VERSION 5.7 ;
  NOWIREEXTENSIONATPIN ON ;
  DIVIDERCHAR "/" ;
  BUSBITCHARS "[]" ;
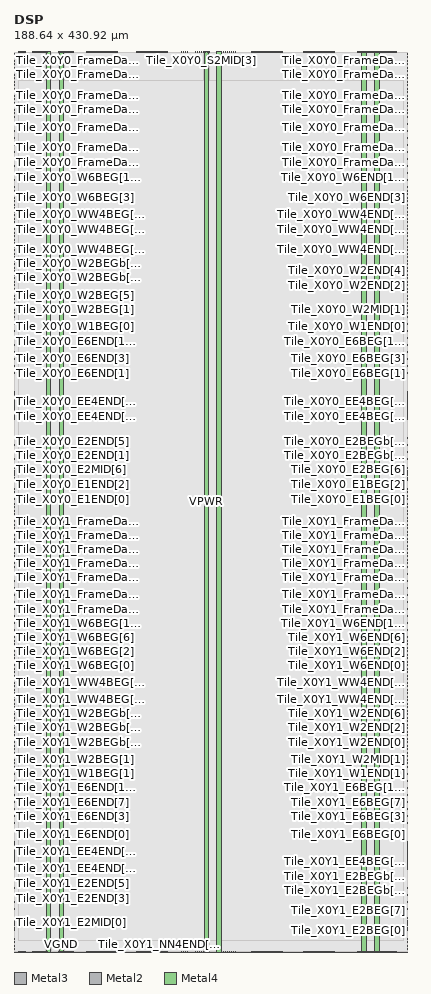
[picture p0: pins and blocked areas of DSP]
MACRO DSP
  CLASS BLOCK ;
  FOREIGN DSP ;
  ORIGIN 0.000 0.000 ;
  SIZE 188.640 BY 430.920 ;
  PIN Tile_X0Y0_E1BEG[0]
    DIRECTION OUTPUT ;
    USE SIGNAL ;
    ANTENNADIFFAREA 2.724000 ;
    PORT
      LAYER Metal3 ;
        RECT 188.240 216.520 188.640 216.920 ;
    END
  END Tile_X0Y0_E1BEG[0]
  PIN Tile_X0Y0_E1BEG[1]
    DIRECTION OUTPUT ;
    USE SIGNAL ;
    ANTENNADIFFAREA 2.724000 ;
    PORT
      LAYER Metal3 ;
        RECT 188.240 218.200 188.640 218.600 ;
    END
  END Tile_X0Y0_E1BEG[1]
  PIN Tile_X0Y0_E1BEG[2]
    DIRECTION OUTPUT ;
    USE SIGNAL ;
    ANTENNADIFFAREA 2.724000 ;
    PORT
      LAYER Metal3 ;
        RECT 188.240 219.880 188.640 220.280 ;
    END
  END Tile_X0Y0_E1BEG[2]
  PIN Tile_X0Y0_E1BEG[3]
    DIRECTION OUTPUT ;
    USE SIGNAL ;
    ANTENNADIFFAREA 2.724000 ;
    PORT
      LAYER Metal3 ;
        RECT 188.240 221.560 188.640 221.960 ;
    END
  END Tile_X0Y0_E1BEG[3]
  PIN Tile_X0Y0_E1END[0]
    DIRECTION INPUT ;
    USE SIGNAL ;
    ANTENNAGATEAREA 1.320800 ;
    PORT
      LAYER Metal3 ;
        RECT 0.000 216.520 0.400 216.920 ;
    END
  END Tile_X0Y0_E1END[0]
  PIN Tile_X0Y0_E1END[1]
    DIRECTION INPUT ;
    USE SIGNAL ;
    ANTENNAGATEAREA 1.899300 ;
    PORT
      LAYER Metal3 ;
        RECT 0.000 218.200 0.400 218.600 ;
    END
  END Tile_X0Y0_E1END[1]
  PIN Tile_X0Y0_E1END[2]
    DIRECTION INPUT ;
    USE SIGNAL ;
    ANTENNAGATEAREA 2.407100 ;
    PORT
      LAYER Metal3 ;
        RECT 0.000 219.880 0.400 220.280 ;
    END
  END Tile_X0Y0_E1END[2]
  PIN Tile_X0Y0_E1END[3]
    DIRECTION INPUT ;
    USE SIGNAL ;
    ANTENNAGATEAREA 2.397200 ;
    PORT
      LAYER Metal3 ;
        RECT 0.000 221.560 0.400 221.960 ;
    END
  END Tile_X0Y0_E1END[3]
  PIN Tile_X0Y0_E2BEG[0]
    DIRECTION OUTPUT ;
    USE SIGNAL ;
    ANTENNADIFFAREA 2.724000 ;
    PORT
      LAYER Metal3 ;
        RECT 188.240 225.760 188.640 226.160 ;
    END
  END Tile_X0Y0_E2BEG[0]
  PIN Tile_X0Y0_E2BEG[1]
    DIRECTION OUTPUT ;
    USE SIGNAL ;
    ANTENNADIFFAREA 2.724000 ;
    PORT
      LAYER Metal3 ;
        RECT 188.240 226.600 188.640 227.000 ;
    END
  END Tile_X0Y0_E2BEG[1]
  PIN Tile_X0Y0_E2BEG[2]
    DIRECTION OUTPUT ;
    USE SIGNAL ;
    ANTENNADIFFAREA 2.724000 ;
    PORT
      LAYER Metal3 ;
        RECT 188.240 227.440 188.640 227.840 ;
    END
  END Tile_X0Y0_E2BEG[2]
  PIN Tile_X0Y0_E2BEG[3]
    DIRECTION OUTPUT ;
    USE SIGNAL ;
    ANTENNADIFFAREA 2.724000 ;
    PORT
      LAYER Metal3 ;
        RECT 188.240 228.280 188.640 228.680 ;
    END
  END Tile_X0Y0_E2BEG[3]
  PIN Tile_X0Y0_E2BEG[4]
    DIRECTION OUTPUT ;
    USE SIGNAL ;
    ANTENNADIFFAREA 2.724000 ;
    PORT
      LAYER Metal3 ;
        RECT 188.240 229.120 188.640 229.520 ;
    END
  END Tile_X0Y0_E2BEG[4]
  PIN Tile_X0Y0_E2BEG[5]
    DIRECTION OUTPUT ;
    USE SIGNAL ;
    ANTENNADIFFAREA 2.724000 ;
    PORT
      LAYER Metal3 ;
        RECT 188.240 229.960 188.640 230.360 ;
    END
  END Tile_X0Y0_E2BEG[5]
  PIN Tile_X0Y0_E2BEG[6]
    DIRECTION OUTPUT ;
    USE SIGNAL ;
    ANTENNADIFFAREA 2.724000 ;
    PORT
      LAYER Metal3 ;
        RECT 188.240 230.800 188.640 231.200 ;
    END
  END Tile_X0Y0_E2BEG[6]
  PIN Tile_X0Y0_E2BEG[7]
    DIRECTION OUTPUT ;
    USE SIGNAL ;
    ANTENNADIFFAREA 2.724000 ;
    PORT
      LAYER Metal3 ;
        RECT 188.240 231.640 188.640 232.040 ;
    END
  END Tile_X0Y0_E2BEG[7]
  PIN Tile_X0Y0_E2BEGb[0]
    DIRECTION OUTPUT ;
    USE SIGNAL ;
    ANTENNADIFFAREA 2.724000 ;
    PORT
      LAYER Metal3 ;
        RECT 188.240 235.840 188.640 236.240 ;
    END
  END Tile_X0Y0_E2BEGb[0]
  PIN Tile_X0Y0_E2BEGb[1]
    DIRECTION OUTPUT ;
    USE SIGNAL ;
    ANTENNADIFFAREA 2.724000 ;
    PORT
      LAYER Metal3 ;
        RECT 188.240 237.520 188.640 237.920 ;
    END
  END Tile_X0Y0_E2BEGb[1]
  PIN Tile_X0Y0_E2BEGb[2]
    DIRECTION OUTPUT ;
    USE SIGNAL ;
    ANTENNADIFFAREA 2.724000 ;
    PORT
      LAYER Metal3 ;
        RECT 188.240 239.200 188.640 239.600 ;
    END
  END Tile_X0Y0_E2BEGb[2]
  PIN Tile_X0Y0_E2BEGb[3]
    DIRECTION OUTPUT ;
    USE SIGNAL ;
    ANTENNADIFFAREA 2.724000 ;
    PORT
      LAYER Metal3 ;
        RECT 188.240 240.880 188.640 241.280 ;
    END
  END Tile_X0Y0_E2BEGb[3]
  PIN Tile_X0Y0_E2BEGb[4]
    DIRECTION OUTPUT ;
    USE SIGNAL ;
    ANTENNADIFFAREA 2.724000 ;
    PORT
      LAYER Metal3 ;
        RECT 188.240 242.560 188.640 242.960 ;
    END
  END Tile_X0Y0_E2BEGb[4]
  PIN Tile_X0Y0_E2BEGb[5]
    DIRECTION OUTPUT ;
    USE SIGNAL ;
    ANTENNADIFFAREA 2.724000 ;
    PORT
      LAYER Metal3 ;
        RECT 188.240 244.240 188.640 244.640 ;
    END
  END Tile_X0Y0_E2BEGb[5]
  PIN Tile_X0Y0_E2BEGb[6]
    DIRECTION OUTPUT ;
    USE SIGNAL ;
    ANTENNADIFFAREA 2.724000 ;
    PORT
      LAYER Metal3 ;
        RECT 188.240 245.920 188.640 246.320 ;
    END
  END Tile_X0Y0_E2BEGb[6]
  PIN Tile_X0Y0_E2BEGb[7]
    DIRECTION OUTPUT ;
    USE SIGNAL ;
    ANTENNADIFFAREA 2.724000 ;
    PORT
      LAYER Metal3 ;
        RECT 188.240 247.600 188.640 248.000 ;
    END
  END Tile_X0Y0_E2BEGb[7]
  PIN Tile_X0Y0_E2END[0]
    DIRECTION INPUT ;
    USE SIGNAL ;
    ANTENNAGATEAREA 0.865800 ;
    PORT
      LAYER Metal3 ;
        RECT 0.000 235.840 0.400 236.240 ;
    END
  END Tile_X0Y0_E2END[0]
  PIN Tile_X0Y0_E2END[1]
    DIRECTION INPUT ;
    USE SIGNAL ;
    ANTENNAGATEAREA 0.820300 ;
    PORT
      LAYER Metal3 ;
        RECT 0.000 237.520 0.400 237.920 ;
    END
  END Tile_X0Y0_E2END[1]
  PIN Tile_X0Y0_E2END[2]
    DIRECTION INPUT ;
    USE SIGNAL ;
    ANTENNAGATEAREA 1.094600 ;
    PORT
      LAYER Metal3 ;
        RECT 0.000 239.200 0.400 239.600 ;
    END
  END Tile_X0Y0_E2END[2]
  PIN Tile_X0Y0_E2END[3]
    DIRECTION INPUT ;
    USE SIGNAL ;
    ANTENNAGATEAREA 1.123200 ;
    PORT
      LAYER Metal3 ;
        RECT 0.000 240.880 0.400 241.280 ;
    END
  END Tile_X0Y0_E2END[3]
  PIN Tile_X0Y0_E2END[4]
    DIRECTION INPUT ;
    USE SIGNAL ;
    ANTENNAGATEAREA 1.107600 ;
    PORT
      LAYER Metal3 ;
        RECT 0.000 242.560 0.400 242.960 ;
    END
  END Tile_X0Y0_E2END[4]
  PIN Tile_X0Y0_E2END[5]
    DIRECTION INPUT ;
    USE SIGNAL ;
    ANTENNAGATEAREA 1.292200 ;
    PORT
      LAYER Metal3 ;
        RECT 0.000 244.240 0.400 244.640 ;
    END
  END Tile_X0Y0_E2END[5]
  PIN Tile_X0Y0_E2END[6]
    DIRECTION INPUT ;
    USE SIGNAL ;
    ANTENNAGATEAREA 1.123200 ;
    PORT
      LAYER Metal3 ;
        RECT 0.000 245.920 0.400 246.320 ;
    END
  END Tile_X0Y0_E2END[6]
  PIN Tile_X0Y0_E2END[7]
    DIRECTION INPUT ;
    USE SIGNAL ;
    ANTENNAGATEAREA 0.936000 ;
    ANTENNADIFFAREA 50.384998 ;
    PORT
      LAYER Metal3 ;
        RECT 0.000 247.600 0.400 248.000 ;
    END
  END Tile_X0Y0_E2END[7]
  PIN Tile_X0Y0_E2MID[0]
    DIRECTION INPUT ;
    USE SIGNAL ;
    ANTENNAGATEAREA 0.820300 ;
    ANTENNADIFFAREA 32.246399 ;
    PORT
      LAYER Metal3 ;
        RECT 0.000 225.760 0.400 226.160 ;
    END
  END Tile_X0Y0_E2MID[0]
  PIN Tile_X0Y0_E2MID[1]
    DIRECTION INPUT ;
    USE SIGNAL ;
    ANTENNAGATEAREA 1.046500 ;
    PORT
      LAYER Metal3 ;
        RECT 0.000 226.600 0.400 227.000 ;
    END
  END Tile_X0Y0_E2MID[1]
  PIN Tile_X0Y0_E2MID[2]
    DIRECTION INPUT ;
    USE SIGNAL ;
    ANTENNAGATEAREA 0.877500 ;
    ANTENNADIFFAREA 32.246399 ;
    PORT
      LAYER Metal3 ;
        RECT 0.000 227.440 0.400 227.840 ;
    END
  END Tile_X0Y0_E2MID[2]
  PIN Tile_X0Y0_E2MID[3]
    DIRECTION INPUT ;
    USE SIGNAL ;
    ANTENNAGATEAREA 1.059500 ;
    ANTENNADIFFAREA 12.092400 ;
    PORT
      LAYER Metal3 ;
        RECT 0.000 228.280 0.400 228.680 ;
    END
  END Tile_X0Y0_E2MID[3]
  PIN Tile_X0Y0_E2MID[4]
    DIRECTION INPUT ;
    USE SIGNAL ;
    ANTENNAGATEAREA 0.635700 ;
    ANTENNADIFFAREA 18.138599 ;
    PORT
      LAYER Metal3 ;
        RECT 0.000 229.120 0.400 229.520 ;
    END
  END Tile_X0Y0_E2MID[4]
  PIN Tile_X0Y0_E2MID[5]
    DIRECTION INPUT ;
    USE SIGNAL ;
    ANTENNAGATEAREA 0.422500 ;
    ANTENNADIFFAREA 8.061600 ;
    PORT
      LAYER Metal3 ;
        RECT 0.000 229.960 0.400 230.360 ;
    END
  END Tile_X0Y0_E2MID[5]
  PIN Tile_X0Y0_E2MID[6]
    DIRECTION INPUT ;
    USE SIGNAL ;
    ANTENNAGATEAREA 0.635700 ;
    ANTENNADIFFAREA 18.138599 ;
    PORT
      LAYER Metal3 ;
        RECT 0.000 230.800 0.400 231.200 ;
    END
  END Tile_X0Y0_E2MID[6]
  PIN Tile_X0Y0_E2MID[7]
    DIRECTION INPUT ;
    USE SIGNAL ;
    ANTENNAGATEAREA 0.422500 ;
    ANTENNADIFFAREA 8.061600 ;
    PORT
      LAYER Metal3 ;
        RECT 0.000 231.640 0.400 232.040 ;
    END
  END Tile_X0Y0_E2MID[7]
  PIN Tile_X0Y0_E6BEG[0]
    DIRECTION OUTPUT ;
    USE SIGNAL ;
    ANTENNADIFFAREA 2.724000 ;
    PORT
      LAYER Metal3 ;
        RECT 188.240 275.320 188.640 275.720 ;
    END
  END Tile_X0Y0_E6BEG[0]
  PIN Tile_X0Y0_E6BEG[10]
    DIRECTION OUTPUT ;
    USE SIGNAL ;
    ANTENNADIFFAREA 2.724000 ;
    PORT
      LAYER Metal3 ;
        RECT 188.240 292.120 188.640 292.520 ;
    END
  END Tile_X0Y0_E6BEG[10]
  PIN Tile_X0Y0_E6BEG[11]
    DIRECTION OUTPUT ;
    USE SIGNAL ;
    ANTENNADIFFAREA 2.724000 ;
    PORT
      LAYER Metal3 ;
        RECT 188.240 293.800 188.640 294.200 ;
    END
  END Tile_X0Y0_E6BEG[11]
  PIN Tile_X0Y0_E6BEG[1]
    DIRECTION OUTPUT ;
    USE SIGNAL ;
    ANTENNADIFFAREA 2.724000 ;
    PORT
      LAYER Metal3 ;
        RECT 188.240 277.000 188.640 277.400 ;
    END
  END Tile_X0Y0_E6BEG[1]
  PIN Tile_X0Y0_E6BEG[2]
    DIRECTION OUTPUT ;
    USE SIGNAL ;
    ANTENNADIFFAREA 2.724000 ;
    PORT
      LAYER Metal3 ;
        RECT 188.240 278.680 188.640 279.080 ;
    END
  END Tile_X0Y0_E6BEG[2]
  PIN Tile_X0Y0_E6BEG[3]
    DIRECTION OUTPUT ;
    USE SIGNAL ;
    ANTENNADIFFAREA 2.724000 ;
    PORT
      LAYER Metal3 ;
        RECT 188.240 280.360 188.640 280.760 ;
    END
  END Tile_X0Y0_E6BEG[3]
  PIN Tile_X0Y0_E6BEG[4]
    DIRECTION OUTPUT ;
    USE SIGNAL ;
    ANTENNADIFFAREA 2.724000 ;
    PORT
      LAYER Metal3 ;
        RECT 188.240 282.040 188.640 282.440 ;
    END
  END Tile_X0Y0_E6BEG[4]
  PIN Tile_X0Y0_E6BEG[5]
    DIRECTION OUTPUT ;
    USE SIGNAL ;
    ANTENNADIFFAREA 2.724000 ;
    PORT
      LAYER Metal3 ;
        RECT 188.240 283.720 188.640 284.120 ;
    END
  END Tile_X0Y0_E6BEG[5]
  PIN Tile_X0Y0_E6BEG[6]
    DIRECTION OUTPUT ;
    USE SIGNAL ;
    ANTENNADIFFAREA 2.724000 ;
    PORT
      LAYER Metal3 ;
        RECT 188.240 285.400 188.640 285.800 ;
    END
  END Tile_X0Y0_E6BEG[6]
  PIN Tile_X0Y0_E6BEG[7]
    DIRECTION OUTPUT ;
    USE SIGNAL ;
    ANTENNADIFFAREA 2.724000 ;
    PORT
      LAYER Metal3 ;
        RECT 188.240 287.080 188.640 287.480 ;
    END
  END Tile_X0Y0_E6BEG[7]
  PIN Tile_X0Y0_E6BEG[8]
    DIRECTION OUTPUT ;
    USE SIGNAL ;
    ANTENNADIFFAREA 2.724000 ;
    PORT
      LAYER Metal3 ;
        RECT 188.240 288.760 188.640 289.160 ;
    END
  END Tile_X0Y0_E6BEG[8]
  PIN Tile_X0Y0_E6BEG[9]
    DIRECTION OUTPUT ;
    USE SIGNAL ;
    ANTENNADIFFAREA 2.724000 ;
    PORT
      LAYER Metal3 ;
        RECT 188.240 290.440 188.640 290.840 ;
    END
  END Tile_X0Y0_E6BEG[9]
  PIN Tile_X0Y0_E6END[0]
    DIRECTION INPUT ;
    USE SIGNAL ;
    ANTENNAGATEAREA 2.239400 ;
    PORT
      LAYER Metal3 ;
        RECT 0.000 275.320 0.400 275.720 ;
    END
  END Tile_X0Y0_E6END[0]
  PIN Tile_X0Y0_E6END[10]
    DIRECTION INPUT ;
    USE SIGNAL ;
    ANTENNAGATEAREA 0.180700 ;
    PORT
      LAYER Metal3 ;
        RECT 0.000 292.120 0.400 292.520 ;
    END
  END Tile_X0Y0_E6END[10]
  PIN Tile_X0Y0_E6END[11]
    DIRECTION INPUT ;
    USE SIGNAL ;
    ANTENNAGATEAREA 0.180700 ;
    PORT
      LAYER Metal3 ;
        RECT 0.000 293.800 0.400 294.200 ;
    END
  END Tile_X0Y0_E6END[11]
  PIN Tile_X0Y0_E6END[1]
    DIRECTION INPUT ;
    USE SIGNAL ;
    ANTENNAGATEAREA 2.547000 ;
    PORT
      LAYER Metal3 ;
        RECT 0.000 277.000 0.400 277.400 ;
    END
  END Tile_X0Y0_E6END[1]
  PIN Tile_X0Y0_E6END[2]
    DIRECTION INPUT ;
    USE SIGNAL ;
    ANTENNAGATEAREA 0.180700 ;
    PORT
      LAYER Metal3 ;
        RECT 0.000 278.680 0.400 279.080 ;
    END
  END Tile_X0Y0_E6END[2]
  PIN Tile_X0Y0_E6END[3]
    DIRECTION INPUT ;
    USE SIGNAL ;
    ANTENNAGATEAREA 0.180700 ;
    PORT
      LAYER Metal3 ;
        RECT 0.000 280.360 0.400 280.760 ;
    END
  END Tile_X0Y0_E6END[3]
  PIN Tile_X0Y0_E6END[4]
    DIRECTION INPUT ;
    USE SIGNAL ;
    ANTENNAGATEAREA 0.180700 ;
    PORT
      LAYER Metal3 ;
        RECT 0.000 282.040 0.400 282.440 ;
    END
  END Tile_X0Y0_E6END[4]
  PIN Tile_X0Y0_E6END[5]
    DIRECTION INPUT ;
    USE SIGNAL ;
    ANTENNAGATEAREA 0.180700 ;
    PORT
      LAYER Metal3 ;
        RECT 0.000 283.720 0.400 284.120 ;
    END
  END Tile_X0Y0_E6END[5]
  PIN Tile_X0Y0_E6END[6]
    DIRECTION INPUT ;
    USE SIGNAL ;
    ANTENNAGATEAREA 0.180700 ;
    PORT
      LAYER Metal3 ;
        RECT 0.000 285.400 0.400 285.800 ;
    END
  END Tile_X0Y0_E6END[6]
  PIN Tile_X0Y0_E6END[7]
    DIRECTION INPUT ;
    USE SIGNAL ;
    ANTENNAGATEAREA 0.180700 ;
    PORT
      LAYER Metal3 ;
        RECT 0.000 287.080 0.400 287.480 ;
    END
  END Tile_X0Y0_E6END[7]
  PIN Tile_X0Y0_E6END[8]
    DIRECTION INPUT ;
    USE SIGNAL ;
    ANTENNAGATEAREA 0.180700 ;
    PORT
      LAYER Metal3 ;
        RECT 0.000 288.760 0.400 289.160 ;
    END
  END Tile_X0Y0_E6END[8]
  PIN Tile_X0Y0_E6END[9]
    DIRECTION INPUT ;
    USE SIGNAL ;
    ANTENNAGATEAREA 0.180700 ;
    PORT
      LAYER Metal3 ;
        RECT 0.000 290.440 0.400 290.840 ;
    END
  END Tile_X0Y0_E6END[9]
  PIN Tile_X0Y0_EE4BEG[0]
    DIRECTION OUTPUT ;
    USE SIGNAL ;
    ANTENNADIFFAREA 2.724000 ;
    PORT
      LAYER Metal3 ;
        RECT 188.240 255.160 188.640 255.560 ;
    END
  END Tile_X0Y0_EE4BEG[0]
  PIN Tile_X0Y0_EE4BEG[10]
    DIRECTION OUTPUT ;
    USE SIGNAL ;
    ANTENNADIFFAREA 2.724000 ;
    PORT
      LAYER Metal3 ;
        RECT 188.240 263.560 188.640 263.960 ;
    END
  END Tile_X0Y0_EE4BEG[10]
  PIN Tile_X0Y0_EE4BEG[11]
    DIRECTION OUTPUT ;
    USE SIGNAL ;
    ANTENNADIFFAREA 2.724000 ;
    PORT
      LAYER Metal3 ;
        RECT 188.240 264.400 188.640 264.800 ;
    END
  END Tile_X0Y0_EE4BEG[11]
  PIN Tile_X0Y0_EE4BEG[12]
    DIRECTION OUTPUT ;
    USE SIGNAL ;
    ANTENNADIFFAREA 2.724000 ;
    PORT
      LAYER Metal3 ;
        RECT 188.240 265.240 188.640 265.640 ;
    END
  END Tile_X0Y0_EE4BEG[12]
  PIN Tile_X0Y0_EE4BEG[13]
    DIRECTION OUTPUT ;
    USE SIGNAL ;
    ANTENNADIFFAREA 2.724000 ;
    PORT
      LAYER Metal3 ;
        RECT 188.240 266.080 188.640 266.480 ;
    END
  END Tile_X0Y0_EE4BEG[13]
  PIN Tile_X0Y0_EE4BEG[14]
    DIRECTION OUTPUT ;
    USE SIGNAL ;
    ANTENNADIFFAREA 2.724000 ;
    PORT
      LAYER Metal3 ;
        RECT 188.240 266.920 188.640 267.320 ;
    END
  END Tile_X0Y0_EE4BEG[14]
  PIN Tile_X0Y0_EE4BEG[15]
    DIRECTION OUTPUT ;
    USE SIGNAL ;
    ANTENNADIFFAREA 2.724000 ;
    PORT
      LAYER Metal3 ;
        RECT 188.240 267.760 188.640 268.160 ;
    END
  END Tile_X0Y0_EE4BEG[15]
  PIN Tile_X0Y0_EE4BEG[1]
    DIRECTION OUTPUT ;
    USE SIGNAL ;
    ANTENNADIFFAREA 2.724000 ;
    PORT
      LAYER Metal3 ;
        RECT 188.240 256.000 188.640 256.400 ;
    END
  END Tile_X0Y0_EE4BEG[1]
  PIN Tile_X0Y0_EE4BEG[2]
    DIRECTION OUTPUT ;
    USE SIGNAL ;
    ANTENNADIFFAREA 2.724000 ;
    PORT
      LAYER Metal3 ;
        RECT 188.240 256.840 188.640 257.240 ;
    END
  END Tile_X0Y0_EE4BEG[2]
  PIN Tile_X0Y0_EE4BEG[3]
    DIRECTION OUTPUT ;
    USE SIGNAL ;
    ANTENNADIFFAREA 2.724000 ;
    PORT
      LAYER Metal3 ;
        RECT 188.240 257.680 188.640 258.080 ;
    END
  END Tile_X0Y0_EE4BEG[3]
  PIN Tile_X0Y0_EE4BEG[4]
    DIRECTION OUTPUT ;
    USE SIGNAL ;
    ANTENNADIFFAREA 2.724000 ;
    PORT
      LAYER Metal3 ;
        RECT 188.240 258.520 188.640 258.920 ;
    END
  END Tile_X0Y0_EE4BEG[4]
  PIN Tile_X0Y0_EE4BEG[5]
    DIRECTION OUTPUT ;
    USE SIGNAL ;
    ANTENNADIFFAREA 2.724000 ;
    PORT
      LAYER Metal3 ;
        RECT 188.240 259.360 188.640 259.760 ;
    END
  END Tile_X0Y0_EE4BEG[5]
  PIN Tile_X0Y0_EE4BEG[6]
    DIRECTION OUTPUT ;
    USE SIGNAL ;
    ANTENNADIFFAREA 2.724000 ;
    PORT
      LAYER Metal3 ;
        RECT 188.240 260.200 188.640 260.600 ;
    END
  END Tile_X0Y0_EE4BEG[6]
  PIN Tile_X0Y0_EE4BEG[7]
    DIRECTION OUTPUT ;
    USE SIGNAL ;
    ANTENNADIFFAREA 2.724000 ;
    PORT
      LAYER Metal3 ;
        RECT 188.240 261.040 188.640 261.440 ;
    END
  END Tile_X0Y0_EE4BEG[7]
  PIN Tile_X0Y0_EE4BEG[8]
    DIRECTION OUTPUT ;
    USE SIGNAL ;
    ANTENNADIFFAREA 2.724000 ;
    PORT
      LAYER Metal3 ;
        RECT 188.240 261.880 188.640 262.280 ;
    END
  END Tile_X0Y0_EE4BEG[8]
  PIN Tile_X0Y0_EE4BEG[9]
    DIRECTION OUTPUT ;
    USE SIGNAL ;
    ANTENNADIFFAREA 2.724000 ;
    PORT
      LAYER Metal3 ;
        RECT 188.240 262.720 188.640 263.120 ;
    END
  END Tile_X0Y0_EE4BEG[9]
  PIN Tile_X0Y0_EE4END[0]
    DIRECTION INPUT ;
    USE SIGNAL ;
    ANTENNAGATEAREA 0.607100 ;
    PORT
      LAYER Metal3 ;
        RECT 0.000 255.160 0.400 255.560 ;
    END
  END Tile_X0Y0_EE4END[0]
  PIN Tile_X0Y0_EE4END[10]
    DIRECTION INPUT ;
    USE SIGNAL ;
    ANTENNAGATEAREA 0.180700 ;
    PORT
      LAYER Metal3 ;
        RECT 0.000 263.560 0.400 263.960 ;
    END
  END Tile_X0Y0_EE4END[10]
  PIN Tile_X0Y0_EE4END[11]
    DIRECTION INPUT ;
    USE SIGNAL ;
    ANTENNAGATEAREA 0.180700 ;
    PORT
      LAYER Metal3 ;
        RECT 0.000 264.400 0.400 264.800 ;
    END
  END Tile_X0Y0_EE4END[11]
  PIN Tile_X0Y0_EE4END[12]
    DIRECTION INPUT ;
    USE SIGNAL ;
    ANTENNAGATEAREA 0.180700 ;
    PORT
      LAYER Metal3 ;
        RECT 0.000 265.240 0.400 265.640 ;
    END
  END Tile_X0Y0_EE4END[12]
  PIN Tile_X0Y0_EE4END[13]
    DIRECTION INPUT ;
    USE SIGNAL ;
    ANTENNAGATEAREA 0.180700 ;
    PORT
      LAYER Metal3 ;
        RECT 0.000 266.080 0.400 266.480 ;
    END
  END Tile_X0Y0_EE4END[13]
  PIN Tile_X0Y0_EE4END[14]
    DIRECTION INPUT ;
    USE SIGNAL ;
    ANTENNAGATEAREA 0.180700 ;
    PORT
      LAYER Metal3 ;
        RECT 0.000 266.920 0.400 267.320 ;
    END
  END Tile_X0Y0_EE4END[14]
  PIN Tile_X0Y0_EE4END[15]
    DIRECTION INPUT ;
    USE SIGNAL ;
    ANTENNAGATEAREA 0.180700 ;
    PORT
      LAYER Metal3 ;
        RECT 0.000 267.760 0.400 268.160 ;
    END
  END Tile_X0Y0_EE4END[15]
  PIN Tile_X0Y0_EE4END[1]
    DIRECTION INPUT ;
    USE SIGNAL ;
    ANTENNAGATEAREA 0.681200 ;
    PORT
      LAYER Metal3 ;
        RECT 0.000 256.000 0.400 256.400 ;
    END
  END Tile_X0Y0_EE4END[1]
  PIN Tile_X0Y0_EE4END[2]
    DIRECTION INPUT ;
    USE SIGNAL ;
    ANTENNAGATEAREA 0.718400 ;
    PORT
      LAYER Metal3 ;
        RECT 0.000 256.840 0.400 257.240 ;
    END
  END Tile_X0Y0_EE4END[2]
  PIN Tile_X0Y0_EE4END[3]
    DIRECTION INPUT ;
    USE SIGNAL ;
    ANTENNAGATEAREA 0.492200 ;
    PORT
      LAYER Metal3 ;
        RECT 0.000 257.680 0.400 258.080 ;
    END
  END Tile_X0Y0_EE4END[3]
  PIN Tile_X0Y0_EE4END[4]
    DIRECTION INPUT ;
    USE SIGNAL ;
    ANTENNAGATEAREA 0.180700 ;
    PORT
      LAYER Metal3 ;
        RECT 0.000 258.520 0.400 258.920 ;
    END
  END Tile_X0Y0_EE4END[4]
  PIN Tile_X0Y0_EE4END[5]
    DIRECTION INPUT ;
    USE SIGNAL ;
    ANTENNAGATEAREA 0.180700 ;
    PORT
      LAYER Metal3 ;
        RECT 0.000 259.360 0.400 259.760 ;
    END
  END Tile_X0Y0_EE4END[5]
  PIN Tile_X0Y0_EE4END[6]
    DIRECTION INPUT ;
    USE SIGNAL ;
    ANTENNAGATEAREA 0.180700 ;
    PORT
      LAYER Metal3 ;
        RECT 0.000 260.200 0.400 260.600 ;
    END
  END Tile_X0Y0_EE4END[6]
  PIN Tile_X0Y0_EE4END[7]
    DIRECTION INPUT ;
    USE SIGNAL ;
    ANTENNAGATEAREA 0.180700 ;
    PORT
      LAYER Metal3 ;
        RECT 0.000 261.040 0.400 261.440 ;
    END
  END Tile_X0Y0_EE4END[7]
  PIN Tile_X0Y0_EE4END[8]
    DIRECTION INPUT ;
    USE SIGNAL ;
    ANTENNAGATEAREA 0.180700 ;
    PORT
      LAYER Metal3 ;
        RECT 0.000 261.880 0.400 262.280 ;
    END
  END Tile_X0Y0_EE4END[8]
  PIN Tile_X0Y0_EE4END[9]
    DIRECTION INPUT ;
    USE SIGNAL ;
    ANTENNAGATEAREA 0.180700 ;
    PORT
      LAYER Metal3 ;
        RECT 0.000 262.720 0.400 263.120 ;
    END
  END Tile_X0Y0_EE4END[9]
  PIN Tile_X0Y0_FrameData[0]
    DIRECTION INPUT ;
    USE SIGNAL ;
    ANTENNAGATEAREA 2.349100 ;
    PORT
      LAYER Metal3 ;
        RECT 0.000 377.800 0.400 378.200 ;
    END
  END Tile_X0Y0_FrameData[0]
  PIN Tile_X0Y0_FrameData[10]
    DIRECTION INPUT ;
    USE SIGNAL ;
    ANTENNAGATEAREA 2.529800 ;
    PORT
      LAYER Metal3 ;
        RECT 0.000 394.600 0.400 395.000 ;
    END
  END Tile_X0Y0_FrameData[10]
  PIN Tile_X0Y0_FrameData[11]
    DIRECTION INPUT ;
    USE SIGNAL ;
    ANTENNAGATEAREA 2.529800 ;
    PORT
      LAYER Metal3 ;
        RECT 0.000 396.280 0.400 396.680 ;
    END
  END Tile_X0Y0_FrameData[11]
  PIN Tile_X0Y0_FrameData[12]
    DIRECTION INPUT ;
    USE SIGNAL ;
    ANTENNAGATEAREA 2.529800 ;
    PORT
      LAYER Metal3 ;
        RECT 0.000 397.960 0.400 398.360 ;
    END
  END Tile_X0Y0_FrameData[12]
  PIN Tile_X0Y0_FrameData[13]
    DIRECTION INPUT ;
    USE SIGNAL ;
    ANTENNAGATEAREA 2.529800 ;
    PORT
      LAYER Metal3 ;
        RECT 0.000 399.640 0.400 400.040 ;
    END
  END Tile_X0Y0_FrameData[13]
  PIN Tile_X0Y0_FrameData[14]
    DIRECTION INPUT ;
    USE SIGNAL ;
    ANTENNAGATEAREA 2.529800 ;
    PORT
      LAYER Metal3 ;
        RECT 0.000 401.320 0.400 401.720 ;
    END
  END Tile_X0Y0_FrameData[14]
  PIN Tile_X0Y0_FrameData[15]
    DIRECTION INPUT ;
    USE SIGNAL ;
    ANTENNAGATEAREA 2.529800 ;
    PORT
      LAYER Metal3 ;
        RECT 0.000 403.000 0.400 403.400 ;
    END
  END Tile_X0Y0_FrameData[15]
  PIN Tile_X0Y0_FrameData[16]
    DIRECTION INPUT ;
    USE SIGNAL ;
    ANTENNAGATEAREA 2.529800 ;
    PORT
      LAYER Metal3 ;
        RECT 0.000 404.680 0.400 405.080 ;
    END
  END Tile_X0Y0_FrameData[16]
  PIN Tile_X0Y0_FrameData[17]
    DIRECTION INPUT ;
    USE SIGNAL ;
    ANTENNAGATEAREA 2.529800 ;
    PORT
      LAYER Metal3 ;
        RECT 0.000 406.360 0.400 406.760 ;
    END
  END Tile_X0Y0_FrameData[17]
  PIN Tile_X0Y0_FrameData[18]
    DIRECTION INPUT ;
    USE SIGNAL ;
    ANTENNAGATEAREA 2.529800 ;
    PORT
      LAYER Metal3 ;
        RECT 0.000 408.040 0.400 408.440 ;
    END
  END Tile_X0Y0_FrameData[18]
  PIN Tile_X0Y0_FrameData[19]
    DIRECTION INPUT ;
    USE SIGNAL ;
    ANTENNAGATEAREA 2.529800 ;
    PORT
      LAYER Metal3 ;
        RECT 0.000 409.720 0.400 410.120 ;
    END
  END Tile_X0Y0_FrameData[19]
  PIN Tile_X0Y0_FrameData[1]
    DIRECTION INPUT ;
    USE SIGNAL ;
    ANTENNAGATEAREA 2.349100 ;
    PORT
      LAYER Metal3 ;
        RECT 0.000 379.480 0.400 379.880 ;
    END
  END Tile_X0Y0_FrameData[1]
  PIN Tile_X0Y0_FrameData[20]
    DIRECTION INPUT ;
    USE SIGNAL ;
    ANTENNAGATEAREA 2.529800 ;
    PORT
      LAYER Metal3 ;
        RECT 0.000 411.400 0.400 411.800 ;
    END
  END Tile_X0Y0_FrameData[20]
  PIN Tile_X0Y0_FrameData[21]
    DIRECTION INPUT ;
    USE SIGNAL ;
    ANTENNAGATEAREA 2.529800 ;
    PORT
      LAYER Metal3 ;
        RECT 0.000 413.080 0.400 413.480 ;
    END
  END Tile_X0Y0_FrameData[21]
  PIN Tile_X0Y0_FrameData[22]
    DIRECTION INPUT ;
    USE SIGNAL ;
    ANTENNAGATEAREA 2.529800 ;
    PORT
      LAYER Metal3 ;
        RECT 0.000 414.760 0.400 415.160 ;
    END
  END Tile_X0Y0_FrameData[22]
  PIN Tile_X0Y0_FrameData[23]
    DIRECTION INPUT ;
    USE SIGNAL ;
    ANTENNAGATEAREA 2.529800 ;
    PORT
      LAYER Metal3 ;
        RECT 0.000 416.440 0.400 416.840 ;
    END
  END Tile_X0Y0_FrameData[23]
  PIN Tile_X0Y0_FrameData[24]
    DIRECTION INPUT ;
    USE SIGNAL ;
    ANTENNAGATEAREA 2.529800 ;
    PORT
      LAYER Metal3 ;
        RECT 0.000 418.120 0.400 418.520 ;
    END
  END Tile_X0Y0_FrameData[24]
  PIN Tile_X0Y0_FrameData[25]
    DIRECTION INPUT ;
    USE SIGNAL ;
    ANTENNAGATEAREA 2.529800 ;
    PORT
      LAYER Metal3 ;
        RECT 0.000 419.800 0.400 420.200 ;
    END
  END Tile_X0Y0_FrameData[25]
  PIN Tile_X0Y0_FrameData[26]
    DIRECTION INPUT ;
    USE SIGNAL ;
    ANTENNAGATEAREA 2.529800 ;
    PORT
      LAYER Metal3 ;
        RECT 0.000 421.480 0.400 421.880 ;
    END
  END Tile_X0Y0_FrameData[26]
  PIN Tile_X0Y0_FrameData[27]
    DIRECTION INPUT ;
    USE SIGNAL ;
    ANTENNAGATEAREA 2.529800 ;
    PORT
      LAYER Metal3 ;
        RECT 0.000 423.160 0.400 423.560 ;
    END
  END Tile_X0Y0_FrameData[27]
  PIN Tile_X0Y0_FrameData[28]
    DIRECTION INPUT ;
    USE SIGNAL ;
    ANTENNAGATEAREA 2.529800 ;
    PORT
      LAYER Metal3 ;
        RECT 0.000 424.840 0.400 425.240 ;
    END
  END Tile_X0Y0_FrameData[28]
  PIN Tile_X0Y0_FrameData[29]
    DIRECTION INPUT ;
    USE SIGNAL ;
    ANTENNAGATEAREA 2.529800 ;
    PORT
      LAYER Metal3 ;
        RECT 0.000 426.520 0.400 426.920 ;
    END
  END Tile_X0Y0_FrameData[29]
  PIN Tile_X0Y0_FrameData[2]
    DIRECTION INPUT ;
    USE SIGNAL ;
    ANTENNAGATEAREA 2.349100 ;
    PORT
      LAYER Metal3 ;
        RECT 0.000 381.160 0.400 381.560 ;
    END
  END Tile_X0Y0_FrameData[2]
  PIN Tile_X0Y0_FrameData[30]
    DIRECTION INPUT ;
    USE SIGNAL ;
    ANTENNAGATEAREA 2.529800 ;
    PORT
      LAYER Metal3 ;
        RECT 0.000 428.200 0.400 428.600 ;
    END
  END Tile_X0Y0_FrameData[30]
  PIN Tile_X0Y0_FrameData[31]
    DIRECTION INPUT ;
    USE SIGNAL ;
    ANTENNAGATEAREA 2.529800 ;
    PORT
      LAYER Metal3 ;
        RECT 0.000 429.880 0.400 430.280 ;
    END
  END Tile_X0Y0_FrameData[31]
  PIN Tile_X0Y0_FrameData[3]
    DIRECTION INPUT ;
    USE SIGNAL ;
    ANTENNAGATEAREA 2.349100 ;
    PORT
      LAYER Metal3 ;
        RECT 0.000 382.840 0.400 383.240 ;
    END
  END Tile_X0Y0_FrameData[3]
  PIN Tile_X0Y0_FrameData[4]
    DIRECTION INPUT ;
    USE SIGNAL ;
    ANTENNAGATEAREA 2.349100 ;
    PORT
      LAYER Metal3 ;
        RECT 0.000 384.520 0.400 384.920 ;
    END
  END Tile_X0Y0_FrameData[4]
  PIN Tile_X0Y0_FrameData[5]
    DIRECTION INPUT ;
    USE SIGNAL ;
    ANTENNAGATEAREA 2.349100 ;
    PORT
      LAYER Metal3 ;
        RECT 0.000 386.200 0.400 386.600 ;
    END
  END Tile_X0Y0_FrameData[5]
  PIN Tile_X0Y0_FrameData[6]
    DIRECTION INPUT ;
    USE SIGNAL ;
    ANTENNAGATEAREA 2.349100 ;
    PORT
      LAYER Metal3 ;
        RECT 0.000 387.880 0.400 388.280 ;
    END
  END Tile_X0Y0_FrameData[6]
  PIN Tile_X0Y0_FrameData[7]
    DIRECTION INPUT ;
    USE SIGNAL ;
    ANTENNAGATEAREA 2.349100 ;
    PORT
      LAYER Metal3 ;
        RECT 0.000 389.560 0.400 389.960 ;
    END
  END Tile_X0Y0_FrameData[7]
  PIN Tile_X0Y0_FrameData[8]
    DIRECTION INPUT ;
    USE SIGNAL ;
    ANTENNAGATEAREA 2.349100 ;
    PORT
      LAYER Metal3 ;
        RECT 0.000 391.240 0.400 391.640 ;
    END
  END Tile_X0Y0_FrameData[8]
  PIN Tile_X0Y0_FrameData[9]
    DIRECTION INPUT ;
    USE SIGNAL ;
    ANTENNAGATEAREA 2.349100 ;
    PORT
      LAYER Metal3 ;
        RECT 0.000 392.920 0.400 393.320 ;
    END
  END Tile_X0Y0_FrameData[9]
  PIN Tile_X0Y0_FrameData_O[0]
    DIRECTION OUTPUT ;
    USE SIGNAL ;
    ANTENNADIFFAREA 2.724000 ;
    PORT
      LAYER Metal3 ;
        RECT 188.240 377.800 188.640 378.200 ;
    END
  END Tile_X0Y0_FrameData_O[0]
  PIN Tile_X0Y0_FrameData_O[10]
    DIRECTION OUTPUT ;
    USE SIGNAL ;
    ANTENNADIFFAREA 2.724000 ;
    PORT
      LAYER Metal3 ;
        RECT 188.240 394.600 188.640 395.000 ;
    END
  END Tile_X0Y0_FrameData_O[10]
  PIN Tile_X0Y0_FrameData_O[11]
    DIRECTION OUTPUT ;
    USE SIGNAL ;
    ANTENNADIFFAREA 2.724000 ;
    PORT
      LAYER Metal3 ;
        RECT 188.240 396.280 188.640 396.680 ;
    END
  END Tile_X0Y0_FrameData_O[11]
  PIN Tile_X0Y0_FrameData_O[12]
    DIRECTION OUTPUT ;
    USE SIGNAL ;
    ANTENNADIFFAREA 2.724000 ;
    PORT
      LAYER Metal3 ;
        RECT 188.240 397.960 188.640 398.360 ;
    END
  END Tile_X0Y0_FrameData_O[12]
  PIN Tile_X0Y0_FrameData_O[13]
    DIRECTION OUTPUT ;
    USE SIGNAL ;
    ANTENNADIFFAREA 2.724000 ;
    PORT
      LAYER Metal3 ;
        RECT 188.240 399.640 188.640 400.040 ;
    END
  END Tile_X0Y0_FrameData_O[13]
  PIN Tile_X0Y0_FrameData_O[14]
    DIRECTION OUTPUT ;
    USE SIGNAL ;
    ANTENNADIFFAREA 2.724000 ;
    PORT
      LAYER Metal3 ;
        RECT 188.240 401.320 188.640 401.720 ;
    END
  END Tile_X0Y0_FrameData_O[14]
  PIN Tile_X0Y0_FrameData_O[15]
    DIRECTION OUTPUT ;
    USE SIGNAL ;
    ANTENNADIFFAREA 2.724000 ;
    PORT
      LAYER Metal3 ;
        RECT 188.240 403.000 188.640 403.400 ;
    END
  END Tile_X0Y0_FrameData_O[15]
  PIN Tile_X0Y0_FrameData_O[16]
    DIRECTION OUTPUT ;
    USE SIGNAL ;
    ANTENNADIFFAREA 2.724000 ;
    PORT
      LAYER Metal3 ;
        RECT 188.240 404.680 188.640 405.080 ;
    END
  END Tile_X0Y0_FrameData_O[16]
  PIN Tile_X0Y0_FrameData_O[17]
    DIRECTION OUTPUT ;
    USE SIGNAL ;
    ANTENNADIFFAREA 2.724000 ;
    PORT
      LAYER Metal3 ;
        RECT 188.240 406.360 188.640 406.760 ;
    END
  END Tile_X0Y0_FrameData_O[17]
  PIN Tile_X0Y0_FrameData_O[18]
    DIRECTION OUTPUT ;
    USE SIGNAL ;
    ANTENNADIFFAREA 2.724000 ;
    PORT
      LAYER Metal3 ;
        RECT 188.240 408.040 188.640 408.440 ;
    END
  END Tile_X0Y0_FrameData_O[18]
  PIN Tile_X0Y0_FrameData_O[19]
    DIRECTION OUTPUT ;
    USE SIGNAL ;
    ANTENNADIFFAREA 2.724000 ;
    PORT
      LAYER Metal3 ;
        RECT 188.240 409.720 188.640 410.120 ;
    END
  END Tile_X0Y0_FrameData_O[19]
  PIN Tile_X0Y0_FrameData_O[1]
    DIRECTION OUTPUT ;
    USE SIGNAL ;
    ANTENNADIFFAREA 2.724000 ;
    PORT
      LAYER Metal3 ;
        RECT 188.240 379.480 188.640 379.880 ;
    END
  END Tile_X0Y0_FrameData_O[1]
  PIN Tile_X0Y0_FrameData_O[20]
    DIRECTION OUTPUT ;
    USE SIGNAL ;
    ANTENNADIFFAREA 2.724000 ;
    PORT
      LAYER Metal3 ;
        RECT 188.240 411.400 188.640 411.800 ;
    END
  END Tile_X0Y0_FrameData_O[20]
  PIN Tile_X0Y0_FrameData_O[21]
    DIRECTION OUTPUT ;
    USE SIGNAL ;
    ANTENNADIFFAREA 2.724000 ;
    PORT
      LAYER Metal3 ;
        RECT 188.240 413.080 188.640 413.480 ;
    END
  END Tile_X0Y0_FrameData_O[21]
  PIN Tile_X0Y0_FrameData_O[22]
    DIRECTION OUTPUT ;
    USE SIGNAL ;
    ANTENNADIFFAREA 2.724000 ;
    PORT
      LAYER Metal3 ;
        RECT 188.240 414.760 188.640 415.160 ;
    END
  END Tile_X0Y0_FrameData_O[22]
  PIN Tile_X0Y0_FrameData_O[23]
    DIRECTION OUTPUT ;
    USE SIGNAL ;
    ANTENNADIFFAREA 2.724000 ;
    PORT
      LAYER Metal3 ;
        RECT 188.240 416.440 188.640 416.840 ;
    END
  END Tile_X0Y0_FrameData_O[23]
  PIN Tile_X0Y0_FrameData_O[24]
    DIRECTION OUTPUT ;
    USE SIGNAL ;
    ANTENNADIFFAREA 2.724000 ;
    PORT
      LAYER Metal3 ;
        RECT 188.240 418.120 188.640 418.520 ;
    END
  END Tile_X0Y0_FrameData_O[24]
  PIN Tile_X0Y0_FrameData_O[25]
    DIRECTION OUTPUT ;
    USE SIGNAL ;
    ANTENNADIFFAREA 2.724000 ;
    PORT
      LAYER Metal3 ;
        RECT 188.240 419.800 188.640 420.200 ;
    END
  END Tile_X0Y0_FrameData_O[25]
  PIN Tile_X0Y0_FrameData_O[26]
    DIRECTION OUTPUT ;
    USE SIGNAL ;
    ANTENNADIFFAREA 2.724000 ;
    PORT
      LAYER Metal3 ;
        RECT 188.240 421.480 188.640 421.880 ;
    END
  END Tile_X0Y0_FrameData_O[26]
  PIN Tile_X0Y0_FrameData_O[27]
    DIRECTION OUTPUT ;
    USE SIGNAL ;
    ANTENNADIFFAREA 2.724000 ;
    PORT
      LAYER Metal3 ;
        RECT 188.240 423.160 188.640 423.560 ;
    END
  END Tile_X0Y0_FrameData_O[27]
  PIN Tile_X0Y0_FrameData_O[28]
    DIRECTION OUTPUT ;
    USE SIGNAL ;
    ANTENNADIFFAREA 2.724000 ;
    PORT
      LAYER Metal3 ;
        RECT 188.240 424.840 188.640 425.240 ;
    END
  END Tile_X0Y0_FrameData_O[28]
  PIN Tile_X0Y0_FrameData_O[29]
    DIRECTION OUTPUT ;
    USE SIGNAL ;
    ANTENNADIFFAREA 2.724000 ;
    PORT
      LAYER Metal3 ;
        RECT 188.240 426.520 188.640 426.920 ;
    END
  END Tile_X0Y0_FrameData_O[29]
  PIN Tile_X0Y0_FrameData_O[2]
    DIRECTION OUTPUT ;
    USE SIGNAL ;
    ANTENNADIFFAREA 2.724000 ;
    PORT
      LAYER Metal3 ;
        RECT 188.240 381.160 188.640 381.560 ;
    END
  END Tile_X0Y0_FrameData_O[2]
  PIN Tile_X0Y0_FrameData_O[30]
    DIRECTION OUTPUT ;
    USE SIGNAL ;
    ANTENNADIFFAREA 2.724000 ;
    PORT
      LAYER Metal3 ;
        RECT 188.240 428.200 188.640 428.600 ;
    END
  END Tile_X0Y0_FrameData_O[30]
  PIN Tile_X0Y0_FrameData_O[31]
    DIRECTION OUTPUT ;
    USE SIGNAL ;
    ANTENNADIFFAREA 2.724000 ;
    PORT
      LAYER Metal3 ;
        RECT 188.240 429.880 188.640 430.280 ;
    END
  END Tile_X0Y0_FrameData_O[31]
  PIN Tile_X0Y0_FrameData_O[3]
    DIRECTION OUTPUT ;
    USE SIGNAL ;
    ANTENNADIFFAREA 2.724000 ;
    PORT
      LAYER Metal3 ;
        RECT 188.240 382.840 188.640 383.240 ;
    END
  END Tile_X0Y0_FrameData_O[3]
  PIN Tile_X0Y0_FrameData_O[4]
    DIRECTION OUTPUT ;
    USE SIGNAL ;
    ANTENNADIFFAREA 2.724000 ;
    PORT
      LAYER Metal3 ;
        RECT 188.240 384.520 188.640 384.920 ;
    END
  END Tile_X0Y0_FrameData_O[4]
  PIN Tile_X0Y0_FrameData_O[5]
    DIRECTION OUTPUT ;
    USE SIGNAL ;
    ANTENNADIFFAREA 2.724000 ;
    PORT
      LAYER Metal3 ;
        RECT 188.240 386.200 188.640 386.600 ;
    END
  END Tile_X0Y0_FrameData_O[5]
  PIN Tile_X0Y0_FrameData_O[6]
    DIRECTION OUTPUT ;
    USE SIGNAL ;
    ANTENNADIFFAREA 2.724000 ;
    PORT
      LAYER Metal3 ;
        RECT 188.240 387.880 188.640 388.280 ;
    END
  END Tile_X0Y0_FrameData_O[6]
  PIN Tile_X0Y0_FrameData_O[7]
    DIRECTION OUTPUT ;
    USE SIGNAL ;
    ANTENNADIFFAREA 2.724000 ;
    PORT
      LAYER Metal3 ;
        RECT 188.240 389.560 188.640 389.960 ;
    END
  END Tile_X0Y0_FrameData_O[7]
  PIN Tile_X0Y0_FrameData_O[8]
    DIRECTION OUTPUT ;
    USE SIGNAL ;
    ANTENNADIFFAREA 2.724000 ;
    PORT
      LAYER Metal3 ;
        RECT 188.240 391.240 188.640 391.640 ;
    END
  END Tile_X0Y0_FrameData_O[8]
  PIN Tile_X0Y0_FrameData_O[9]
    DIRECTION OUTPUT ;
    USE SIGNAL ;
    ANTENNADIFFAREA 2.724000 ;
    PORT
      LAYER Metal3 ;
        RECT 188.240 392.920 188.640 393.320 ;
    END
  END Tile_X0Y0_FrameData_O[9]
  PIN Tile_X0Y0_FrameStrobe_O[0]
    DIRECTION OUTPUT ;
    USE SIGNAL ;
    ANTENNADIFFAREA 2.724000 ;
    PORT
      LAYER Metal2 ;
        RECT 164.440 430.520 164.840 430.920 ;
    END
  END Tile_X0Y0_FrameStrobe_O[0]
  PIN Tile_X0Y0_FrameStrobe_O[10]
    DIRECTION OUTPUT ;
    USE SIGNAL ;
    ANTENNADIFFAREA 2.724000 ;
    PORT
      LAYER Metal2 ;
        RECT 174.040 430.520 174.440 430.920 ;
    END
  END Tile_X0Y0_FrameStrobe_O[10]
  PIN Tile_X0Y0_FrameStrobe_O[11]
    DIRECTION OUTPUT ;
    USE SIGNAL ;
    ANTENNADIFFAREA 2.724000 ;
    PORT
      LAYER Metal2 ;
        RECT 175.000 430.520 175.400 430.920 ;
    END
  END Tile_X0Y0_FrameStrobe_O[11]
  PIN Tile_X0Y0_FrameStrobe_O[12]
    DIRECTION OUTPUT ;
    USE SIGNAL ;
    ANTENNADIFFAREA 2.724000 ;
    PORT
      LAYER Metal2 ;
        RECT 175.960 430.520 176.360 430.920 ;
    END
  END Tile_X0Y0_FrameStrobe_O[12]
  PIN Tile_X0Y0_FrameStrobe_O[13]
    DIRECTION OUTPUT ;
    USE SIGNAL ;
    ANTENNADIFFAREA 2.724000 ;
    PORT
      LAYER Metal2 ;
        RECT 176.920 430.520 177.320 430.920 ;
    END
  END Tile_X0Y0_FrameStrobe_O[13]
  PIN Tile_X0Y0_FrameStrobe_O[14]
    DIRECTION OUTPUT ;
    USE SIGNAL ;
    ANTENNADIFFAREA 2.724000 ;
    PORT
      LAYER Metal2 ;
        RECT 177.880 430.520 178.280 430.920 ;
    END
  END Tile_X0Y0_FrameStrobe_O[14]
  PIN Tile_X0Y0_FrameStrobe_O[15]
    DIRECTION OUTPUT ;
    USE SIGNAL ;
    ANTENNADIFFAREA 2.724000 ;
    PORT
      LAYER Metal2 ;
        RECT 178.840 430.520 179.240 430.920 ;
    END
  END Tile_X0Y0_FrameStrobe_O[15]
  PIN Tile_X0Y0_FrameStrobe_O[16]
    DIRECTION OUTPUT ;
    USE SIGNAL ;
    ANTENNADIFFAREA 2.724000 ;
    PORT
      LAYER Metal2 ;
        RECT 179.800 430.520 180.200 430.920 ;
    END
  END Tile_X0Y0_FrameStrobe_O[16]
  PIN Tile_X0Y0_FrameStrobe_O[17]
    DIRECTION OUTPUT ;
    USE SIGNAL ;
    ANTENNADIFFAREA 2.724000 ;
    PORT
      LAYER Metal2 ;
        RECT 180.760 430.520 181.160 430.920 ;
    END
  END Tile_X0Y0_FrameStrobe_O[17]
  PIN Tile_X0Y0_FrameStrobe_O[18]
    DIRECTION OUTPUT ;
    USE SIGNAL ;
    ANTENNADIFFAREA 2.724000 ;
    PORT
      LAYER Metal2 ;
        RECT 181.720 430.520 182.120 430.920 ;
    END
  END Tile_X0Y0_FrameStrobe_O[18]
  PIN Tile_X0Y0_FrameStrobe_O[19]
    DIRECTION OUTPUT ;
    USE SIGNAL ;
    ANTENNADIFFAREA 2.724000 ;
    PORT
      LAYER Metal2 ;
        RECT 182.680 430.520 183.080 430.920 ;
    END
  END Tile_X0Y0_FrameStrobe_O[19]
  PIN Tile_X0Y0_FrameStrobe_O[1]
    DIRECTION OUTPUT ;
    USE SIGNAL ;
    ANTENNADIFFAREA 2.724000 ;
    PORT
      LAYER Metal2 ;
        RECT 165.400 430.520 165.800 430.920 ;
    END
  END Tile_X0Y0_FrameStrobe_O[1]
  PIN Tile_X0Y0_FrameStrobe_O[2]
    DIRECTION OUTPUT ;
    USE SIGNAL ;
    ANTENNADIFFAREA 2.724000 ;
    PORT
      LAYER Metal2 ;
        RECT 166.360 430.520 166.760 430.920 ;
    END
  END Tile_X0Y0_FrameStrobe_O[2]
  PIN Tile_X0Y0_FrameStrobe_O[3]
    DIRECTION OUTPUT ;
    USE SIGNAL ;
    ANTENNADIFFAREA 2.724000 ;
    PORT
      LAYER Metal2 ;
        RECT 167.320 430.520 167.720 430.920 ;
    END
  END Tile_X0Y0_FrameStrobe_O[3]
  PIN Tile_X0Y0_FrameStrobe_O[4]
    DIRECTION OUTPUT ;
    USE SIGNAL ;
    ANTENNADIFFAREA 2.724000 ;
    PORT
      LAYER Metal2 ;
        RECT 168.280 430.520 168.680 430.920 ;
    END
  END Tile_X0Y0_FrameStrobe_O[4]
  PIN Tile_X0Y0_FrameStrobe_O[5]
    DIRECTION OUTPUT ;
    USE SIGNAL ;
    ANTENNADIFFAREA 2.724000 ;
    PORT
      LAYER Metal2 ;
        RECT 169.240 430.520 169.640 430.920 ;
    END
  END Tile_X0Y0_FrameStrobe_O[5]
  PIN Tile_X0Y0_FrameStrobe_O[6]
    DIRECTION OUTPUT ;
    USE SIGNAL ;
    ANTENNADIFFAREA 2.724000 ;
    PORT
      LAYER Metal2 ;
        RECT 170.200 430.520 170.600 430.920 ;
    END
  END Tile_X0Y0_FrameStrobe_O[6]
  PIN Tile_X0Y0_FrameStrobe_O[7]
    DIRECTION OUTPUT ;
    USE SIGNAL ;
    ANTENNADIFFAREA 2.724000 ;
    PORT
      LAYER Metal2 ;
        RECT 171.160 430.520 171.560 430.920 ;
    END
  END Tile_X0Y0_FrameStrobe_O[7]
  PIN Tile_X0Y0_FrameStrobe_O[8]
    DIRECTION OUTPUT ;
    USE SIGNAL ;
    ANTENNADIFFAREA 2.724000 ;
    PORT
      LAYER Metal2 ;
        RECT 172.120 430.520 172.520 430.920 ;
    END
  END Tile_X0Y0_FrameStrobe_O[8]
  PIN Tile_X0Y0_FrameStrobe_O[9]
    DIRECTION OUTPUT ;
    USE SIGNAL ;
    ANTENNADIFFAREA 2.724000 ;
    PORT
      LAYER Metal2 ;
        RECT 173.080 430.520 173.480 430.920 ;
    END
  END Tile_X0Y0_FrameStrobe_O[9]
  PIN Tile_X0Y0_N1BEG[0]
    DIRECTION OUTPUT ;
    USE SIGNAL ;
    ANTENNADIFFAREA 2.724000 ;
    PORT
      LAYER Metal2 ;
        RECT 2.200 430.520 2.600 430.920 ;
    END
  END Tile_X0Y0_N1BEG[0]
  PIN Tile_X0Y0_N1BEG[1]
    DIRECTION OUTPUT ;
    USE SIGNAL ;
    ANTENNADIFFAREA 2.724000 ;
    PORT
      LAYER Metal2 ;
        RECT 3.160 430.520 3.560 430.920 ;
    END
  END Tile_X0Y0_N1BEG[1]
  PIN Tile_X0Y0_N1BEG[2]
    DIRECTION OUTPUT ;
    USE SIGNAL ;
    ANTENNADIFFAREA 2.724000 ;
    PORT
      LAYER Metal2 ;
        RECT 4.120 430.520 4.520 430.920 ;
    END
  END Tile_X0Y0_N1BEG[2]
  PIN Tile_X0Y0_N1BEG[3]
    DIRECTION OUTPUT ;
    USE SIGNAL ;
    ANTENNADIFFAREA 2.724000 ;
    PORT
      LAYER Metal2 ;
        RECT 5.080 430.520 5.480 430.920 ;
    END
  END Tile_X0Y0_N1BEG[3]
  PIN Tile_X0Y0_N2BEG[0]
    DIRECTION OUTPUT ;
    USE SIGNAL ;
    ANTENNADIFFAREA 2.724000 ;
    PORT
      LAYER Metal2 ;
        RECT 8.920 430.520 9.320 430.920 ;
    END
  END Tile_X0Y0_N2BEG[0]
  PIN Tile_X0Y0_N2BEG[1]
    DIRECTION OUTPUT ;
    USE SIGNAL ;
    ANTENNADIFFAREA 2.724000 ;
    PORT
      LAYER Metal2 ;
        RECT 9.880 430.520 10.280 430.920 ;
    END
  END Tile_X0Y0_N2BEG[1]
  PIN Tile_X0Y0_N2BEG[2]
    DIRECTION OUTPUT ;
    USE SIGNAL ;
    ANTENNADIFFAREA 2.724000 ;
    PORT
      LAYER Metal2 ;
        RECT 10.840 430.520 11.240 430.920 ;
    END
  END Tile_X0Y0_N2BEG[2]
  PIN Tile_X0Y0_N2BEG[3]
    DIRECTION OUTPUT ;
    USE SIGNAL ;
    ANTENNADIFFAREA 2.724000 ;
    PORT
      LAYER Metal2 ;
        RECT 11.800 430.520 12.200 430.920 ;
    END
  END Tile_X0Y0_N2BEG[3]
  PIN Tile_X0Y0_N2BEG[4]
    DIRECTION OUTPUT ;
    USE SIGNAL ;
    ANTENNADIFFAREA 2.724000 ;
    PORT
      LAYER Metal2 ;
        RECT 12.760 430.520 13.160 430.920 ;
    END
  END Tile_X0Y0_N2BEG[4]
  PIN Tile_X0Y0_N2BEG[5]
    DIRECTION OUTPUT ;
    USE SIGNAL ;
    ANTENNADIFFAREA 2.724000 ;
    PORT
      LAYER Metal2 ;
        RECT 13.720 430.520 14.120 430.920 ;
    END
  END Tile_X0Y0_N2BEG[5]
  PIN Tile_X0Y0_N2BEG[6]
    DIRECTION OUTPUT ;
    USE SIGNAL ;
    ANTENNADIFFAREA 2.724000 ;
    PORT
      LAYER Metal2 ;
        RECT 14.680 430.520 15.080 430.920 ;
    END
  END Tile_X0Y0_N2BEG[6]
  PIN Tile_X0Y0_N2BEG[7]
    DIRECTION OUTPUT ;
    USE SIGNAL ;
    ANTENNADIFFAREA 2.724000 ;
    PORT
      LAYER Metal2 ;
        RECT 15.640 430.520 16.040 430.920 ;
    END
  END Tile_X0Y0_N2BEG[7]
  PIN Tile_X0Y0_N2BEGb[0]
    DIRECTION OUTPUT ;
    USE SIGNAL ;
    ANTENNADIFFAREA 2.724000 ;
    PORT
      LAYER Metal2 ;
        RECT 21.400 430.520 21.800 430.920 ;
    END
  END Tile_X0Y0_N2BEGb[0]
  PIN Tile_X0Y0_N2BEGb[1]
    DIRECTION OUTPUT ;
    USE SIGNAL ;
    ANTENNADIFFAREA 2.724000 ;
    PORT
      LAYER Metal2 ;
        RECT 22.360 430.520 22.760 430.920 ;
    END
  END Tile_X0Y0_N2BEGb[1]
  PIN Tile_X0Y0_N2BEGb[2]
    DIRECTION OUTPUT ;
    USE SIGNAL ;
    ANTENNADIFFAREA 2.724000 ;
    PORT
      LAYER Metal2 ;
        RECT 23.320 430.520 23.720 430.920 ;
    END
  END Tile_X0Y0_N2BEGb[2]
  PIN Tile_X0Y0_N2BEGb[3]
    DIRECTION OUTPUT ;
    USE SIGNAL ;
    ANTENNADIFFAREA 2.724000 ;
    PORT
      LAYER Metal2 ;
        RECT 24.280 430.520 24.680 430.920 ;
    END
  END Tile_X0Y0_N2BEGb[3]
  PIN Tile_X0Y0_N2BEGb[4]
    DIRECTION OUTPUT ;
    USE SIGNAL ;
    ANTENNADIFFAREA 2.724000 ;
    PORT
      LAYER Metal2 ;
        RECT 25.240 430.520 25.640 430.920 ;
    END
  END Tile_X0Y0_N2BEGb[4]
  PIN Tile_X0Y0_N2BEGb[5]
    DIRECTION OUTPUT ;
    USE SIGNAL ;
    ANTENNADIFFAREA 2.724000 ;
    PORT
      LAYER Metal2 ;
        RECT 26.200 430.520 26.600 430.920 ;
    END
  END Tile_X0Y0_N2BEGb[5]
  PIN Tile_X0Y0_N2BEGb[6]
    DIRECTION OUTPUT ;
    USE SIGNAL ;
    ANTENNADIFFAREA 2.724000 ;
    PORT
      LAYER Metal2 ;
        RECT 27.160 430.520 27.560 430.920 ;
    END
  END Tile_X0Y0_N2BEGb[6]
  PIN Tile_X0Y0_N2BEGb[7]
    DIRECTION OUTPUT ;
    USE SIGNAL ;
    ANTENNADIFFAREA 2.724000 ;
    PORT
      LAYER Metal2 ;
        RECT 28.120 430.520 28.520 430.920 ;
    END
  END Tile_X0Y0_N2BEGb[7]
  PIN Tile_X0Y0_N4BEG[0]
    DIRECTION OUTPUT ;
    USE SIGNAL ;
    ANTENNADIFFAREA 2.724000 ;
    PORT
      LAYER Metal2 ;
        RECT 34.840 430.520 35.240 430.920 ;
    END
  END Tile_X0Y0_N4BEG[0]
  PIN Tile_X0Y0_N4BEG[10]
    DIRECTION OUTPUT ;
    USE SIGNAL ;
    ANTENNADIFFAREA 2.724000 ;
    PORT
      LAYER Metal2 ;
        RECT 44.440 430.520 44.840 430.920 ;
    END
  END Tile_X0Y0_N4BEG[10]
  PIN Tile_X0Y0_N4BEG[11]
    DIRECTION OUTPUT ;
    USE SIGNAL ;
    ANTENNADIFFAREA 2.724000 ;
    PORT
      LAYER Metal2 ;
        RECT 45.400 430.520 45.800 430.920 ;
    END
  END Tile_X0Y0_N4BEG[11]
  PIN Tile_X0Y0_N4BEG[12]
    DIRECTION OUTPUT ;
    USE SIGNAL ;
    ANTENNADIFFAREA 2.724000 ;
    PORT
      LAYER Metal2 ;
        RECT 46.360 430.520 46.760 430.920 ;
    END
  END Tile_X0Y0_N4BEG[12]
  PIN Tile_X0Y0_N4BEG[13]
    DIRECTION OUTPUT ;
    USE SIGNAL ;
    ANTENNADIFFAREA 2.724000 ;
    PORT
      LAYER Metal2 ;
        RECT 47.320 430.520 47.720 430.920 ;
    END
  END Tile_X0Y0_N4BEG[13]
  PIN Tile_X0Y0_N4BEG[14]
    DIRECTION OUTPUT ;
    USE SIGNAL ;
    ANTENNADIFFAREA 2.724000 ;
    PORT
      LAYER Metal2 ;
        RECT 48.280 430.520 48.680 430.920 ;
    END
  END Tile_X0Y0_N4BEG[14]
  PIN Tile_X0Y0_N4BEG[15]
    DIRECTION OUTPUT ;
    USE SIGNAL ;
    ANTENNADIFFAREA 2.724000 ;
    PORT
      LAYER Metal2 ;
        RECT 49.240 430.520 49.640 430.920 ;
    END
  END Tile_X0Y0_N4BEG[15]
  PIN Tile_X0Y0_N4BEG[1]
    DIRECTION OUTPUT ;
    USE SIGNAL ;
    ANTENNADIFFAREA 2.724000 ;
    PORT
      LAYER Metal2 ;
        RECT 35.800 430.520 36.200 430.920 ;
    END
  END Tile_X0Y0_N4BEG[1]
  PIN Tile_X0Y0_N4BEG[2]
    DIRECTION OUTPUT ;
    USE SIGNAL ;
    ANTENNADIFFAREA 2.724000 ;
    PORT
      LAYER Metal2 ;
        RECT 36.760 430.520 37.160 430.920 ;
    END
  END Tile_X0Y0_N4BEG[2]
  PIN Tile_X0Y0_N4BEG[3]
    DIRECTION OUTPUT ;
    USE SIGNAL ;
    ANTENNADIFFAREA 2.724000 ;
    PORT
      LAYER Metal2 ;
        RECT 37.720 430.520 38.120 430.920 ;
    END
  END Tile_X0Y0_N4BEG[3]
  PIN Tile_X0Y0_N4BEG[4]
    DIRECTION OUTPUT ;
    USE SIGNAL ;
    ANTENNADIFFAREA 2.724000 ;
    PORT
      LAYER Metal2 ;
        RECT 38.680 430.520 39.080 430.920 ;
    END
  END Tile_X0Y0_N4BEG[4]
  PIN Tile_X0Y0_N4BEG[5]
    DIRECTION OUTPUT ;
    USE SIGNAL ;
    ANTENNADIFFAREA 2.724000 ;
    PORT
      LAYER Metal2 ;
        RECT 39.640 430.520 40.040 430.920 ;
    END
  END Tile_X0Y0_N4BEG[5]
  PIN Tile_X0Y0_N4BEG[6]
    DIRECTION OUTPUT ;
    USE SIGNAL ;
    ANTENNADIFFAREA 2.724000 ;
    PORT
      LAYER Metal2 ;
        RECT 40.600 430.520 41.000 430.920 ;
    END
  END Tile_X0Y0_N4BEG[6]
  PIN Tile_X0Y0_N4BEG[7]
    DIRECTION OUTPUT ;
    USE SIGNAL ;
    ANTENNADIFFAREA 2.724000 ;
    PORT
      LAYER Metal2 ;
        RECT 41.560 430.520 41.960 430.920 ;
    END
  END Tile_X0Y0_N4BEG[7]
  PIN Tile_X0Y0_N4BEG[8]
    DIRECTION OUTPUT ;
    USE SIGNAL ;
    ANTENNADIFFAREA 2.724000 ;
    PORT
      LAYER Metal2 ;
        RECT 42.520 430.520 42.920 430.920 ;
    END
  END Tile_X0Y0_N4BEG[8]
  PIN Tile_X0Y0_N4BEG[9]
    DIRECTION OUTPUT ;
    USE SIGNAL ;
    ANTENNADIFFAREA 2.724000 ;
    PORT
      LAYER Metal2 ;
        RECT 43.480 430.520 43.880 430.920 ;
    END
  END Tile_X0Y0_N4BEG[9]
  PIN Tile_X0Y0_NN4BEG[0]
    DIRECTION OUTPUT ;
    USE SIGNAL ;
    ANTENNADIFFAREA 2.724000 ;
    PORT
      LAYER Metal2 ;
        RECT 58.840 430.520 59.240 430.920 ;
    END
  END Tile_X0Y0_NN4BEG[0]
  PIN Tile_X0Y0_NN4BEG[10]
    DIRECTION OUTPUT ;
    USE SIGNAL ;
    ANTENNADIFFAREA 2.724000 ;
    PORT
      LAYER Metal2 ;
        RECT 68.440 430.520 68.840 430.920 ;
    END
  END Tile_X0Y0_NN4BEG[10]
  PIN Tile_X0Y0_NN4BEG[11]
    DIRECTION OUTPUT ;
    USE SIGNAL ;
    ANTENNADIFFAREA 2.724000 ;
    PORT
      LAYER Metal2 ;
        RECT 69.400 430.520 69.800 430.920 ;
    END
  END Tile_X0Y0_NN4BEG[11]
  PIN Tile_X0Y0_NN4BEG[12]
    DIRECTION OUTPUT ;
    USE SIGNAL ;
    ANTENNADIFFAREA 2.724000 ;
    PORT
      LAYER Metal2 ;
        RECT 70.360 430.520 70.760 430.920 ;
    END
  END Tile_X0Y0_NN4BEG[12]
  PIN Tile_X0Y0_NN4BEG[13]
    DIRECTION OUTPUT ;
    USE SIGNAL ;
    ANTENNADIFFAREA 2.724000 ;
    PORT
      LAYER Metal2 ;
        RECT 71.320 430.520 71.720 430.920 ;
    END
  END Tile_X0Y0_NN4BEG[13]
  PIN Tile_X0Y0_NN4BEG[14]
    DIRECTION OUTPUT ;
    USE SIGNAL ;
    ANTENNADIFFAREA 2.724000 ;
    PORT
      LAYER Metal2 ;
        RECT 72.280 430.520 72.680 430.920 ;
    END
  END Tile_X0Y0_NN4BEG[14]
  PIN Tile_X0Y0_NN4BEG[15]
    DIRECTION OUTPUT ;
    USE SIGNAL ;
    ANTENNADIFFAREA 2.724000 ;
    PORT
      LAYER Metal2 ;
        RECT 73.240 430.520 73.640 430.920 ;
    END
  END Tile_X0Y0_NN4BEG[15]
  PIN Tile_X0Y0_NN4BEG[1]
    DIRECTION OUTPUT ;
    USE SIGNAL ;
    ANTENNADIFFAREA 2.724000 ;
    PORT
      LAYER Metal2 ;
        RECT 59.800 430.520 60.200 430.920 ;
    END
  END Tile_X0Y0_NN4BEG[1]
  PIN Tile_X0Y0_NN4BEG[2]
    DIRECTION OUTPUT ;
    USE SIGNAL ;
    ANTENNADIFFAREA 2.724000 ;
    PORT
      LAYER Metal2 ;
        RECT 60.760 430.520 61.160 430.920 ;
    END
  END Tile_X0Y0_NN4BEG[2]
  PIN Tile_X0Y0_NN4BEG[3]
    DIRECTION OUTPUT ;
    USE SIGNAL ;
    ANTENNADIFFAREA 2.724000 ;
    PORT
      LAYER Metal2 ;
        RECT 61.720 430.520 62.120 430.920 ;
    END
  END Tile_X0Y0_NN4BEG[3]
  PIN Tile_X0Y0_NN4BEG[4]
    DIRECTION OUTPUT ;
    USE SIGNAL ;
    ANTENNADIFFAREA 2.724000 ;
    PORT
      LAYER Metal2 ;
        RECT 62.680 430.520 63.080 430.920 ;
    END
  END Tile_X0Y0_NN4BEG[4]
  PIN Tile_X0Y0_NN4BEG[5]
    DIRECTION OUTPUT ;
    USE SIGNAL ;
    ANTENNADIFFAREA 2.724000 ;
    PORT
      LAYER Metal2 ;
        RECT 63.640 430.520 64.040 430.920 ;
    END
  END Tile_X0Y0_NN4BEG[5]
  PIN Tile_X0Y0_NN4BEG[6]
    DIRECTION OUTPUT ;
    USE SIGNAL ;
    ANTENNADIFFAREA 2.724000 ;
    PORT
      LAYER Metal2 ;
        RECT 64.600 430.520 65.000 430.920 ;
    END
  END Tile_X0Y0_NN4BEG[6]
  PIN Tile_X0Y0_NN4BEG[7]
    DIRECTION OUTPUT ;
    USE SIGNAL ;
    ANTENNADIFFAREA 2.724000 ;
    PORT
      LAYER Metal2 ;
        RECT 65.560 430.520 65.960 430.920 ;
    END
  END Tile_X0Y0_NN4BEG[7]
  PIN Tile_X0Y0_NN4BEG[8]
    DIRECTION OUTPUT ;
    USE SIGNAL ;
    ANTENNADIFFAREA 2.724000 ;
    PORT
      LAYER Metal2 ;
        RECT 66.520 430.520 66.920 430.920 ;
    END
  END Tile_X0Y0_NN4BEG[8]
  PIN Tile_X0Y0_NN4BEG[9]
    DIRECTION OUTPUT ;
    USE SIGNAL ;
    ANTENNADIFFAREA 2.724000 ;
    PORT
      LAYER Metal2 ;
        RECT 67.480 430.520 67.880 430.920 ;
    END
  END Tile_X0Y0_NN4BEG[9]
  PIN Tile_X0Y0_S1END[0]
    DIRECTION INPUT ;
    USE SIGNAL ;
    ANTENNAGATEAREA 1.571000 ;
    PORT
      LAYER Metal2 ;
        RECT 79.960 430.520 80.360 430.920 ;
    END
  END Tile_X0Y0_S1END[0]
  PIN Tile_X0Y0_S1END[1]
    DIRECTION INPUT ;
    USE SIGNAL ;
    ANTENNAGATEAREA 1.968800 ;
    PORT
      LAYER Metal2 ;
        RECT 80.920 430.520 81.320 430.920 ;
    END
  END Tile_X0Y0_S1END[1]
  PIN Tile_X0Y0_S1END[2]
    DIRECTION INPUT ;
    USE SIGNAL ;
    ANTENNAGATEAREA 1.578200 ;
    PORT
      LAYER Metal2 ;
        RECT 81.880 430.520 82.280 430.920 ;
    END
  END Tile_X0Y0_S1END[2]
  PIN Tile_X0Y0_S1END[3]
    DIRECTION INPUT ;
    USE SIGNAL ;
    ANTENNAGATEAREA 1.521000 ;
    PORT
      LAYER Metal2 ;
        RECT 82.840 430.520 83.240 430.920 ;
    END
  END Tile_X0Y0_S1END[3]
  PIN Tile_X0Y0_S2END[0]
    DIRECTION INPUT ;
    USE SIGNAL ;
    ANTENNAGATEAREA 1.160400 ;
    PORT
      LAYER Metal2 ;
        RECT 99.160 430.520 99.560 430.920 ;
    END
  END Tile_X0Y0_S2END[0]
  PIN Tile_X0Y0_S2END[1]
    DIRECTION INPUT ;
    USE SIGNAL ;
    ANTENNAGATEAREA 1.292200 ;
    PORT
      LAYER Metal2 ;
        RECT 100.120 430.520 100.520 430.920 ;
    END
  END Tile_X0Y0_S2END[1]
  PIN Tile_X0Y0_S2END[2]
    DIRECTION INPUT ;
    USE SIGNAL ;
    ANTENNAGATEAREA 1.373600 ;
    PORT
      LAYER Metal2 ;
        RECT 101.080 430.520 101.480 430.920 ;
    END
  END Tile_X0Y0_S2END[2]
  PIN Tile_X0Y0_S2END[3]
    DIRECTION INPUT ;
    USE SIGNAL ;
    ANTENNAGATEAREA 1.373600 ;
    PORT
      LAYER Metal2 ;
        RECT 102.040 430.520 102.440 430.920 ;
    END
  END Tile_X0Y0_S2END[3]
  PIN Tile_X0Y0_S2END[4]
    DIRECTION INPUT ;
    USE SIGNAL ;
    ANTENNAGATEAREA 1.066000 ;
    PORT
      LAYER Metal2 ;
        RECT 103.000 430.520 103.400 430.920 ;
    END
  END Tile_X0Y0_S2END[4]
  PIN Tile_X0Y0_S2END[5]
    DIRECTION INPUT ;
    USE SIGNAL ;
    ANTENNAGATEAREA 1.013000 ;
    PORT
      LAYER Metal2 ;
        RECT 103.960 430.520 104.360 430.920 ;
    END
  END Tile_X0Y0_S2END[5]
  PIN Tile_X0Y0_S2END[6]
    DIRECTION INPUT ;
    USE SIGNAL ;
    ANTENNAGATEAREA 1.071200 ;
    PORT
      LAYER Metal2 ;
        RECT 104.920 430.520 105.320 430.920 ;
    END
  END Tile_X0Y0_S2END[6]
  PIN Tile_X0Y0_S2END[7]
    DIRECTION INPUT ;
    USE SIGNAL ;
    ANTENNAGATEAREA 1.305200 ;
    PORT
      LAYER Metal2 ;
        RECT 105.880 430.520 106.280 430.920 ;
    END
  END Tile_X0Y0_S2END[7]
  PIN Tile_X0Y0_S2MID[0]
    DIRECTION INPUT ;
    USE SIGNAL ;
    ANTENNAGATEAREA 1.800000 ;
    PORT
      LAYER Metal2 ;
        RECT 86.680 430.520 87.080 430.920 ;
    END
  END Tile_X0Y0_S2MID[0]
  PIN Tile_X0Y0_S2MID[1]
    DIRECTION INPUT ;
    USE SIGNAL ;
    ANTENNAGATEAREA 2.158000 ;
    PORT
      LAYER Metal2 ;
        RECT 87.640 430.520 88.040 430.920 ;
    END
  END Tile_X0Y0_S2MID[1]
  PIN Tile_X0Y0_S2MID[2]
    DIRECTION INPUT ;
    USE SIGNAL ;
    ANTENNAGATEAREA 1.734200 ;
    PORT
      LAYER Metal2 ;
        RECT 88.600 430.520 89.000 430.920 ;
    END
  END Tile_X0Y0_S2MID[2]
  PIN Tile_X0Y0_S2MID[3]
    DIRECTION INPUT ;
    USE SIGNAL ;
    ANTENNAGATEAREA 2.189200 ;
    PORT
      LAYER Metal2 ;
        RECT 89.560 430.520 89.960 430.920 ;
    END
  END Tile_X0Y0_S2MID[3]
  PIN Tile_X0Y0_S2MID[4]
    DIRECTION INPUT ;
    USE SIGNAL ;
    ANTENNAGATEAREA 1.501500 ;
    PORT
      LAYER Metal2 ;
        RECT 90.520 430.520 90.920 430.920 ;
    END
  END Tile_X0Y0_S2MID[4]
  PIN Tile_X0Y0_S2MID[5]
    DIRECTION INPUT ;
    USE SIGNAL ;
    ANTENNAGATEAREA 1.292000 ;
    PORT
      LAYER Metal2 ;
        RECT 91.480 430.520 91.880 430.920 ;
    END
  END Tile_X0Y0_S2MID[5]
  PIN Tile_X0Y0_S2MID[6]
    DIRECTION INPUT ;
    USE SIGNAL ;
    ANTENNAGATEAREA 1.809100 ;
    PORT
      LAYER Metal2 ;
        RECT 92.440 430.520 92.840 430.920 ;
    END
  END Tile_X0Y0_S2MID[6]
  PIN Tile_X0Y0_S2MID[7]
    DIRECTION INPUT ;
    USE SIGNAL ;
    ANTENNAGATEAREA 1.718400 ;
    PORT
      LAYER Metal2 ;
        RECT 93.400 430.520 93.800 430.920 ;
    END
  END Tile_X0Y0_S2MID[7]
  PIN Tile_X0Y0_S4END[0]
    DIRECTION INPUT ;
    USE SIGNAL ;
    ANTENNAGATEAREA 1.099300 ;
    PORT
      LAYER Metal2 ;
        RECT 113.560 430.520 113.960 430.920 ;
    END
  END Tile_X0Y0_S4END[0]
  PIN Tile_X0Y0_S4END[10]
    DIRECTION INPUT ;
    USE SIGNAL ;
    ANTENNAGATEAREA 0.180700 ;
    PORT
      LAYER Metal2 ;
        RECT 123.160 430.520 123.560 430.920 ;
    END
  END Tile_X0Y0_S4END[10]
  PIN Tile_X0Y0_S4END[11]
    DIRECTION INPUT ;
    USE SIGNAL ;
    ANTENNAGATEAREA 0.180700 ;
    PORT
      LAYER Metal2 ;
        RECT 124.120 430.520 124.520 430.920 ;
    END
  END Tile_X0Y0_S4END[11]
  PIN Tile_X0Y0_S4END[12]
    DIRECTION INPUT ;
    USE SIGNAL ;
    ANTENNAGATEAREA 0.180700 ;
    PORT
      LAYER Metal2 ;
        RECT 125.080 430.520 125.480 430.920 ;
    END
  END Tile_X0Y0_S4END[12]
  PIN Tile_X0Y0_S4END[13]
    DIRECTION INPUT ;
    USE SIGNAL ;
    ANTENNAGATEAREA 0.180700 ;
    PORT
      LAYER Metal2 ;
        RECT 126.040 430.520 126.440 430.920 ;
    END
  END Tile_X0Y0_S4END[13]
  PIN Tile_X0Y0_S4END[14]
    DIRECTION INPUT ;
    USE SIGNAL ;
    ANTENNAGATEAREA 0.180700 ;
    PORT
      LAYER Metal2 ;
        RECT 127.000 430.520 127.400 430.920 ;
    END
  END Tile_X0Y0_S4END[14]
  PIN Tile_X0Y0_S4END[15]
    DIRECTION INPUT ;
    USE SIGNAL ;
    ANTENNAGATEAREA 0.180700 ;
    PORT
      LAYER Metal2 ;
        RECT 127.960 430.520 128.360 430.920 ;
    END
  END Tile_X0Y0_S4END[15]
  PIN Tile_X0Y0_S4END[1]
    DIRECTION INPUT ;
    USE SIGNAL ;
    ANTENNAGATEAREA 1.046500 ;
    PORT
      LAYER Metal2 ;
        RECT 114.520 430.520 114.920 430.920 ;
    END
  END Tile_X0Y0_S4END[1]
  PIN Tile_X0Y0_S4END[2]
    DIRECTION INPUT ;
    USE SIGNAL ;
    ANTENNAGATEAREA 0.947200 ;
    PORT
      LAYER Metal2 ;
        RECT 115.480 430.520 115.880 430.920 ;
    END
  END Tile_X0Y0_S4END[2]
  PIN Tile_X0Y0_S4END[3]
    DIRECTION INPUT ;
    USE SIGNAL ;
    ANTENNAGATEAREA 1.173400 ;
    PORT
      LAYER Metal2 ;
        RECT 116.440 430.520 116.840 430.920 ;
    END
  END Tile_X0Y0_S4END[3]
  PIN Tile_X0Y0_S4END[4]
    DIRECTION INPUT ;
    USE SIGNAL ;
    ANTENNAGATEAREA 0.881400 ;
    ANTENNADIFFAREA 10.077000 ;
    PORT
      LAYER Metal2 ;
        RECT 117.400 430.520 117.800 430.920 ;
    END
  END Tile_X0Y0_S4END[4]
  PIN Tile_X0Y0_S4END[5]
    DIRECTION INPUT ;
    USE SIGNAL ;
    ANTENNAGATEAREA 1.120600 ;
    ANTENNADIFFAREA 30.230999 ;
    PORT
      LAYER Metal2 ;
        RECT 118.360 430.520 118.760 430.920 ;
    END
  END Tile_X0Y0_S4END[5]
  PIN Tile_X0Y0_S4END[6]
    DIRECTION INPUT ;
    USE SIGNAL ;
    ANTENNAGATEAREA 1.092000 ;
    PORT
      LAYER Metal2 ;
        RECT 119.320 430.520 119.720 430.920 ;
    END
  END Tile_X0Y0_S4END[6]
  PIN Tile_X0Y0_S4END[7]
    DIRECTION INPUT ;
    USE SIGNAL ;
    ANTENNAGATEAREA 1.131800 ;
    PORT
      LAYER Metal2 ;
        RECT 120.280 430.520 120.680 430.920 ;
    END
  END Tile_X0Y0_S4END[7]
  PIN Tile_X0Y0_S4END[8]
    DIRECTION INPUT ;
    USE SIGNAL ;
    ANTENNAGATEAREA 0.180700 ;
    PORT
      LAYER Metal2 ;
        RECT 121.240 430.520 121.640 430.920 ;
    END
  END Tile_X0Y0_S4END[8]
  PIN Tile_X0Y0_S4END[9]
    DIRECTION INPUT ;
    USE SIGNAL ;
    ANTENNAGATEAREA 0.180700 ;
    PORT
      LAYER Metal2 ;
        RECT 122.200 430.520 122.600 430.920 ;
    END
  END Tile_X0Y0_S4END[9]
  PIN Tile_X0Y0_SS4END[0]
    DIRECTION INPUT ;
    USE SIGNAL ;
    ANTENNAGATEAREA 0.681200 ;
    PORT
      LAYER Metal2 ;
        RECT 138.520 430.520 138.920 430.920 ;
    END
  END Tile_X0Y0_SS4END[0]
  PIN Tile_X0Y0_SS4END[10]
    DIRECTION INPUT ;
    USE SIGNAL ;
    ANTENNAGATEAREA 0.180700 ;
    PORT
      LAYER Metal2 ;
        RECT 148.120 430.520 148.520 430.920 ;
    END
  END Tile_X0Y0_SS4END[10]
  PIN Tile_X0Y0_SS4END[11]
    DIRECTION INPUT ;
    USE SIGNAL ;
    ANTENNAGATEAREA 0.180700 ;
    PORT
      LAYER Metal2 ;
        RECT 149.080 430.520 149.480 430.920 ;
    END
  END Tile_X0Y0_SS4END[11]
  PIN Tile_X0Y0_SS4END[12]
    DIRECTION INPUT ;
    USE SIGNAL ;
    ANTENNAGATEAREA 0.180700 ;
    PORT
      LAYER Metal2 ;
        RECT 150.040 430.520 150.440 430.920 ;
    END
  END Tile_X0Y0_SS4END[12]
  PIN Tile_X0Y0_SS4END[13]
    DIRECTION INPUT ;
    USE SIGNAL ;
    ANTENNAGATEAREA 0.180700 ;
    PORT
      LAYER Metal2 ;
        RECT 151.000 430.520 151.400 430.920 ;
    END
  END Tile_X0Y0_SS4END[13]
  PIN Tile_X0Y0_SS4END[14]
    DIRECTION INPUT ;
    USE SIGNAL ;
    ANTENNAGATEAREA 0.180700 ;
    PORT
      LAYER Metal2 ;
        RECT 151.960 430.520 152.360 430.920 ;
    END
  END Tile_X0Y0_SS4END[14]
  PIN Tile_X0Y0_SS4END[15]
    DIRECTION INPUT ;
    USE SIGNAL ;
    ANTENNAGATEAREA 0.180700 ;
    PORT
      LAYER Metal2 ;
        RECT 152.920 430.520 153.320 430.920 ;
    END
  END Tile_X0Y0_SS4END[15]
  PIN Tile_X0Y0_SS4END[1]
    DIRECTION INPUT ;
    USE SIGNAL ;
    ANTENNAGATEAREA 0.668200 ;
    PORT
      LAYER Metal2 ;
        RECT 139.480 430.520 139.880 430.920 ;
    END
  END Tile_X0Y0_SS4END[1]
  PIN Tile_X0Y0_SS4END[2]
    DIRECTION INPUT ;
    USE SIGNAL ;
    ANTENNAGATEAREA 0.668200 ;
    ANTENNADIFFAREA 12.092400 ;
    PORT
      LAYER Metal2 ;
        RECT 140.440 430.520 140.840 430.920 ;
    END
  END Tile_X0Y0_SS4END[2]
  PIN Tile_X0Y0_SS4END[3]
    DIRECTION INPUT ;
    USE SIGNAL ;
    ANTENNAGATEAREA 0.455000 ;
    ANTENNADIFFAREA 8.061600 ;
    PORT
      LAYER Metal2 ;
        RECT 141.400 430.520 141.800 430.920 ;
    END
  END Tile_X0Y0_SS4END[3]
  PIN Tile_X0Y0_SS4END[4]
    DIRECTION INPUT ;
    USE SIGNAL ;
    ANTENNAGATEAREA 0.734000 ;
    ANTENNADIFFAREA 8.061600 ;
    PORT
      LAYER Metal2 ;
        RECT 142.360 430.520 142.760 430.920 ;
    END
  END Tile_X0Y0_SS4END[4]
  PIN Tile_X0Y0_SS4END[5]
    DIRECTION INPUT ;
    USE SIGNAL ;
    ANTENNAGATEAREA 0.652600 ;
    ANTENNADIFFAREA 12.092400 ;
    PORT
      LAYER Metal2 ;
        RECT 143.320 430.520 143.720 430.920 ;
    END
  END Tile_X0Y0_SS4END[5]
  PIN Tile_X0Y0_SS4END[6]
    DIRECTION INPUT ;
    USE SIGNAL ;
    ANTENNAGATEAREA 0.681200 ;
    ANTENNADIFFAREA 8.061600 ;
    PORT
      LAYER Metal2 ;
        RECT 144.280 430.520 144.680 430.920 ;
    END
  END Tile_X0Y0_SS4END[6]
  PIN Tile_X0Y0_SS4END[7]
    DIRECTION INPUT ;
    USE SIGNAL ;
    ANTENNAGATEAREA 0.455000 ;
    PORT
      LAYER Metal2 ;
        RECT 145.240 430.520 145.640 430.920 ;
    END
  END Tile_X0Y0_SS4END[7]
  PIN Tile_X0Y0_SS4END[8]
    DIRECTION INPUT ;
    USE SIGNAL ;
    ANTENNAGATEAREA 0.180700 ;
    PORT
      LAYER Metal2 ;
        RECT 146.200 430.520 146.600 430.920 ;
    END
  END Tile_X0Y0_SS4END[8]
  PIN Tile_X0Y0_SS4END[9]
    DIRECTION INPUT ;
    USE SIGNAL ;
    ANTENNAGATEAREA 0.180700 ;
    PORT
      LAYER Metal2 ;
        RECT 147.160 430.520 147.560 430.920 ;
    END
  END Tile_X0Y0_SS4END[9]
  PIN Tile_X0Y0_UserCLK
    DIRECTION INPUT ;
    USE SIGNAL ;
    ANTENNAGATEAREA 0.180700 ;
    PORT
      LAYER Metal3 ;
        RECT 0.000 376.120 0.400 376.520 ;
    END
  END Tile_X0Y0_UserCLK
  PIN Tile_X0Y0_UserCLKo
    DIRECTION OUTPUT ;
    USE SIGNAL ;
    ANTENNADIFFAREA 2.724000 ;
    PORT
      LAYER Metal3 ;
        RECT 188.240 376.120 188.640 376.520 ;
    END
  END Tile_X0Y0_UserCLKo
  PIN Tile_X0Y0_W1BEG[0]
    DIRECTION OUTPUT ;
    USE SIGNAL ;
    ANTENNADIFFAREA 2.724000 ;
    PORT
      LAYER Metal3 ;
        RECT 0.000 295.480 0.400 295.880 ;
    END
  END Tile_X0Y0_W1BEG[0]
  PIN Tile_X0Y0_W1BEG[1]
    DIRECTION OUTPUT ;
    USE SIGNAL ;
    ANTENNADIFFAREA 2.724000 ;
    PORT
      LAYER Metal3 ;
        RECT 0.000 297.160 0.400 297.560 ;
    END
  END Tile_X0Y0_W1BEG[1]
  PIN Tile_X0Y0_W1BEG[2]
    DIRECTION OUTPUT ;
    USE SIGNAL ;
    ANTENNADIFFAREA 2.724000 ;
    PORT
      LAYER Metal3 ;
        RECT 0.000 298.840 0.400 299.240 ;
    END
  END Tile_X0Y0_W1BEG[2]
  PIN Tile_X0Y0_W1BEG[3]
    DIRECTION OUTPUT ;
    USE SIGNAL ;
    ANTENNADIFFAREA 2.724000 ;
    PORT
      LAYER Metal3 ;
        RECT 0.000 300.520 0.400 300.920 ;
    END
  END Tile_X0Y0_W1BEG[3]
  PIN Tile_X0Y0_W1END[0]
    DIRECTION INPUT ;
    USE SIGNAL ;
    ANTENNAGATEAREA 1.254800 ;
    PORT
      LAYER Metal3 ;
        RECT 188.240 295.480 188.640 295.880 ;
    END
  END Tile_X0Y0_W1END[0]
  PIN Tile_X0Y0_W1END[1]
    DIRECTION INPUT ;
    USE SIGNAL ;
    ANTENNAGATEAREA 1.891800 ;
    PORT
      LAYER Metal3 ;
        RECT 188.240 297.160 188.640 297.560 ;
    END
  END Tile_X0Y0_W1END[1]
  PIN Tile_X0Y0_W1END[2]
    DIRECTION INPUT ;
    USE SIGNAL ;
    ANTENNAGATEAREA 2.457000 ;
    PORT
      LAYER Metal3 ;
        RECT 188.240 298.840 188.640 299.240 ;
    END
  END Tile_X0Y0_W1END[2]
  PIN Tile_X0Y0_W1END[3]
    DIRECTION INPUT ;
    USE SIGNAL ;
    ANTENNAGATEAREA 2.275000 ;
    PORT
      LAYER Metal3 ;
        RECT 188.240 300.520 188.640 300.920 ;
    END
  END Tile_X0Y0_W1END[3]
  PIN Tile_X0Y0_W2BEG[0]
    DIRECTION OUTPUT ;
    USE SIGNAL ;
    ANTENNADIFFAREA 2.724000 ;
    PORT
      LAYER Metal3 ;
        RECT 0.000 302.200 0.400 302.600 ;
    END
  END Tile_X0Y0_W2BEG[0]
  PIN Tile_X0Y0_W2BEG[1]
    DIRECTION OUTPUT ;
    USE SIGNAL ;
    ANTENNADIFFAREA 2.724000 ;
    PORT
      LAYER Metal3 ;
        RECT 0.000 303.880 0.400 304.280 ;
    END
  END Tile_X0Y0_W2BEG[1]
  PIN Tile_X0Y0_W2BEG[2]
    DIRECTION OUTPUT ;
    USE SIGNAL ;
    ANTENNADIFFAREA 2.724000 ;
    PORT
      LAYER Metal3 ;
        RECT 0.000 305.560 0.400 305.960 ;
    END
  END Tile_X0Y0_W2BEG[2]
  PIN Tile_X0Y0_W2BEG[3]
    DIRECTION OUTPUT ;
    USE SIGNAL ;
    ANTENNADIFFAREA 2.724000 ;
    PORT
      LAYER Metal3 ;
        RECT 0.000 307.240 0.400 307.640 ;
    END
  END Tile_X0Y0_W2BEG[3]
  PIN Tile_X0Y0_W2BEG[4]
    DIRECTION OUTPUT ;
    USE SIGNAL ;
    ANTENNADIFFAREA 2.724000 ;
    PORT
      LAYER Metal3 ;
        RECT 0.000 308.920 0.400 309.320 ;
    END
  END Tile_X0Y0_W2BEG[4]
  PIN Tile_X0Y0_W2BEG[5]
    DIRECTION OUTPUT ;
    USE SIGNAL ;
    ANTENNADIFFAREA 2.724000 ;
    PORT
      LAYER Metal3 ;
        RECT 0.000 310.600 0.400 311.000 ;
    END
  END Tile_X0Y0_W2BEG[5]
  PIN Tile_X0Y0_W2BEG[6]
    DIRECTION OUTPUT ;
    USE SIGNAL ;
    ANTENNADIFFAREA 2.724000 ;
    PORT
      LAYER Metal3 ;
        RECT 0.000 312.280 0.400 312.680 ;
    END
  END Tile_X0Y0_W2BEG[6]
  PIN Tile_X0Y0_W2BEG[7]
    DIRECTION OUTPUT ;
    USE SIGNAL ;
    ANTENNADIFFAREA 2.724000 ;
    PORT
      LAYER Metal3 ;
        RECT 0.000 313.960 0.400 314.360 ;
    END
  END Tile_X0Y0_W2BEG[7]
  PIN Tile_X0Y0_W2BEGb[0]
    DIRECTION OUTPUT ;
    USE SIGNAL ;
    ANTENNADIFFAREA 2.724000 ;
    PORT
      LAYER Metal3 ;
        RECT 0.000 315.640 0.400 316.040 ;
    END
  END Tile_X0Y0_W2BEGb[0]
  PIN Tile_X0Y0_W2BEGb[1]
    DIRECTION OUTPUT ;
    USE SIGNAL ;
    ANTENNADIFFAREA 2.724000 ;
    PORT
      LAYER Metal3 ;
        RECT 0.000 317.320 0.400 317.720 ;
    END
  END Tile_X0Y0_W2BEGb[1]
  PIN Tile_X0Y0_W2BEGb[2]
    DIRECTION OUTPUT ;
    USE SIGNAL ;
    ANTENNADIFFAREA 2.724000 ;
    PORT
      LAYER Metal3 ;
        RECT 0.000 319.000 0.400 319.400 ;
    END
  END Tile_X0Y0_W2BEGb[2]
  PIN Tile_X0Y0_W2BEGb[3]
    DIRECTION OUTPUT ;
    USE SIGNAL ;
    ANTENNADIFFAREA 2.724000 ;
    PORT
      LAYER Metal3 ;
        RECT 0.000 320.680 0.400 321.080 ;
    END
  END Tile_X0Y0_W2BEGb[3]
  PIN Tile_X0Y0_W2BEGb[4]
    DIRECTION OUTPUT ;
    USE SIGNAL ;
    ANTENNADIFFAREA 2.724000 ;
    PORT
      LAYER Metal3 ;
        RECT 0.000 322.360 0.400 322.760 ;
    END
  END Tile_X0Y0_W2BEGb[4]
  PIN Tile_X0Y0_W2BEGb[5]
    DIRECTION OUTPUT ;
    USE SIGNAL ;
    ANTENNADIFFAREA 2.724000 ;
    PORT
      LAYER Metal3 ;
        RECT 0.000 324.040 0.400 324.440 ;
    END
  END Tile_X0Y0_W2BEGb[5]
  PIN Tile_X0Y0_W2BEGb[6]
    DIRECTION OUTPUT ;
    USE SIGNAL ;
    ANTENNADIFFAREA 2.724000 ;
    PORT
      LAYER Metal3 ;
        RECT 0.000 325.720 0.400 326.120 ;
    END
  END Tile_X0Y0_W2BEGb[6]
  PIN Tile_X0Y0_W2BEGb[7]
    DIRECTION OUTPUT ;
    USE SIGNAL ;
    ANTENNADIFFAREA 2.724000 ;
    PORT
      LAYER Metal3 ;
        RECT 0.000 327.400 0.400 327.800 ;
    END
  END Tile_X0Y0_W2BEGb[7]
  PIN Tile_X0Y0_W2END[0]
    DIRECTION INPUT ;
    USE SIGNAL ;
    ANTENNAGATEAREA 0.914700 ;
    PORT
      LAYER Metal3 ;
        RECT 188.240 315.640 188.640 316.040 ;
    END
  END Tile_X0Y0_W2END[0]
  PIN Tile_X0Y0_W2END[1]
    DIRECTION INPUT ;
    USE SIGNAL ;
    ANTENNAGATEAREA 1.358000 ;
    PORT
      LAYER Metal3 ;
        RECT 188.240 317.320 188.640 317.720 ;
    END
  END Tile_X0Y0_W2END[1]
  PIN Tile_X0Y0_W2END[2]
    DIRECTION INPUT ;
    USE SIGNAL ;
    ANTENNAGATEAREA 1.449800 ;
    PORT
      LAYER Metal3 ;
        RECT 188.240 319.000 188.640 319.400 ;
    END
  END Tile_X0Y0_W2END[2]
  PIN Tile_X0Y0_W2END[3]
    DIRECTION INPUT ;
    USE SIGNAL ;
    ANTENNAGATEAREA 1.646100 ;
    PORT
      LAYER Metal3 ;
        RECT 188.240 320.680 188.640 321.080 ;
    END
  END Tile_X0Y0_W2END[3]
  PIN Tile_X0Y0_W2END[4]
    DIRECTION INPUT ;
    USE SIGNAL ;
    ANTENNAGATEAREA 1.780500 ;
    PORT
      LAYER Metal3 ;
        RECT 188.240 322.360 188.640 322.760 ;
    END
  END Tile_X0Y0_W2END[4]
  PIN Tile_X0Y0_W2END[5]
    DIRECTION INPUT ;
    USE SIGNAL ;
    ANTENNAGATEAREA 0.426400 ;
    PORT
      LAYER Metal3 ;
        RECT 188.240 324.040 188.640 324.440 ;
    END
  END Tile_X0Y0_W2END[5]
  PIN Tile_X0Y0_W2END[6]
    DIRECTION INPUT ;
    USE SIGNAL ;
    ANTENNAGATEAREA 0.426400 ;
    PORT
      LAYER Metal3 ;
        RECT 188.240 325.720 188.640 326.120 ;
    END
  END Tile_X0Y0_W2END[6]
  PIN Tile_X0Y0_W2END[7]
    DIRECTION INPUT ;
    USE SIGNAL ;
    ANTENNAGATEAREA 1.127900 ;
    ANTENNADIFFAREA 10.077000 ;
    PORT
      LAYER Metal3 ;
        RECT 188.240 327.400 188.640 327.800 ;
    END
  END Tile_X0Y0_W2END[7]
  PIN Tile_X0Y0_W2MID[0]
    DIRECTION INPUT ;
    USE SIGNAL ;
    ANTENNAGATEAREA 0.886100 ;
    PORT
      LAYER Metal3 ;
        RECT 188.240 302.200 188.640 302.600 ;
    END
  END Tile_X0Y0_W2MID[0]
  PIN Tile_X0Y0_W2MID[1]
    DIRECTION INPUT ;
    USE SIGNAL ;
    ANTENNAGATEAREA 1.046500 ;
    PORT
      LAYER Metal3 ;
        RECT 188.240 303.880 188.640 304.280 ;
    END
  END Tile_X0Y0_W2MID[1]
  PIN Tile_X0Y0_W2MID[2]
    DIRECTION INPUT ;
    USE SIGNAL ;
    ANTENNAGATEAREA 0.951900 ;
    PORT
      LAYER Metal3 ;
        RECT 188.240 305.560 188.640 305.960 ;
    END
  END Tile_X0Y0_W2MID[2]
  PIN Tile_X0Y0_W2MID[3]
    DIRECTION INPUT ;
    USE SIGNAL ;
    ANTENNAGATEAREA 1.090700 ;
    ANTENNADIFFAREA 12.092400 ;
    PORT
      LAYER Metal3 ;
        RECT 188.240 307.240 188.640 307.640 ;
    END
  END Tile_X0Y0_W2MID[3]
  PIN Tile_X0Y0_W2MID[4]
    DIRECTION INPUT ;
    USE SIGNAL ;
    ANTENNAGATEAREA 0.635700 ;
    ANTENNADIFFAREA 6.046200 ;
    PORT
      LAYER Metal3 ;
        RECT 188.240 308.920 188.640 309.320 ;
    END
  END Tile_X0Y0_W2MID[4]
  PIN Tile_X0Y0_W2MID[5]
    DIRECTION INPUT ;
    USE SIGNAL ;
    ANTENNAGATEAREA 0.664300 ;
    ANTENNADIFFAREA 6.046200 ;
    PORT
      LAYER Metal3 ;
        RECT 188.240 310.600 188.640 311.000 ;
    END
  END Tile_X0Y0_W2MID[5]
  PIN Tile_X0Y0_W2MID[6]
    DIRECTION INPUT ;
    USE SIGNAL ;
    ANTENNAGATEAREA 0.899100 ;
    PORT
      LAYER Metal3 ;
        RECT 188.240 312.280 188.640 312.680 ;
    END
  END Tile_X0Y0_W2MID[6]
  PIN Tile_X0Y0_W2MID[7]
    DIRECTION INPUT ;
    USE SIGNAL ;
    ANTENNAGATEAREA 0.422500 ;
    ANTENNADIFFAREA 8.061600 ;
    PORT
      LAYER Metal3 ;
        RECT 188.240 313.960 188.640 314.360 ;
    END
  END Tile_X0Y0_W2MID[7]
  PIN Tile_X0Y0_W6BEG[0]
    DIRECTION OUTPUT ;
    USE SIGNAL ;
    ANTENNADIFFAREA 2.724000 ;
    PORT
      LAYER Metal3 ;
        RECT 0.000 355.960 0.400 356.360 ;
    END
  END Tile_X0Y0_W6BEG[0]
  PIN Tile_X0Y0_W6BEG[10]
    DIRECTION OUTPUT ;
    USE SIGNAL ;
    ANTENNADIFFAREA 2.724000 ;
    PORT
      LAYER Metal3 ;
        RECT 0.000 372.760 0.400 373.160 ;
    END
  END Tile_X0Y0_W6BEG[10]
  PIN Tile_X0Y0_W6BEG[11]
    DIRECTION OUTPUT ;
    USE SIGNAL ;
    ANTENNADIFFAREA 2.724000 ;
    PORT
      LAYER Metal3 ;
        RECT 0.000 374.440 0.400 374.840 ;
    END
  END Tile_X0Y0_W6BEG[11]
  PIN Tile_X0Y0_W6BEG[1]
    DIRECTION OUTPUT ;
    USE SIGNAL ;
    ANTENNADIFFAREA 2.724000 ;
    PORT
      LAYER Metal3 ;
        RECT 0.000 357.640 0.400 358.040 ;
    END
  END Tile_X0Y0_W6BEG[1]
  PIN Tile_X0Y0_W6BEG[2]
    DIRECTION OUTPUT ;
    USE SIGNAL ;
    ANTENNADIFFAREA 2.724000 ;
    PORT
      LAYER Metal3 ;
        RECT 0.000 359.320 0.400 359.720 ;
    END
  END Tile_X0Y0_W6BEG[2]
  PIN Tile_X0Y0_W6BEG[3]
    DIRECTION OUTPUT ;
    USE SIGNAL ;
    ANTENNADIFFAREA 2.724000 ;
    PORT
      LAYER Metal3 ;
        RECT 0.000 361.000 0.400 361.400 ;
    END
  END Tile_X0Y0_W6BEG[3]
  PIN Tile_X0Y0_W6BEG[4]
    DIRECTION OUTPUT ;
    USE SIGNAL ;
    ANTENNADIFFAREA 2.724000 ;
    PORT
      LAYER Metal3 ;
        RECT 0.000 362.680 0.400 363.080 ;
    END
  END Tile_X0Y0_W6BEG[4]
  PIN Tile_X0Y0_W6BEG[5]
    DIRECTION OUTPUT ;
    USE SIGNAL ;
    ANTENNADIFFAREA 2.724000 ;
    PORT
      LAYER Metal3 ;
        RECT 0.000 364.360 0.400 364.760 ;
    END
  END Tile_X0Y0_W6BEG[5]
  PIN Tile_X0Y0_W6BEG[6]
    DIRECTION OUTPUT ;
    USE SIGNAL ;
    ANTENNADIFFAREA 2.724000 ;
    PORT
      LAYER Metal3 ;
        RECT 0.000 366.040 0.400 366.440 ;
    END
  END Tile_X0Y0_W6BEG[6]
  PIN Tile_X0Y0_W6BEG[7]
    DIRECTION OUTPUT ;
    USE SIGNAL ;
    ANTENNADIFFAREA 2.724000 ;
    PORT
      LAYER Metal3 ;
        RECT 0.000 367.720 0.400 368.120 ;
    END
  END Tile_X0Y0_W6BEG[7]
  PIN Tile_X0Y0_W6BEG[8]
    DIRECTION OUTPUT ;
    USE SIGNAL ;
    ANTENNADIFFAREA 2.724000 ;
    PORT
      LAYER Metal3 ;
        RECT 0.000 369.400 0.400 369.800 ;
    END
  END Tile_X0Y0_W6BEG[8]
  PIN Tile_X0Y0_W6BEG[9]
    DIRECTION OUTPUT ;
    USE SIGNAL ;
    ANTENNADIFFAREA 2.724000 ;
    PORT
      LAYER Metal3 ;
        RECT 0.000 371.080 0.400 371.480 ;
    END
  END Tile_X0Y0_W6BEG[9]
  PIN Tile_X0Y0_W6END[0]
    DIRECTION INPUT ;
    USE SIGNAL ;
    ANTENNAGATEAREA 1.826000 ;
    PORT
      LAYER Metal3 ;
        RECT 188.240 355.960 188.640 356.360 ;
    END
  END Tile_X0Y0_W6END[0]
  PIN Tile_X0Y0_W6END[10]
    DIRECTION INPUT ;
    USE SIGNAL ;
    ANTENNAGATEAREA 0.180700 ;
    PORT
      LAYER Metal3 ;
        RECT 188.240 372.760 188.640 373.160 ;
    END
  END Tile_X0Y0_W6END[10]
  PIN Tile_X0Y0_W6END[11]
    DIRECTION INPUT ;
    USE SIGNAL ;
    ANTENNAGATEAREA 0.180700 ;
    PORT
      LAYER Metal3 ;
        RECT 188.240 374.440 188.640 374.840 ;
    END
  END Tile_X0Y0_W6END[11]
  PIN Tile_X0Y0_W6END[1]
    DIRECTION INPUT ;
    USE SIGNAL ;
    ANTENNAGATEAREA 1.841600 ;
    PORT
      LAYER Metal3 ;
        RECT 188.240 357.640 188.640 358.040 ;
    END
  END Tile_X0Y0_W6END[1]
  PIN Tile_X0Y0_W6END[2]
    DIRECTION INPUT ;
    USE SIGNAL ;
    ANTENNAGATEAREA 0.180700 ;
    PORT
      LAYER Metal3 ;
        RECT 188.240 359.320 188.640 359.720 ;
    END
  END Tile_X0Y0_W6END[2]
  PIN Tile_X0Y0_W6END[3]
    DIRECTION INPUT ;
    USE SIGNAL ;
    ANTENNAGATEAREA 0.180700 ;
    PORT
      LAYER Metal3 ;
        RECT 188.240 361.000 188.640 361.400 ;
    END
  END Tile_X0Y0_W6END[3]
  PIN Tile_X0Y0_W6END[4]
    DIRECTION INPUT ;
    USE SIGNAL ;
    ANTENNAGATEAREA 0.180700 ;
    PORT
      LAYER Metal3 ;
        RECT 188.240 362.680 188.640 363.080 ;
    END
  END Tile_X0Y0_W6END[4]
  PIN Tile_X0Y0_W6END[5]
    DIRECTION INPUT ;
    USE SIGNAL ;
    ANTENNAGATEAREA 0.180700 ;
    PORT
      LAYER Metal3 ;
        RECT 188.240 364.360 188.640 364.760 ;
    END
  END Tile_X0Y0_W6END[5]
  PIN Tile_X0Y0_W6END[6]
    DIRECTION INPUT ;
    USE SIGNAL ;
    ANTENNAGATEAREA 0.180700 ;
    PORT
      LAYER Metal3 ;
        RECT 188.240 366.040 188.640 366.440 ;
    END
  END Tile_X0Y0_W6END[6]
  PIN Tile_X0Y0_W6END[7]
    DIRECTION INPUT ;
    USE SIGNAL ;
    ANTENNAGATEAREA 0.180700 ;
    PORT
      LAYER Metal3 ;
        RECT 188.240 367.720 188.640 368.120 ;
    END
  END Tile_X0Y0_W6END[7]
  PIN Tile_X0Y0_W6END[8]
    DIRECTION INPUT ;
    USE SIGNAL ;
    ANTENNAGATEAREA 0.180700 ;
    PORT
      LAYER Metal3 ;
        RECT 188.240 369.400 188.640 369.800 ;
    END
  END Tile_X0Y0_W6END[8]
  PIN Tile_X0Y0_W6END[9]
    DIRECTION INPUT ;
    USE SIGNAL ;
    ANTENNAGATEAREA 0.180700 ;
    PORT
      LAYER Metal3 ;
        RECT 188.240 371.080 188.640 371.480 ;
    END
  END Tile_X0Y0_W6END[9]
  PIN Tile_X0Y0_WW4BEG[0]
    DIRECTION OUTPUT ;
    USE SIGNAL ;
    ANTENNADIFFAREA 2.724000 ;
    PORT
      LAYER Metal3 ;
        RECT 0.000 329.080 0.400 329.480 ;
    END
  END Tile_X0Y0_WW4BEG[0]
  PIN Tile_X0Y0_WW4BEG[10]
    DIRECTION OUTPUT ;
    USE SIGNAL ;
    ANTENNADIFFAREA 2.724000 ;
    PORT
      LAYER Metal3 ;
        RECT 0.000 345.880 0.400 346.280 ;
    END
  END Tile_X0Y0_WW4BEG[10]
  PIN Tile_X0Y0_WW4BEG[11]
    DIRECTION OUTPUT ;
    USE SIGNAL ;
    ANTENNADIFFAREA 2.724000 ;
    PORT
      LAYER Metal3 ;
        RECT 0.000 347.560 0.400 347.960 ;
    END
  END Tile_X0Y0_WW4BEG[11]
  PIN Tile_X0Y0_WW4BEG[12]
    DIRECTION OUTPUT ;
    USE SIGNAL ;
    ANTENNADIFFAREA 2.724000 ;
    PORT
      LAYER Metal3 ;
        RECT 0.000 349.240 0.400 349.640 ;
    END
  END Tile_X0Y0_WW4BEG[12]
  PIN Tile_X0Y0_WW4BEG[13]
    DIRECTION OUTPUT ;
    USE SIGNAL ;
    ANTENNADIFFAREA 2.724000 ;
    PORT
      LAYER Metal3 ;
        RECT 0.000 350.920 0.400 351.320 ;
    END
  END Tile_X0Y0_WW4BEG[13]
  PIN Tile_X0Y0_WW4BEG[14]
    DIRECTION OUTPUT ;
    USE SIGNAL ;
    ANTENNADIFFAREA 2.724000 ;
    PORT
      LAYER Metal3 ;
        RECT 0.000 352.600 0.400 353.000 ;
    END
  END Tile_X0Y0_WW4BEG[14]
  PIN Tile_X0Y0_WW4BEG[15]
    DIRECTION OUTPUT ;
    USE SIGNAL ;
    ANTENNADIFFAREA 2.724000 ;
    PORT
      LAYER Metal3 ;
        RECT 0.000 354.280 0.400 354.680 ;
    END
  END Tile_X0Y0_WW4BEG[15]
  PIN Tile_X0Y0_WW4BEG[1]
    DIRECTION OUTPUT ;
    USE SIGNAL ;
    ANTENNADIFFAREA 2.724000 ;
    PORT
      LAYER Metal3 ;
        RECT 0.000 330.760 0.400 331.160 ;
    END
  END Tile_X0Y0_WW4BEG[1]
  PIN Tile_X0Y0_WW4BEG[2]
    DIRECTION OUTPUT ;
    USE SIGNAL ;
    ANTENNADIFFAREA 2.724000 ;
    PORT
      LAYER Metal3 ;
        RECT 0.000 332.440 0.400 332.840 ;
    END
  END Tile_X0Y0_WW4BEG[2]
  PIN Tile_X0Y0_WW4BEG[3]
    DIRECTION OUTPUT ;
    USE SIGNAL ;
    ANTENNADIFFAREA 2.724000 ;
    PORT
      LAYER Metal3 ;
        RECT 0.000 334.120 0.400 334.520 ;
    END
  END Tile_X0Y0_WW4BEG[3]
  PIN Tile_X0Y0_WW4BEG[4]
    DIRECTION OUTPUT ;
    USE SIGNAL ;
    ANTENNADIFFAREA 2.724000 ;
    PORT
      LAYER Metal3 ;
        RECT 0.000 335.800 0.400 336.200 ;
    END
  END Tile_X0Y0_WW4BEG[4]
  PIN Tile_X0Y0_WW4BEG[5]
    DIRECTION OUTPUT ;
    USE SIGNAL ;
    ANTENNADIFFAREA 2.724000 ;
    PORT
      LAYER Metal3 ;
        RECT 0.000 337.480 0.400 337.880 ;
    END
  END Tile_X0Y0_WW4BEG[5]
  PIN Tile_X0Y0_WW4BEG[6]
    DIRECTION OUTPUT ;
    USE SIGNAL ;
    ANTENNADIFFAREA 2.724000 ;
    PORT
      LAYER Metal3 ;
        RECT 0.000 339.160 0.400 339.560 ;
    END
  END Tile_X0Y0_WW4BEG[6]
  PIN Tile_X0Y0_WW4BEG[7]
    DIRECTION OUTPUT ;
    USE SIGNAL ;
    ANTENNADIFFAREA 2.724000 ;
    PORT
      LAYER Metal3 ;
        RECT 0.000 340.840 0.400 341.240 ;
    END
  END Tile_X0Y0_WW4BEG[7]
  PIN Tile_X0Y0_WW4BEG[8]
    DIRECTION OUTPUT ;
    USE SIGNAL ;
    ANTENNADIFFAREA 2.724000 ;
    PORT
      LAYER Metal3 ;
        RECT 0.000 342.520 0.400 342.920 ;
    END
  END Tile_X0Y0_WW4BEG[8]
  PIN Tile_X0Y0_WW4BEG[9]
    DIRECTION OUTPUT ;
    USE SIGNAL ;
    ANTENNADIFFAREA 2.724000 ;
    PORT
      LAYER Metal3 ;
        RECT 0.000 344.200 0.400 344.600 ;
    END
  END Tile_X0Y0_WW4BEG[9]
  PIN Tile_X0Y0_WW4END[0]
    DIRECTION INPUT ;
    USE SIGNAL ;
    ANTENNAGATEAREA 0.620100 ;
    ANTENNADIFFAREA 18.138599 ;
    PORT
      LAYER Metal3 ;
        RECT 188.240 329.080 188.640 329.480 ;
    END
  END Tile_X0Y0_WW4END[0]
  PIN Tile_X0Y0_WW4END[10]
    DIRECTION INPUT ;
    USE SIGNAL ;
    ANTENNAGATEAREA 0.180700 ;
    PORT
      LAYER Metal3 ;
        RECT 188.240 345.880 188.640 346.280 ;
    END
  END Tile_X0Y0_WW4END[10]
  PIN Tile_X0Y0_WW4END[11]
    DIRECTION INPUT ;
    USE SIGNAL ;
    ANTENNAGATEAREA 0.180700 ;
    PORT
      LAYER Metal3 ;
        RECT 188.240 347.560 188.640 347.960 ;
    END
  END Tile_X0Y0_WW4END[11]
  PIN Tile_X0Y0_WW4END[12]
    DIRECTION INPUT ;
    USE SIGNAL ;
    ANTENNAGATEAREA 0.180700 ;
    PORT
      LAYER Metal3 ;
        RECT 188.240 349.240 188.640 349.640 ;
    END
  END Tile_X0Y0_WW4END[12]
  PIN Tile_X0Y0_WW4END[13]
    DIRECTION INPUT ;
    USE SIGNAL ;
    ANTENNAGATEAREA 0.180700 ;
    PORT
      LAYER Metal3 ;
        RECT 188.240 350.920 188.640 351.320 ;
    END
  END Tile_X0Y0_WW4END[13]
  PIN Tile_X0Y0_WW4END[14]
    DIRECTION INPUT ;
    USE SIGNAL ;
    ANTENNAGATEAREA 0.180700 ;
    PORT
      LAYER Metal3 ;
        RECT 188.240 352.600 188.640 353.000 ;
    END
  END Tile_X0Y0_WW4END[14]
  PIN Tile_X0Y0_WW4END[15]
    DIRECTION INPUT ;
    USE SIGNAL ;
    ANTENNAGATEAREA 0.180700 ;
    PORT
      LAYER Metal3 ;
        RECT 188.240 354.280 188.640 354.680 ;
    END
  END Tile_X0Y0_WW4END[15]
  PIN Tile_X0Y0_WW4END[1]
    DIRECTION INPUT ;
    USE SIGNAL ;
    ANTENNAGATEAREA 0.665600 ;
    PORT
      LAYER Metal3 ;
        RECT 188.240 330.760 188.640 331.160 ;
    END
  END Tile_X0Y0_WW4END[1]
  PIN Tile_X0Y0_WW4END[2]
    DIRECTION INPUT ;
    USE SIGNAL ;
    ANTENNAGATEAREA 0.681200 ;
    ANTENNADIFFAREA 18.138599 ;
    PORT
      LAYER Metal3 ;
        RECT 188.240 332.440 188.640 332.840 ;
    END
  END Tile_X0Y0_WW4END[2]
  PIN Tile_X0Y0_WW4END[3]
    DIRECTION INPUT ;
    USE SIGNAL ;
    ANTENNAGATEAREA 0.718400 ;
    PORT
      LAYER Metal3 ;
        RECT 188.240 334.120 188.640 334.520 ;
    END
  END Tile_X0Y0_WW4END[3]
  PIN Tile_X0Y0_WW4END[4]
    DIRECTION INPUT ;
    USE SIGNAL ;
    ANTENNAGATEAREA 0.180700 ;
    PORT
      LAYER Metal3 ;
        RECT 188.240 335.800 188.640 336.200 ;
    END
  END Tile_X0Y0_WW4END[4]
  PIN Tile_X0Y0_WW4END[5]
    DIRECTION INPUT ;
    USE SIGNAL ;
    ANTENNAGATEAREA 0.180700 ;
    PORT
      LAYER Metal3 ;
        RECT 188.240 337.480 188.640 337.880 ;
    END
  END Tile_X0Y0_WW4END[5]
  PIN Tile_X0Y0_WW4END[6]
    DIRECTION INPUT ;
    USE SIGNAL ;
    ANTENNAGATEAREA 0.180700 ;
    PORT
      LAYER Metal3 ;
        RECT 188.240 339.160 188.640 339.560 ;
    END
  END Tile_X0Y0_WW4END[6]
  PIN Tile_X0Y0_WW4END[7]
    DIRECTION INPUT ;
    USE SIGNAL ;
    ANTENNAGATEAREA 0.180700 ;
    PORT
      LAYER Metal3 ;
        RECT 188.240 340.840 188.640 341.240 ;
    END
  END Tile_X0Y0_WW4END[7]
  PIN Tile_X0Y0_WW4END[8]
    DIRECTION INPUT ;
    USE SIGNAL ;
    ANTENNAGATEAREA 0.180700 ;
    PORT
      LAYER Metal3 ;
        RECT 188.240 342.520 188.640 342.920 ;
    END
  END Tile_X0Y0_WW4END[8]
  PIN Tile_X0Y0_WW4END[9]
    DIRECTION INPUT ;
    USE SIGNAL ;
    ANTENNAGATEAREA 0.180700 ;
    PORT
      LAYER Metal3 ;
        RECT 188.240 344.200 188.640 344.600 ;
    END
  END Tile_X0Y0_WW4END[9]
  PIN Tile_X0Y1_E1BEG[0]
    DIRECTION OUTPUT ;
    USE SIGNAL ;
    ANTENNADIFFAREA 2.724000 ;
    PORT
      LAYER Metal3 ;
        RECT 188.240 1.060 188.640 1.460 ;
    END
  END Tile_X0Y1_E1BEG[0]
  PIN Tile_X0Y1_E1BEG[1]
    DIRECTION OUTPUT ;
    USE SIGNAL ;
    ANTENNADIFFAREA 2.724000 ;
    PORT
      LAYER Metal3 ;
        RECT 188.240 2.740 188.640 3.140 ;
    END
  END Tile_X0Y1_E1BEG[1]
  PIN Tile_X0Y1_E1BEG[2]
    DIRECTION OUTPUT ;
    USE SIGNAL ;
    ANTENNADIFFAREA 2.724000 ;
    PORT
      LAYER Metal3 ;
        RECT 188.240 4.420 188.640 4.820 ;
    END
  END Tile_X0Y1_E1BEG[2]
  PIN Tile_X0Y1_E1BEG[3]
    DIRECTION OUTPUT ;
    USE SIGNAL ;
    ANTENNADIFFAREA 2.724000 ;
    PORT
      LAYER Metal3 ;
        RECT 188.240 6.100 188.640 6.500 ;
    END
  END Tile_X0Y1_E1BEG[3]
  PIN Tile_X0Y1_E1END[0]
    DIRECTION INPUT ;
    USE SIGNAL ;
    ANTENNAGATEAREA 1.973400 ;
    PORT
      LAYER Metal3 ;
        RECT 0.000 1.060 0.400 1.460 ;
    END
  END Tile_X0Y1_E1END[0]
  PIN Tile_X0Y1_E1END[1]
    DIRECTION INPUT ;
    USE SIGNAL ;
    ANTENNAGATEAREA 1.886300 ;
    PORT
      LAYER Metal3 ;
        RECT 0.000 2.740 0.400 3.140 ;
    END
  END Tile_X0Y1_E1END[1]
  PIN Tile_X0Y1_E1END[2]
    DIRECTION INPUT ;
    USE SIGNAL ;
    ANTENNAGATEAREA 2.341300 ;
    PORT
      LAYER Metal3 ;
        RECT 0.000 4.420 0.400 4.820 ;
    END
  END Tile_X0Y1_E1END[2]
  PIN Tile_X0Y1_E1END[3]
    DIRECTION INPUT ;
    USE SIGNAL ;
    ANTENNAGATEAREA 2.354300 ;
    PORT
      LAYER Metal3 ;
        RECT 0.000 6.100 0.400 6.500 ;
    END
  END Tile_X0Y1_E1END[3]
  PIN Tile_X0Y1_E2BEG[0]
    DIRECTION OUTPUT ;
    USE SIGNAL ;
    ANTENNADIFFAREA 2.724000 ;
    PORT
      LAYER Metal3 ;
        RECT 188.240 10.300 188.640 10.700 ;
    END
  END Tile_X0Y1_E2BEG[0]
  PIN Tile_X0Y1_E2BEG[1]
    DIRECTION OUTPUT ;
    USE SIGNAL ;
    ANTENNADIFFAREA 2.724000 ;
    PORT
      LAYER Metal3 ;
        RECT 188.240 11.140 188.640 11.540 ;
    END
  END Tile_X0Y1_E2BEG[1]
  PIN Tile_X0Y1_E2BEG[2]
    DIRECTION OUTPUT ;
    USE SIGNAL ;
    ANTENNADIFFAREA 2.724000 ;
    PORT
      LAYER Metal3 ;
        RECT 188.240 11.980 188.640 12.380 ;
    END
  END Tile_X0Y1_E2BEG[2]
  PIN Tile_X0Y1_E2BEG[3]
    DIRECTION OUTPUT ;
    USE SIGNAL ;
    ANTENNADIFFAREA 2.724000 ;
    PORT
      LAYER Metal3 ;
        RECT 188.240 12.820 188.640 13.220 ;
    END
  END Tile_X0Y1_E2BEG[3]
  PIN Tile_X0Y1_E2BEG[4]
    DIRECTION OUTPUT ;
    USE SIGNAL ;
    ANTENNADIFFAREA 2.724000 ;
    PORT
      LAYER Metal3 ;
        RECT 188.240 13.660 188.640 14.060 ;
    END
  END Tile_X0Y1_E2BEG[4]
  PIN Tile_X0Y1_E2BEG[5]
    DIRECTION OUTPUT ;
    USE SIGNAL ;
    ANTENNADIFFAREA 2.724000 ;
    PORT
      LAYER Metal3 ;
        RECT 188.240 14.500 188.640 14.900 ;
    END
  END Tile_X0Y1_E2BEG[5]
  PIN Tile_X0Y1_E2BEG[6]
    DIRECTION OUTPUT ;
    USE SIGNAL ;
    ANTENNADIFFAREA 2.724000 ;
    PORT
      LAYER Metal3 ;
        RECT 188.240 15.340 188.640 15.740 ;
    END
  END Tile_X0Y1_E2BEG[6]
  PIN Tile_X0Y1_E2BEG[7]
    DIRECTION OUTPUT ;
    USE SIGNAL ;
    ANTENNADIFFAREA 2.724000 ;
    PORT
      LAYER Metal3 ;
        RECT 188.240 16.180 188.640 16.580 ;
    END
  END Tile_X0Y1_E2BEG[7]
  PIN Tile_X0Y1_E2BEGb[0]
    DIRECTION OUTPUT ;
    USE SIGNAL ;
    ANTENNADIFFAREA 2.724000 ;
    PORT
      LAYER Metal3 ;
        RECT 188.240 20.380 188.640 20.780 ;
    END
  END Tile_X0Y1_E2BEGb[0]
  PIN Tile_X0Y1_E2BEGb[1]
    DIRECTION OUTPUT ;
    USE SIGNAL ;
    ANTENNADIFFAREA 2.724000 ;
    PORT
      LAYER Metal3 ;
        RECT 188.240 22.060 188.640 22.460 ;
    END
  END Tile_X0Y1_E2BEGb[1]
  PIN Tile_X0Y1_E2BEGb[2]
    DIRECTION OUTPUT ;
    USE SIGNAL ;
    ANTENNADIFFAREA 2.724000 ;
    PORT
      LAYER Metal3 ;
        RECT 188.240 23.740 188.640 24.140 ;
    END
  END Tile_X0Y1_E2BEGb[2]
  PIN Tile_X0Y1_E2BEGb[3]
    DIRECTION OUTPUT ;
    USE SIGNAL ;
    ANTENNADIFFAREA 2.724000 ;
    PORT
      LAYER Metal3 ;
        RECT 188.240 25.420 188.640 25.820 ;
    END
  END Tile_X0Y1_E2BEGb[3]
  PIN Tile_X0Y1_E2BEGb[4]
    DIRECTION OUTPUT ;
    USE SIGNAL ;
    ANTENNADIFFAREA 2.724000 ;
    PORT
      LAYER Metal3 ;
        RECT 188.240 27.100 188.640 27.500 ;
    END
  END Tile_X0Y1_E2BEGb[4]
  PIN Tile_X0Y1_E2BEGb[5]
    DIRECTION OUTPUT ;
    USE SIGNAL ;
    ANTENNADIFFAREA 2.724000 ;
    PORT
      LAYER Metal3 ;
        RECT 188.240 28.780 188.640 29.180 ;
    END
  END Tile_X0Y1_E2BEGb[5]
  PIN Tile_X0Y1_E2BEGb[6]
    DIRECTION OUTPUT ;
    USE SIGNAL ;
    ANTENNADIFFAREA 2.724000 ;
    PORT
      LAYER Metal3 ;
        RECT 188.240 30.460 188.640 30.860 ;
    END
  END Tile_X0Y1_E2BEGb[6]
  PIN Tile_X0Y1_E2BEGb[7]
    DIRECTION OUTPUT ;
    USE SIGNAL ;
    ANTENNADIFFAREA 2.724000 ;
    PORT
      LAYER Metal3 ;
        RECT 188.240 32.140 188.640 32.540 ;
    END
  END Tile_X0Y1_E2BEGb[7]
  PIN Tile_X0Y1_E2END[0]
    DIRECTION INPUT ;
    USE SIGNAL ;
    ANTENNAGATEAREA 0.852800 ;
    PORT
      LAYER Metal3 ;
        RECT 0.000 20.380 0.400 20.780 ;
    END
  END Tile_X0Y1_E2END[0]
  PIN Tile_X0Y1_E2END[1]
    DIRECTION INPUT ;
    USE SIGNAL ;
    ANTENNAGATEAREA 0.848900 ;
    PORT
      LAYER Metal3 ;
        RECT 0.000 22.060 0.400 22.460 ;
    END
  END Tile_X0Y1_E2END[1]
  PIN Tile_X0Y1_E2END[2]
    DIRECTION INPUT ;
    USE SIGNAL ;
    ANTENNAGATEAREA 1.094600 ;
    PORT
      LAYER Metal3 ;
        RECT 0.000 23.740 0.400 24.140 ;
    END
  END Tile_X0Y1_E2END[2]
  PIN Tile_X0Y1_E2END[3]
    DIRECTION INPUT ;
    USE SIGNAL ;
    ANTENNAGATEAREA 1.697800 ;
    PORT
      LAYER Metal3 ;
        RECT 0.000 25.420 0.400 25.820 ;
    END
  END Tile_X0Y1_E2END[3]
  PIN Tile_X0Y1_E2END[4]
    DIRECTION INPUT ;
    USE SIGNAL ;
    ANTENNAGATEAREA 1.103700 ;
    PORT
      LAYER Metal3 ;
        RECT 0.000 27.100 0.400 27.500 ;
    END
  END Tile_X0Y1_E2END[4]
  PIN Tile_X0Y1_E2END[5]
    DIRECTION INPUT ;
    USE SIGNAL ;
    ANTENNAGATEAREA 1.279200 ;
    PORT
      LAYER Metal3 ;
        RECT 0.000 28.780 0.400 29.180 ;
    END
  END Tile_X0Y1_E2END[5]
  PIN Tile_X0Y1_E2END[6]
    DIRECTION INPUT ;
    USE SIGNAL ;
    ANTENNAGATEAREA 1.279200 ;
    PORT
      LAYER Metal3 ;
        RECT 0.000 30.460 0.400 30.860 ;
    END
  END Tile_X0Y1_E2END[6]
  PIN Tile_X0Y1_E2END[7]
    DIRECTION INPUT ;
    USE SIGNAL ;
    ANTENNAGATEAREA 1.066000 ;
    PORT
      LAYER Metal3 ;
        RECT 0.000 32.140 0.400 32.540 ;
    END
  END Tile_X0Y1_E2END[7]
  PIN Tile_X0Y1_E2MID[0]
    DIRECTION INPUT ;
    USE SIGNAL ;
    ANTENNAGATEAREA 1.075100 ;
    PORT
      LAYER Metal3 ;
        RECT 0.000 10.300 0.400 10.700 ;
    END
  END Tile_X0Y1_E2MID[0]
  PIN Tile_X0Y1_E2MID[1]
    DIRECTION INPUT ;
    USE SIGNAL ;
    ANTENNAGATEAREA 0.848900 ;
    PORT
      LAYER Metal3 ;
        RECT 0.000 11.140 0.400 11.540 ;
    END
  END Tile_X0Y1_E2MID[1]
  PIN Tile_X0Y1_E2MID[2]
    DIRECTION INPUT ;
    USE SIGNAL ;
    ANTENNAGATEAREA 0.829400 ;
    ANTENNADIFFAREA 8.061600 ;
    PORT
      LAYER Metal3 ;
        RECT 0.000 11.980 0.400 12.380 ;
    END
  END Tile_X0Y1_E2MID[2]
  PIN Tile_X0Y1_E2MID[3]
    DIRECTION INPUT ;
    USE SIGNAL ;
    ANTENNAGATEAREA 0.848900 ;
    ANTENNADIFFAREA 14.107800 ;
    PORT
      LAYER Metal3 ;
        RECT 0.000 12.820 0.400 13.220 ;
    END
  END Tile_X0Y1_E2MID[3]
  PIN Tile_X0Y1_E2MID[4]
    DIRECTION INPUT ;
    USE SIGNAL ;
    ANTENNAGATEAREA 0.846300 ;
    PORT
      LAYER Metal3 ;
        RECT 0.000 13.660 0.400 14.060 ;
    END
  END Tile_X0Y1_E2MID[4]
  PIN Tile_X0Y1_E2MID[5]
    DIRECTION INPUT ;
    USE SIGNAL ;
    ANTENNAGATEAREA 1.119300 ;
    ANTENNADIFFAREA 10.077000 ;
    PORT
      LAYER Metal3 ;
        RECT 0.000 14.500 0.400 14.900 ;
    END
  END Tile_X0Y1_E2MID[5]
  PIN Tile_X0Y1_E2MID[6]
    DIRECTION INPUT ;
    USE SIGNAL ;
    ANTENNAGATEAREA 1.095400 ;
    PORT
      LAYER Metal3 ;
        RECT 0.000 15.340 0.400 15.740 ;
    END
  END Tile_X0Y1_E2MID[6]
  PIN Tile_X0Y1_E2MID[7]
    DIRECTION INPUT ;
    USE SIGNAL ;
    ANTENNAGATEAREA 0.422500 ;
    ANTENNADIFFAREA 8.061600 ;
    PORT
      LAYER Metal3 ;
        RECT 0.000 16.180 0.400 16.580 ;
    END
  END Tile_X0Y1_E2MID[7]
  PIN Tile_X0Y1_E6BEG[0]
    DIRECTION OUTPUT ;
    USE SIGNAL ;
    ANTENNADIFFAREA 2.724000 ;
    PORT
      LAYER Metal3 ;
        RECT 188.240 59.860 188.640 60.260 ;
    END
  END Tile_X0Y1_E6BEG[0]
  PIN Tile_X0Y1_E6BEG[10]
    DIRECTION OUTPUT ;
    USE SIGNAL ;
    ANTENNADIFFAREA 2.724000 ;
    PORT
      LAYER Metal3 ;
        RECT 188.240 76.660 188.640 77.060 ;
    END
  END Tile_X0Y1_E6BEG[10]
  PIN Tile_X0Y1_E6BEG[11]
    DIRECTION OUTPUT ;
    USE SIGNAL ;
    ANTENNADIFFAREA 2.724000 ;
    PORT
      LAYER Metal3 ;
        RECT 188.240 78.340 188.640 78.740 ;
    END
  END Tile_X0Y1_E6BEG[11]
  PIN Tile_X0Y1_E6BEG[1]
    DIRECTION OUTPUT ;
    USE SIGNAL ;
    ANTENNADIFFAREA 2.724000 ;
    PORT
      LAYER Metal3 ;
        RECT 188.240 61.540 188.640 61.940 ;
    END
  END Tile_X0Y1_E6BEG[1]
  PIN Tile_X0Y1_E6BEG[2]
    DIRECTION OUTPUT ;
    USE SIGNAL ;
    ANTENNADIFFAREA 2.724000 ;
    PORT
      LAYER Metal3 ;
        RECT 188.240 63.220 188.640 63.620 ;
    END
  END Tile_X0Y1_E6BEG[2]
  PIN Tile_X0Y1_E6BEG[3]
    DIRECTION OUTPUT ;
    USE SIGNAL ;
    ANTENNADIFFAREA 2.724000 ;
    PORT
      LAYER Metal3 ;
        RECT 188.240 64.900 188.640 65.300 ;
    END
  END Tile_X0Y1_E6BEG[3]
  PIN Tile_X0Y1_E6BEG[4]
    DIRECTION OUTPUT ;
    USE SIGNAL ;
    ANTENNADIFFAREA 2.724000 ;
    PORT
      LAYER Metal3 ;
        RECT 188.240 66.580 188.640 66.980 ;
    END
  END Tile_X0Y1_E6BEG[4]
  PIN Tile_X0Y1_E6BEG[5]
    DIRECTION OUTPUT ;
    USE SIGNAL ;
    ANTENNADIFFAREA 2.724000 ;
    PORT
      LAYER Metal3 ;
        RECT 188.240 68.260 188.640 68.660 ;
    END
  END Tile_X0Y1_E6BEG[5]
  PIN Tile_X0Y1_E6BEG[6]
    DIRECTION OUTPUT ;
    USE SIGNAL ;
    ANTENNADIFFAREA 2.724000 ;
    PORT
      LAYER Metal3 ;
        RECT 188.240 69.940 188.640 70.340 ;
    END
  END Tile_X0Y1_E6BEG[6]
  PIN Tile_X0Y1_E6BEG[7]
    DIRECTION OUTPUT ;
    USE SIGNAL ;
    ANTENNADIFFAREA 2.724000 ;
    PORT
      LAYER Metal3 ;
        RECT 188.240 71.620 188.640 72.020 ;
    END
  END Tile_X0Y1_E6BEG[7]
  PIN Tile_X0Y1_E6BEG[8]
    DIRECTION OUTPUT ;
    USE SIGNAL ;
    ANTENNADIFFAREA 2.724000 ;
    PORT
      LAYER Metal3 ;
        RECT 188.240 73.300 188.640 73.700 ;
    END
  END Tile_X0Y1_E6BEG[8]
  PIN Tile_X0Y1_E6BEG[9]
    DIRECTION OUTPUT ;
    USE SIGNAL ;
    ANTENNADIFFAREA 2.724000 ;
    PORT
      LAYER Metal3 ;
        RECT 188.240 74.980 188.640 75.380 ;
    END
  END Tile_X0Y1_E6BEG[9]
  PIN Tile_X0Y1_E6END[0]
    DIRECTION INPUT ;
    USE SIGNAL ;
    ANTENNAGATEAREA 2.683200 ;
    PORT
      LAYER Metal3 ;
        RECT 0.000 59.860 0.400 60.260 ;
    END
  END Tile_X0Y1_E6END[0]
  PIN Tile_X0Y1_E6END[10]
    DIRECTION INPUT ;
    USE SIGNAL ;
    ANTENNAGATEAREA 0.180700 ;
    PORT
      LAYER Metal3 ;
        RECT 0.000 76.660 0.400 77.060 ;
    END
  END Tile_X0Y1_E6END[10]
  PIN Tile_X0Y1_E6END[11]
    DIRECTION INPUT ;
    USE SIGNAL ;
    ANTENNAGATEAREA 0.180700 ;
    PORT
      LAYER Metal3 ;
        RECT 0.000 78.340 0.400 78.740 ;
    END
  END Tile_X0Y1_E6END[11]
  PIN Tile_X0Y1_E6END[1]
    DIRECTION INPUT ;
    USE SIGNAL ;
    ANTENNAGATEAREA 2.611700 ;
    PORT
      LAYER Metal3 ;
        RECT 0.000 61.540 0.400 61.940 ;
    END
  END Tile_X0Y1_E6END[1]
  PIN Tile_X0Y1_E6END[2]
    DIRECTION INPUT ;
    USE SIGNAL ;
    ANTENNAGATEAREA 0.180700 ;
    PORT
      LAYER Metal3 ;
        RECT 0.000 63.220 0.400 63.620 ;
    END
  END Tile_X0Y1_E6END[2]
  PIN Tile_X0Y1_E6END[3]
    DIRECTION INPUT ;
    USE SIGNAL ;
    ANTENNAGATEAREA 0.180700 ;
    PORT
      LAYER Metal3 ;
        RECT 0.000 64.900 0.400 65.300 ;
    END
  END Tile_X0Y1_E6END[3]
  PIN Tile_X0Y1_E6END[4]
    DIRECTION INPUT ;
    USE SIGNAL ;
    ANTENNAGATEAREA 0.180700 ;
    PORT
      LAYER Metal3 ;
        RECT 0.000 66.580 0.400 66.980 ;
    END
  END Tile_X0Y1_E6END[4]
  PIN Tile_X0Y1_E6END[5]
    DIRECTION INPUT ;
    USE SIGNAL ;
    ANTENNAGATEAREA 0.180700 ;
    PORT
      LAYER Metal3 ;
        RECT 0.000 68.260 0.400 68.660 ;
    END
  END Tile_X0Y1_E6END[5]
  PIN Tile_X0Y1_E6END[6]
    DIRECTION INPUT ;
    USE SIGNAL ;
    ANTENNAGATEAREA 0.180700 ;
    PORT
      LAYER Metal3 ;
        RECT 0.000 69.940 0.400 70.340 ;
    END
  END Tile_X0Y1_E6END[6]
  PIN Tile_X0Y1_E6END[7]
    DIRECTION INPUT ;
    USE SIGNAL ;
    ANTENNAGATEAREA 0.180700 ;
    PORT
      LAYER Metal3 ;
        RECT 0.000 71.620 0.400 72.020 ;
    END
  END Tile_X0Y1_E6END[7]
  PIN Tile_X0Y1_E6END[8]
    DIRECTION INPUT ;
    USE SIGNAL ;
    ANTENNAGATEAREA 0.180700 ;
    PORT
      LAYER Metal3 ;
        RECT 0.000 73.300 0.400 73.700 ;
    END
  END Tile_X0Y1_E6END[8]
  PIN Tile_X0Y1_E6END[9]
    DIRECTION INPUT ;
    USE SIGNAL ;
    ANTENNAGATEAREA 0.180700 ;
    PORT
      LAYER Metal3 ;
        RECT 0.000 74.980 0.400 75.380 ;
    END
  END Tile_X0Y1_E6END[9]
  PIN Tile_X0Y1_EE4BEG[0]
    DIRECTION OUTPUT ;
    USE SIGNAL ;
    ANTENNADIFFAREA 2.724000 ;
    PORT
      LAYER Metal3 ;
        RECT 188.240 39.700 188.640 40.100 ;
    END
  END Tile_X0Y1_EE4BEG[0]
  PIN Tile_X0Y1_EE4BEG[10]
    DIRECTION OUTPUT ;
    USE SIGNAL ;
    ANTENNADIFFAREA 2.724000 ;
    PORT
      LAYER Metal3 ;
        RECT 188.240 48.100 188.640 48.500 ;
    END
  END Tile_X0Y1_EE4BEG[10]
  PIN Tile_X0Y1_EE4BEG[11]
    DIRECTION OUTPUT ;
    USE SIGNAL ;
    ANTENNADIFFAREA 2.724000 ;
    PORT
      LAYER Metal3 ;
        RECT 188.240 48.940 188.640 49.340 ;
    END
  END Tile_X0Y1_EE4BEG[11]
  PIN Tile_X0Y1_EE4BEG[12]
    DIRECTION OUTPUT ;
    USE SIGNAL ;
    ANTENNADIFFAREA 2.724000 ;
    PORT
      LAYER Metal3 ;
        RECT 188.240 49.780 188.640 50.180 ;
    END
  END Tile_X0Y1_EE4BEG[12]
  PIN Tile_X0Y1_EE4BEG[13]
    DIRECTION OUTPUT ;
    USE SIGNAL ;
    ANTENNADIFFAREA 2.724000 ;
    PORT
      LAYER Metal3 ;
        RECT 188.240 50.620 188.640 51.020 ;
    END
  END Tile_X0Y1_EE4BEG[13]
  PIN Tile_X0Y1_EE4BEG[14]
    DIRECTION OUTPUT ;
    USE SIGNAL ;
    ANTENNADIFFAREA 2.724000 ;
    PORT
      LAYER Metal3 ;
        RECT 188.240 51.460 188.640 51.860 ;
    END
  END Tile_X0Y1_EE4BEG[14]
  PIN Tile_X0Y1_EE4BEG[15]
    DIRECTION OUTPUT ;
    USE SIGNAL ;
    ANTENNADIFFAREA 2.724000 ;
    PORT
      LAYER Metal3 ;
        RECT 188.240 52.300 188.640 52.700 ;
    END
  END Tile_X0Y1_EE4BEG[15]
  PIN Tile_X0Y1_EE4BEG[1]
    DIRECTION OUTPUT ;
    USE SIGNAL ;
    ANTENNADIFFAREA 2.724000 ;
    PORT
      LAYER Metal3 ;
        RECT 188.240 40.540 188.640 40.940 ;
    END
  END Tile_X0Y1_EE4BEG[1]
  PIN Tile_X0Y1_EE4BEG[2]
    DIRECTION OUTPUT ;
    USE SIGNAL ;
    ANTENNADIFFAREA 2.724000 ;
    PORT
      LAYER Metal3 ;
        RECT 188.240 41.380 188.640 41.780 ;
    END
  END Tile_X0Y1_EE4BEG[2]
  PIN Tile_X0Y1_EE4BEG[3]
    DIRECTION OUTPUT ;
    USE SIGNAL ;
    ANTENNADIFFAREA 2.724000 ;
    PORT
      LAYER Metal3 ;
        RECT 188.240 42.220 188.640 42.620 ;
    END
  END Tile_X0Y1_EE4BEG[3]
  PIN Tile_X0Y1_EE4BEG[4]
    DIRECTION OUTPUT ;
    USE SIGNAL ;
    ANTENNADIFFAREA 2.724000 ;
    PORT
      LAYER Metal3 ;
        RECT 188.240 43.060 188.640 43.460 ;
    END
  END Tile_X0Y1_EE4BEG[4]
  PIN Tile_X0Y1_EE4BEG[5]
    DIRECTION OUTPUT ;
    USE SIGNAL ;
    ANTENNADIFFAREA 2.724000 ;
    PORT
      LAYER Metal3 ;
        RECT 188.240 43.900 188.640 44.300 ;
    END
  END Tile_X0Y1_EE4BEG[5]
  PIN Tile_X0Y1_EE4BEG[6]
    DIRECTION OUTPUT ;
    USE SIGNAL ;
    ANTENNADIFFAREA 2.724000 ;
    PORT
      LAYER Metal3 ;
        RECT 188.240 44.740 188.640 45.140 ;
    END
  END Tile_X0Y1_EE4BEG[6]
  PIN Tile_X0Y1_EE4BEG[7]
    DIRECTION OUTPUT ;
    USE SIGNAL ;
    ANTENNADIFFAREA 2.724000 ;
    PORT
      LAYER Metal3 ;
        RECT 188.240 45.580 188.640 45.980 ;
    END
  END Tile_X0Y1_EE4BEG[7]
  PIN Tile_X0Y1_EE4BEG[8]
    DIRECTION OUTPUT ;
    USE SIGNAL ;
    ANTENNADIFFAREA 2.724000 ;
    PORT
      LAYER Metal3 ;
        RECT 188.240 46.420 188.640 46.820 ;
    END
  END Tile_X0Y1_EE4BEG[8]
  PIN Tile_X0Y1_EE4BEG[9]
    DIRECTION OUTPUT ;
    USE SIGNAL ;
    ANTENNADIFFAREA 2.724000 ;
    PORT
      LAYER Metal3 ;
        RECT 188.240 47.260 188.640 47.660 ;
    END
  END Tile_X0Y1_EE4BEG[9]
  PIN Tile_X0Y1_EE4END[0]
    DIRECTION INPUT ;
    USE SIGNAL ;
    ANTENNAGATEAREA 0.668200 ;
    PORT
      LAYER Metal3 ;
        RECT 0.000 39.700 0.400 40.100 ;
    END
  END Tile_X0Y1_EE4END[0]
  PIN Tile_X0Y1_EE4END[10]
    DIRECTION INPUT ;
    USE SIGNAL ;
    ANTENNAGATEAREA 0.180700 ;
    PORT
      LAYER Metal3 ;
        RECT 0.000 48.100 0.400 48.500 ;
    END
  END Tile_X0Y1_EE4END[10]
  PIN Tile_X0Y1_EE4END[11]
    DIRECTION INPUT ;
    USE SIGNAL ;
    ANTENNAGATEAREA 0.180700 ;
    PORT
      LAYER Metal3 ;
        RECT 0.000 48.940 0.400 49.340 ;
    END
  END Tile_X0Y1_EE4END[11]
  PIN Tile_X0Y1_EE4END[12]
    DIRECTION INPUT ;
    USE SIGNAL ;
    ANTENNAGATEAREA 0.180700 ;
    PORT
      LAYER Metal3 ;
        RECT 0.000 49.780 0.400 50.180 ;
    END
  END Tile_X0Y1_EE4END[12]
  PIN Tile_X0Y1_EE4END[13]
    DIRECTION INPUT ;
    USE SIGNAL ;
    ANTENNAGATEAREA 0.180700 ;
    PORT
      LAYER Metal3 ;
        RECT 0.000 50.620 0.400 51.020 ;
    END
  END Tile_X0Y1_EE4END[13]
  PIN Tile_X0Y1_EE4END[14]
    DIRECTION INPUT ;
    USE SIGNAL ;
    ANTENNAGATEAREA 0.180700 ;
    PORT
      LAYER Metal3 ;
        RECT 0.000 51.460 0.400 51.860 ;
    END
  END Tile_X0Y1_EE4END[14]
  PIN Tile_X0Y1_EE4END[15]
    DIRECTION INPUT ;
    USE SIGNAL ;
    ANTENNAGATEAREA 0.180700 ;
    PORT
      LAYER Metal3 ;
        RECT 0.000 52.300 0.400 52.700 ;
    END
  END Tile_X0Y1_EE4END[15]
  PIN Tile_X0Y1_EE4END[1]
    DIRECTION INPUT ;
    USE SIGNAL ;
    ANTENNAGATEAREA 0.696800 ;
    PORT
      LAYER Metal3 ;
        RECT 0.000 40.540 0.400 40.940 ;
    END
  END Tile_X0Y1_EE4END[1]
  PIN Tile_X0Y1_EE4END[2]
    DIRECTION INPUT ;
    USE SIGNAL ;
    ANTENNAGATEAREA 0.607100 ;
    PORT
      LAYER Metal3 ;
        RECT 0.000 41.380 0.400 41.780 ;
    END
  END Tile_X0Y1_EE4END[2]
  PIN Tile_X0Y1_EE4END[3]
    DIRECTION INPUT ;
    USE SIGNAL ;
    ANTENNAGATEAREA 0.393900 ;
    PORT
      LAYER Metal3 ;
        RECT 0.000 42.220 0.400 42.620 ;
    END
  END Tile_X0Y1_EE4END[3]
  PIN Tile_X0Y1_EE4END[4]
    DIRECTION INPUT ;
    USE SIGNAL ;
    ANTENNAGATEAREA 0.180700 ;
    PORT
      LAYER Metal3 ;
        RECT 0.000 43.060 0.400 43.460 ;
    END
  END Tile_X0Y1_EE4END[4]
  PIN Tile_X0Y1_EE4END[5]
    DIRECTION INPUT ;
    USE SIGNAL ;
    ANTENNAGATEAREA 0.180700 ;
    PORT
      LAYER Metal3 ;
        RECT 0.000 43.900 0.400 44.300 ;
    END
  END Tile_X0Y1_EE4END[5]
  PIN Tile_X0Y1_EE4END[6]
    DIRECTION INPUT ;
    USE SIGNAL ;
    ANTENNAGATEAREA 0.180700 ;
    PORT
      LAYER Metal3 ;
        RECT 0.000 44.740 0.400 45.140 ;
    END
  END Tile_X0Y1_EE4END[6]
  PIN Tile_X0Y1_EE4END[7]
    DIRECTION INPUT ;
    USE SIGNAL ;
    ANTENNAGATEAREA 0.180700 ;
    PORT
      LAYER Metal3 ;
        RECT 0.000 45.580 0.400 45.980 ;
    END
  END Tile_X0Y1_EE4END[7]
  PIN Tile_X0Y1_EE4END[8]
    DIRECTION INPUT ;
    USE SIGNAL ;
    ANTENNAGATEAREA 0.180700 ;
    PORT
      LAYER Metal3 ;
        RECT 0.000 46.420 0.400 46.820 ;
    END
  END Tile_X0Y1_EE4END[8]
  PIN Tile_X0Y1_EE4END[9]
    DIRECTION INPUT ;
    USE SIGNAL ;
    ANTENNAGATEAREA 0.180700 ;
    PORT
      LAYER Metal3 ;
        RECT 0.000 47.260 0.400 47.660 ;
    END
  END Tile_X0Y1_EE4END[9]
  PIN Tile_X0Y1_FrameData[0]
    DIRECTION INPUT ;
    USE SIGNAL ;
    ANTENNAGATEAREA 2.529800 ;
    PORT
      LAYER Metal3 ;
        RECT 0.000 162.340 0.400 162.740 ;
    END
  END Tile_X0Y1_FrameData[0]
  PIN Tile_X0Y1_FrameData[10]
    DIRECTION INPUT ;
    USE SIGNAL ;
    ANTENNAGATEAREA 2.529800 ;
    PORT
      LAYER Metal3 ;
        RECT 0.000 179.140 0.400 179.540 ;
    END
  END Tile_X0Y1_FrameData[10]
  PIN Tile_X0Y1_FrameData[11]
    DIRECTION INPUT ;
    USE SIGNAL ;
    ANTENNAGATEAREA 2.529800 ;
    PORT
      LAYER Metal3 ;
        RECT 0.000 180.820 0.400 181.220 ;
    END
  END Tile_X0Y1_FrameData[11]
  PIN Tile_X0Y1_FrameData[12]
    DIRECTION INPUT ;
    USE SIGNAL ;
    ANTENNAGATEAREA 2.529800 ;
    PORT
      LAYER Metal3 ;
        RECT 0.000 182.500 0.400 182.900 ;
    END
  END Tile_X0Y1_FrameData[12]
  PIN Tile_X0Y1_FrameData[13]
    DIRECTION INPUT ;
    USE SIGNAL ;
    ANTENNAGATEAREA 2.529800 ;
    PORT
      LAYER Metal3 ;
        RECT 0.000 184.180 0.400 184.580 ;
    END
  END Tile_X0Y1_FrameData[13]
  PIN Tile_X0Y1_FrameData[14]
    DIRECTION INPUT ;
    USE SIGNAL ;
    ANTENNAGATEAREA 2.529800 ;
    PORT
      LAYER Metal3 ;
        RECT 0.000 185.860 0.400 186.260 ;
    END
  END Tile_X0Y1_FrameData[14]
  PIN Tile_X0Y1_FrameData[15]
    DIRECTION INPUT ;
    USE SIGNAL ;
    ANTENNAGATEAREA 2.529800 ;
    PORT
      LAYER Metal3 ;
        RECT 0.000 187.540 0.400 187.940 ;
    END
  END Tile_X0Y1_FrameData[15]
  PIN Tile_X0Y1_FrameData[16]
    DIRECTION INPUT ;
    USE SIGNAL ;
    ANTENNAGATEAREA 2.529800 ;
    PORT
      LAYER Metal3 ;
        RECT 0.000 189.220 0.400 189.620 ;
    END
  END Tile_X0Y1_FrameData[16]
  PIN Tile_X0Y1_FrameData[17]
    DIRECTION INPUT ;
    USE SIGNAL ;
    ANTENNAGATEAREA 2.529800 ;
    PORT
      LAYER Metal3 ;
        RECT 0.000 190.900 0.400 191.300 ;
    END
  END Tile_X0Y1_FrameData[17]
  PIN Tile_X0Y1_FrameData[18]
    DIRECTION INPUT ;
    USE SIGNAL ;
    ANTENNAGATEAREA 2.529800 ;
    PORT
      LAYER Metal3 ;
        RECT 0.000 192.580 0.400 192.980 ;
    END
  END Tile_X0Y1_FrameData[18]
  PIN Tile_X0Y1_FrameData[19]
    DIRECTION INPUT ;
    USE SIGNAL ;
    ANTENNAGATEAREA 2.529800 ;
    PORT
      LAYER Metal3 ;
        RECT 0.000 194.260 0.400 194.660 ;
    END
  END Tile_X0Y1_FrameData[19]
  PIN Tile_X0Y1_FrameData[1]
    DIRECTION INPUT ;
    USE SIGNAL ;
    ANTENNAGATEAREA 2.529800 ;
    PORT
      LAYER Metal3 ;
        RECT 0.000 164.020 0.400 164.420 ;
    END
  END Tile_X0Y1_FrameData[1]
  PIN Tile_X0Y1_FrameData[20]
    DIRECTION INPUT ;
    USE SIGNAL ;
    ANTENNAGATEAREA 2.529800 ;
    PORT
      LAYER Metal3 ;
        RECT 0.000 195.940 0.400 196.340 ;
    END
  END Tile_X0Y1_FrameData[20]
  PIN Tile_X0Y1_FrameData[21]
    DIRECTION INPUT ;
    USE SIGNAL ;
    ANTENNAGATEAREA 2.529800 ;
    PORT
      LAYER Metal3 ;
        RECT 0.000 197.620 0.400 198.020 ;
    END
  END Tile_X0Y1_FrameData[21]
  PIN Tile_X0Y1_FrameData[22]
    DIRECTION INPUT ;
    USE SIGNAL ;
    ANTENNAGATEAREA 2.529800 ;
    PORT
      LAYER Metal3 ;
        RECT 0.000 199.300 0.400 199.700 ;
    END
  END Tile_X0Y1_FrameData[22]
  PIN Tile_X0Y1_FrameData[23]
    DIRECTION INPUT ;
    USE SIGNAL ;
    ANTENNAGATEAREA 2.529800 ;
    PORT
      LAYER Metal3 ;
        RECT 0.000 200.980 0.400 201.380 ;
    END
  END Tile_X0Y1_FrameData[23]
  PIN Tile_X0Y1_FrameData[24]
    DIRECTION INPUT ;
    USE SIGNAL ;
    ANTENNAGATEAREA 2.529800 ;
    PORT
      LAYER Metal3 ;
        RECT 0.000 202.660 0.400 203.060 ;
    END
  END Tile_X0Y1_FrameData[24]
  PIN Tile_X0Y1_FrameData[25]
    DIRECTION INPUT ;
    USE SIGNAL ;
    ANTENNAGATEAREA 2.529800 ;
    PORT
      LAYER Metal3 ;
        RECT 0.000 204.340 0.400 204.740 ;
    END
  END Tile_X0Y1_FrameData[25]
  PIN Tile_X0Y1_FrameData[26]
    DIRECTION INPUT ;
    USE SIGNAL ;
    ANTENNAGATEAREA 2.529800 ;
    PORT
      LAYER Metal3 ;
        RECT 0.000 206.020 0.400 206.420 ;
    END
  END Tile_X0Y1_FrameData[26]
  PIN Tile_X0Y1_FrameData[27]
    DIRECTION INPUT ;
    USE SIGNAL ;
    ANTENNAGATEAREA 2.529800 ;
    PORT
      LAYER Metal3 ;
        RECT 0.000 207.700 0.400 208.100 ;
    END
  END Tile_X0Y1_FrameData[27]
  PIN Tile_X0Y1_FrameData[28]
    DIRECTION INPUT ;
    USE SIGNAL ;
    ANTENNAGATEAREA 2.529800 ;
    PORT
      LAYER Metal3 ;
        RECT 0.000 209.380 0.400 209.780 ;
    END
  END Tile_X0Y1_FrameData[28]
  PIN Tile_X0Y1_FrameData[29]
    DIRECTION INPUT ;
    USE SIGNAL ;
    ANTENNAGATEAREA 2.529800 ;
    ANTENNADIFFAREA 30.230999 ;
    PORT
      LAYER Metal3 ;
        RECT 0.000 211.060 0.400 211.460 ;
    END
  END Tile_X0Y1_FrameData[29]
  PIN Tile_X0Y1_FrameData[2]
    DIRECTION INPUT ;
    USE SIGNAL ;
    ANTENNAGATEAREA 2.529800 ;
    PORT
      LAYER Metal3 ;
        RECT 0.000 165.700 0.400 166.100 ;
    END
  END Tile_X0Y1_FrameData[2]
  PIN Tile_X0Y1_FrameData[30]
    DIRECTION INPUT ;
    USE SIGNAL ;
    ANTENNAGATEAREA 2.529800 ;
    PORT
      LAYER Metal3 ;
        RECT 0.000 212.740 0.400 213.140 ;
    END
  END Tile_X0Y1_FrameData[30]
  PIN Tile_X0Y1_FrameData[31]
    DIRECTION INPUT ;
    USE SIGNAL ;
    ANTENNAGATEAREA 2.529800 ;
    PORT
      LAYER Metal3 ;
        RECT 0.000 214.420 0.400 214.820 ;
    END
  END Tile_X0Y1_FrameData[31]
  PIN Tile_X0Y1_FrameData[3]
    DIRECTION INPUT ;
    USE SIGNAL ;
    ANTENNAGATEAREA 2.529800 ;
    PORT
      LAYER Metal3 ;
        RECT 0.000 167.380 0.400 167.780 ;
    END
  END Tile_X0Y1_FrameData[3]
  PIN Tile_X0Y1_FrameData[4]
    DIRECTION INPUT ;
    USE SIGNAL ;
    ANTENNAGATEAREA 2.529800 ;
    PORT
      LAYER Metal3 ;
        RECT 0.000 169.060 0.400 169.460 ;
    END
  END Tile_X0Y1_FrameData[4]
  PIN Tile_X0Y1_FrameData[5]
    DIRECTION INPUT ;
    USE SIGNAL ;
    ANTENNAGATEAREA 2.529800 ;
    PORT
      LAYER Metal3 ;
        RECT 0.000 170.740 0.400 171.140 ;
    END
  END Tile_X0Y1_FrameData[5]
  PIN Tile_X0Y1_FrameData[6]
    DIRECTION INPUT ;
    USE SIGNAL ;
    ANTENNAGATEAREA 2.529800 ;
    PORT
      LAYER Metal3 ;
        RECT 0.000 172.420 0.400 172.820 ;
    END
  END Tile_X0Y1_FrameData[6]
  PIN Tile_X0Y1_FrameData[7]
    DIRECTION INPUT ;
    USE SIGNAL ;
    ANTENNAGATEAREA 2.529800 ;
    PORT
      LAYER Metal3 ;
        RECT 0.000 174.100 0.400 174.500 ;
    END
  END Tile_X0Y1_FrameData[7]
  PIN Tile_X0Y1_FrameData[8]
    DIRECTION INPUT ;
    USE SIGNAL ;
    ANTENNAGATEAREA 2.529800 ;
    PORT
      LAYER Metal3 ;
        RECT 0.000 175.780 0.400 176.180 ;
    END
  END Tile_X0Y1_FrameData[8]
  PIN Tile_X0Y1_FrameData[9]
    DIRECTION INPUT ;
    USE SIGNAL ;
    ANTENNAGATEAREA 2.529800 ;
    PORT
      LAYER Metal3 ;
        RECT 0.000 177.460 0.400 177.860 ;
    END
  END Tile_X0Y1_FrameData[9]
  PIN Tile_X0Y1_FrameData_O[0]
    DIRECTION OUTPUT ;
    USE SIGNAL ;
    ANTENNADIFFAREA 2.724000 ;
    PORT
      LAYER Metal3 ;
        RECT 188.240 162.340 188.640 162.740 ;
    END
  END Tile_X0Y1_FrameData_O[0]
  PIN Tile_X0Y1_FrameData_O[10]
    DIRECTION OUTPUT ;
    USE SIGNAL ;
    ANTENNADIFFAREA 2.724000 ;
    PORT
      LAYER Metal3 ;
        RECT 188.240 179.140 188.640 179.540 ;
    END
  END Tile_X0Y1_FrameData_O[10]
  PIN Tile_X0Y1_FrameData_O[11]
    DIRECTION OUTPUT ;
    USE SIGNAL ;
    ANTENNADIFFAREA 2.724000 ;
    PORT
      LAYER Metal3 ;
        RECT 188.240 180.820 188.640 181.220 ;
    END
  END Tile_X0Y1_FrameData_O[11]
  PIN Tile_X0Y1_FrameData_O[12]
    DIRECTION OUTPUT ;
    USE SIGNAL ;
    ANTENNADIFFAREA 2.724000 ;
    PORT
      LAYER Metal3 ;
        RECT 188.240 182.500 188.640 182.900 ;
    END
  END Tile_X0Y1_FrameData_O[12]
  PIN Tile_X0Y1_FrameData_O[13]
    DIRECTION OUTPUT ;
    USE SIGNAL ;
    ANTENNADIFFAREA 2.724000 ;
    PORT
      LAYER Metal3 ;
        RECT 188.240 184.180 188.640 184.580 ;
    END
  END Tile_X0Y1_FrameData_O[13]
  PIN Tile_X0Y1_FrameData_O[14]
    DIRECTION OUTPUT ;
    USE SIGNAL ;
    ANTENNADIFFAREA 2.724000 ;
    PORT
      LAYER Metal3 ;
        RECT 188.240 185.860 188.640 186.260 ;
    END
  END Tile_X0Y1_FrameData_O[14]
  PIN Tile_X0Y1_FrameData_O[15]
    DIRECTION OUTPUT ;
    USE SIGNAL ;
    ANTENNADIFFAREA 2.724000 ;
    PORT
      LAYER Metal3 ;
        RECT 188.240 187.540 188.640 187.940 ;
    END
  END Tile_X0Y1_FrameData_O[15]
  PIN Tile_X0Y1_FrameData_O[16]
    DIRECTION OUTPUT ;
    USE SIGNAL ;
    ANTENNADIFFAREA 2.724000 ;
    PORT
      LAYER Metal3 ;
        RECT 188.240 189.220 188.640 189.620 ;
    END
  END Tile_X0Y1_FrameData_O[16]
  PIN Tile_X0Y1_FrameData_O[17]
    DIRECTION OUTPUT ;
    USE SIGNAL ;
    ANTENNADIFFAREA 2.724000 ;
    PORT
      LAYER Metal3 ;
        RECT 188.240 190.900 188.640 191.300 ;
    END
  END Tile_X0Y1_FrameData_O[17]
  PIN Tile_X0Y1_FrameData_O[18]
    DIRECTION OUTPUT ;
    USE SIGNAL ;
    ANTENNADIFFAREA 2.724000 ;
    PORT
      LAYER Metal3 ;
        RECT 188.240 192.580 188.640 192.980 ;
    END
  END Tile_X0Y1_FrameData_O[18]
  PIN Tile_X0Y1_FrameData_O[19]
    DIRECTION OUTPUT ;
    USE SIGNAL ;
    ANTENNADIFFAREA 2.724000 ;
    PORT
      LAYER Metal3 ;
        RECT 188.240 194.260 188.640 194.660 ;
    END
  END Tile_X0Y1_FrameData_O[19]
  PIN Tile_X0Y1_FrameData_O[1]
    DIRECTION OUTPUT ;
    USE SIGNAL ;
    ANTENNADIFFAREA 2.724000 ;
    PORT
      LAYER Metal3 ;
        RECT 188.240 164.020 188.640 164.420 ;
    END
  END Tile_X0Y1_FrameData_O[1]
  PIN Tile_X0Y1_FrameData_O[20]
    DIRECTION OUTPUT ;
    USE SIGNAL ;
    ANTENNADIFFAREA 2.724000 ;
    PORT
      LAYER Metal3 ;
        RECT 188.240 195.940 188.640 196.340 ;
    END
  END Tile_X0Y1_FrameData_O[20]
  PIN Tile_X0Y1_FrameData_O[21]
    DIRECTION OUTPUT ;
    USE SIGNAL ;
    ANTENNADIFFAREA 2.724000 ;
    PORT
      LAYER Metal3 ;
        RECT 188.240 197.620 188.640 198.020 ;
    END
  END Tile_X0Y1_FrameData_O[21]
  PIN Tile_X0Y1_FrameData_O[22]
    DIRECTION OUTPUT ;
    USE SIGNAL ;
    ANTENNADIFFAREA 2.724000 ;
    PORT
      LAYER Metal3 ;
        RECT 188.240 199.300 188.640 199.700 ;
    END
  END Tile_X0Y1_FrameData_O[22]
  PIN Tile_X0Y1_FrameData_O[23]
    DIRECTION OUTPUT ;
    USE SIGNAL ;
    ANTENNADIFFAREA 2.724000 ;
    PORT
      LAYER Metal3 ;
        RECT 188.240 200.980 188.640 201.380 ;
    END
  END Tile_X0Y1_FrameData_O[23]
  PIN Tile_X0Y1_FrameData_O[24]
    DIRECTION OUTPUT ;
    USE SIGNAL ;
    ANTENNADIFFAREA 2.724000 ;
    PORT
      LAYER Metal3 ;
        RECT 188.240 202.660 188.640 203.060 ;
    END
  END Tile_X0Y1_FrameData_O[24]
  PIN Tile_X0Y1_FrameData_O[25]
    DIRECTION OUTPUT ;
    USE SIGNAL ;
    ANTENNADIFFAREA 2.724000 ;
    PORT
      LAYER Metal3 ;
        RECT 188.240 204.340 188.640 204.740 ;
    END
  END Tile_X0Y1_FrameData_O[25]
  PIN Tile_X0Y1_FrameData_O[26]
    DIRECTION OUTPUT ;
    USE SIGNAL ;
    ANTENNADIFFAREA 2.724000 ;
    PORT
      LAYER Metal3 ;
        RECT 188.240 206.020 188.640 206.420 ;
    END
  END Tile_X0Y1_FrameData_O[26]
  PIN Tile_X0Y1_FrameData_O[27]
    DIRECTION OUTPUT ;
    USE SIGNAL ;
    ANTENNADIFFAREA 2.724000 ;
    PORT
      LAYER Metal3 ;
        RECT 188.240 207.700 188.640 208.100 ;
    END
  END Tile_X0Y1_FrameData_O[27]
  PIN Tile_X0Y1_FrameData_O[28]
    DIRECTION OUTPUT ;
    USE SIGNAL ;
    ANTENNADIFFAREA 2.724000 ;
    PORT
      LAYER Metal3 ;
        RECT 188.240 209.380 188.640 209.780 ;
    END
  END Tile_X0Y1_FrameData_O[28]
  PIN Tile_X0Y1_FrameData_O[29]
    DIRECTION OUTPUT ;
    USE SIGNAL ;
    ANTENNADIFFAREA 2.724000 ;
    PORT
      LAYER Metal3 ;
        RECT 188.240 211.060 188.640 211.460 ;
    END
  END Tile_X0Y1_FrameData_O[29]
  PIN Tile_X0Y1_FrameData_O[2]
    DIRECTION OUTPUT ;
    USE SIGNAL ;
    ANTENNADIFFAREA 2.724000 ;
    PORT
      LAYER Metal3 ;
        RECT 188.240 165.700 188.640 166.100 ;
    END
  END Tile_X0Y1_FrameData_O[2]
  PIN Tile_X0Y1_FrameData_O[30]
    DIRECTION OUTPUT ;
    USE SIGNAL ;
    ANTENNADIFFAREA 2.724000 ;
    PORT
      LAYER Metal3 ;
        RECT 188.240 212.740 188.640 213.140 ;
    END
  END Tile_X0Y1_FrameData_O[30]
  PIN Tile_X0Y1_FrameData_O[31]
    DIRECTION OUTPUT ;
    USE SIGNAL ;
    ANTENNADIFFAREA 2.724000 ;
    PORT
      LAYER Metal3 ;
        RECT 188.240 214.420 188.640 214.820 ;
    END
  END Tile_X0Y1_FrameData_O[31]
  PIN Tile_X0Y1_FrameData_O[3]
    DIRECTION OUTPUT ;
    USE SIGNAL ;
    ANTENNADIFFAREA 2.724000 ;
    PORT
      LAYER Metal3 ;
        RECT 188.240 167.380 188.640 167.780 ;
    END
  END Tile_X0Y1_FrameData_O[3]
  PIN Tile_X0Y1_FrameData_O[4]
    DIRECTION OUTPUT ;
    USE SIGNAL ;
    ANTENNADIFFAREA 2.724000 ;
    PORT
      LAYER Metal3 ;
        RECT 188.240 169.060 188.640 169.460 ;
    END
  END Tile_X0Y1_FrameData_O[4]
  PIN Tile_X0Y1_FrameData_O[5]
    DIRECTION OUTPUT ;
    USE SIGNAL ;
    ANTENNADIFFAREA 2.724000 ;
    PORT
      LAYER Metal3 ;
        RECT 188.240 170.740 188.640 171.140 ;
    END
  END Tile_X0Y1_FrameData_O[5]
  PIN Tile_X0Y1_FrameData_O[6]
    DIRECTION OUTPUT ;
    USE SIGNAL ;
    ANTENNADIFFAREA 2.724000 ;
    PORT
      LAYER Metal3 ;
        RECT 188.240 172.420 188.640 172.820 ;
    END
  END Tile_X0Y1_FrameData_O[6]
  PIN Tile_X0Y1_FrameData_O[7]
    DIRECTION OUTPUT ;
    USE SIGNAL ;
    ANTENNADIFFAREA 2.724000 ;
    PORT
      LAYER Metal3 ;
        RECT 188.240 174.100 188.640 174.500 ;
    END
  END Tile_X0Y1_FrameData_O[7]
  PIN Tile_X0Y1_FrameData_O[8]
    DIRECTION OUTPUT ;
    USE SIGNAL ;
    ANTENNADIFFAREA 2.724000 ;
    PORT
      LAYER Metal3 ;
        RECT 188.240 175.780 188.640 176.180 ;
    END
  END Tile_X0Y1_FrameData_O[8]
  PIN Tile_X0Y1_FrameData_O[9]
    DIRECTION OUTPUT ;
    USE SIGNAL ;
    ANTENNADIFFAREA 2.724000 ;
    PORT
      LAYER Metal3 ;
        RECT 188.240 177.460 188.640 177.860 ;
    END
  END Tile_X0Y1_FrameData_O[9]
  PIN Tile_X0Y1_FrameStrobe[0]
    DIRECTION INPUT ;
    USE SIGNAL ;
    ANTENNAGATEAREA 13.326300 ;
    PORT
      LAYER Metal2 ;
        RECT 164.440 0.000 164.840 0.400 ;
    END
  END Tile_X0Y1_FrameStrobe[0]
  PIN Tile_X0Y1_FrameStrobe[10]
    DIRECTION INPUT ;
    USE SIGNAL ;
    ANTENNAGATEAREA 13.326300 ;
    PORT
      LAYER Metal2 ;
        RECT 174.040 0.000 174.440 0.400 ;
    END
  END Tile_X0Y1_FrameStrobe[10]
  PIN Tile_X0Y1_FrameStrobe[11]
    DIRECTION INPUT ;
    USE SIGNAL ;
    ANTENNAGATEAREA 13.326300 ;
    PORT
      LAYER Metal2 ;
        RECT 175.000 0.000 175.400 0.400 ;
    END
  END Tile_X0Y1_FrameStrobe[11]
  PIN Tile_X0Y1_FrameStrobe[12]
    DIRECTION INPUT ;
    USE SIGNAL ;
    ANTENNAGATEAREA 11.272300 ;
    PORT
      LAYER Metal2 ;
        RECT 175.960 0.000 176.360 0.400 ;
    END
  END Tile_X0Y1_FrameStrobe[12]
  PIN Tile_X0Y1_FrameStrobe[13]
    DIRECTION INPUT ;
    USE SIGNAL ;
    ANTENNAGATEAREA 0.180700 ;
    PORT
      LAYER Metal2 ;
        RECT 176.920 0.000 177.320 0.400 ;
    END
  END Tile_X0Y1_FrameStrobe[13]
  PIN Tile_X0Y1_FrameStrobe[14]
    DIRECTION INPUT ;
    USE SIGNAL ;
    ANTENNAGATEAREA 0.180700 ;
    PORT
      LAYER Metal2 ;
        RECT 177.880 0.000 178.280 0.400 ;
    END
  END Tile_X0Y1_FrameStrobe[14]
  PIN Tile_X0Y1_FrameStrobe[15]
    DIRECTION INPUT ;
    USE SIGNAL ;
    ANTENNAGATEAREA 0.180700 ;
    PORT
      LAYER Metal2 ;
        RECT 178.840 0.000 179.240 0.400 ;
    END
  END Tile_X0Y1_FrameStrobe[15]
  PIN Tile_X0Y1_FrameStrobe[16]
    DIRECTION INPUT ;
    USE SIGNAL ;
    ANTENNAGATEAREA 0.180700 ;
    PORT
      LAYER Metal2 ;
        RECT 179.800 0.000 180.200 0.400 ;
    END
  END Tile_X0Y1_FrameStrobe[16]
  PIN Tile_X0Y1_FrameStrobe[17]
    DIRECTION INPUT ;
    USE SIGNAL ;
    ANTENNAGATEAREA 0.180700 ;
    PORT
      LAYER Metal2 ;
        RECT 180.760 0.000 181.160 0.400 ;
    END
  END Tile_X0Y1_FrameStrobe[17]
  PIN Tile_X0Y1_FrameStrobe[18]
    DIRECTION INPUT ;
    USE SIGNAL ;
    ANTENNAGATEAREA 0.180700 ;
    PORT
      LAYER Metal2 ;
        RECT 181.720 0.000 182.120 0.400 ;
    END
  END Tile_X0Y1_FrameStrobe[18]
  PIN Tile_X0Y1_FrameStrobe[19]
    DIRECTION INPUT ;
    USE SIGNAL ;
    ANTENNAGATEAREA 0.180700 ;
    PORT
      LAYER Metal2 ;
        RECT 182.680 0.000 183.080 0.400 ;
    END
  END Tile_X0Y1_FrameStrobe[19]
  PIN Tile_X0Y1_FrameStrobe[1]
    DIRECTION INPUT ;
    USE SIGNAL ;
    ANTENNAGATEAREA 13.326300 ;
    PORT
      LAYER Metal2 ;
        RECT 165.400 0.000 165.800 0.400 ;
    END
  END Tile_X0Y1_FrameStrobe[1]
  PIN Tile_X0Y1_FrameStrobe[2]
    DIRECTION INPUT ;
    USE SIGNAL ;
    ANTENNAGATEAREA 13.326300 ;
    PORT
      LAYER Metal2 ;
        RECT 166.360 0.000 166.760 0.400 ;
    END
  END Tile_X0Y1_FrameStrobe[2]
  PIN Tile_X0Y1_FrameStrobe[3]
    DIRECTION INPUT ;
    USE SIGNAL ;
    ANTENNAGATEAREA 13.326300 ;
    PORT
      LAYER Metal2 ;
        RECT 167.320 0.000 167.720 0.400 ;
    END
  END Tile_X0Y1_FrameStrobe[3]
  PIN Tile_X0Y1_FrameStrobe[4]
    DIRECTION INPUT ;
    USE SIGNAL ;
    ANTENNAGATEAREA 13.326300 ;
    PORT
      LAYER Metal2 ;
        RECT 168.280 0.000 168.680 0.400 ;
    END
  END Tile_X0Y1_FrameStrobe[4]
  PIN Tile_X0Y1_FrameStrobe[5]
    DIRECTION INPUT ;
    USE SIGNAL ;
    ANTENNAGATEAREA 13.326300 ;
    PORT
      LAYER Metal2 ;
        RECT 169.240 0.000 169.640 0.400 ;
    END
  END Tile_X0Y1_FrameStrobe[5]
  PIN Tile_X0Y1_FrameStrobe[6]
    DIRECTION INPUT ;
    USE SIGNAL ;
    ANTENNAGATEAREA 13.326300 ;
    PORT
      LAYER Metal2 ;
        RECT 170.200 0.000 170.600 0.400 ;
    END
  END Tile_X0Y1_FrameStrobe[6]
  PIN Tile_X0Y1_FrameStrobe[7]
    DIRECTION INPUT ;
    USE SIGNAL ;
    ANTENNAGATEAREA 13.326300 ;
    PORT
      LAYER Metal2 ;
        RECT 171.160 0.000 171.560 0.400 ;
    END
  END Tile_X0Y1_FrameStrobe[7]
  PIN Tile_X0Y1_FrameStrobe[8]
    DIRECTION INPUT ;
    USE SIGNAL ;
    ANTENNAGATEAREA 13.326300 ;
    PORT
      LAYER Metal2 ;
        RECT 172.120 0.000 172.520 0.400 ;
    END
  END Tile_X0Y1_FrameStrobe[8]
  PIN Tile_X0Y1_FrameStrobe[9]
    DIRECTION INPUT ;
    USE SIGNAL ;
    ANTENNAGATEAREA 13.326300 ;
    PORT
      LAYER Metal2 ;
        RECT 173.080 0.000 173.480 0.400 ;
    END
  END Tile_X0Y1_FrameStrobe[9]
  PIN Tile_X0Y1_N1END[0]
    DIRECTION INPUT ;
    USE SIGNAL ;
    ANTENNAGATEAREA 2.210800 ;
    PORT
      LAYER Metal2 ;
        RECT 2.200 0.000 2.600 0.400 ;
    END
  END Tile_X0Y1_N1END[0]
  PIN Tile_X0Y1_N1END[1]
    DIRECTION INPUT ;
    USE SIGNAL ;
    ANTENNAGATEAREA 2.132000 ;
    PORT
      LAYER Metal2 ;
        RECT 3.160 0.000 3.560 0.400 ;
    END
  END Tile_X0Y1_N1END[1]
  PIN Tile_X0Y1_N1END[2]
    DIRECTION INPUT ;
    USE SIGNAL ;
    ANTENNAGATEAREA 1.762800 ;
    PORT
      LAYER Metal2 ;
        RECT 4.120 0.000 4.520 0.400 ;
    END
  END Tile_X0Y1_N1END[2]
  PIN Tile_X0Y1_N1END[3]
    DIRECTION INPUT ;
    USE SIGNAL ;
    ANTENNAGATEAREA 2.210800 ;
    PORT
      LAYER Metal2 ;
        RECT 5.080 0.000 5.480 0.400 ;
    END
  END Tile_X0Y1_N1END[3]
  PIN Tile_X0Y1_N2END[0]
    DIRECTION INPUT ;
    USE SIGNAL ;
    ANTENNAGATEAREA 1.492400 ;
    PORT
      LAYER Metal2 ;
        RECT 21.400 0.000 21.800 0.400 ;
    END
  END Tile_X0Y1_N2END[0]
  PIN Tile_X0Y1_N2END[1]
    DIRECTION INPUT ;
    USE SIGNAL ;
    ANTENNAGATEAREA 1.066000 ;
    PORT
      LAYER Metal2 ;
        RECT 22.360 0.000 22.760 0.400 ;
    END
  END Tile_X0Y1_N2END[1]
  PIN Tile_X0Y1_N2END[2]
    DIRECTION INPUT ;
    USE SIGNAL ;
    ANTENNAGATEAREA 1.066000 ;
    PORT
      LAYER Metal2 ;
        RECT 23.320 0.000 23.720 0.400 ;
    END
  END Tile_X0Y1_N2END[2]
  PIN Tile_X0Y1_N2END[3]
    DIRECTION INPUT ;
    USE SIGNAL ;
    ANTENNAGATEAREA 1.279200 ;
    PORT
      LAYER Metal2 ;
        RECT 24.280 0.000 24.680 0.400 ;
    END
  END Tile_X0Y1_N2END[3]
  PIN Tile_X0Y1_N2END[4]
    DIRECTION INPUT ;
    USE SIGNAL ;
    ANTENNAGATEAREA 1.373600 ;
    PORT
      LAYER Metal2 ;
        RECT 25.240 0.000 25.640 0.400 ;
    END
  END Tile_X0Y1_N2END[4]
  PIN Tile_X0Y1_N2END[5]
    DIRECTION INPUT ;
    USE SIGNAL ;
    ANTENNAGATEAREA 1.066000 ;
    PORT
      LAYER Metal2 ;
        RECT 26.200 0.000 26.600 0.400 ;
    END
  END Tile_X0Y1_N2END[5]
  PIN Tile_X0Y1_N2END[6]
    DIRECTION INPUT ;
    USE SIGNAL ;
    ANTENNAGATEAREA 1.066000 ;
    PORT
      LAYER Metal2 ;
        RECT 27.160 0.000 27.560 0.400 ;
    END
  END Tile_X0Y1_N2END[6]
  PIN Tile_X0Y1_N2END[7]
    DIRECTION INPUT ;
    USE SIGNAL ;
    ANTENNAGATEAREA 1.279200 ;
    PORT
      LAYER Metal2 ;
        RECT 28.120 0.000 28.520 0.400 ;
    END
  END Tile_X0Y1_N2END[7]
  PIN Tile_X0Y1_N2MID[0]
    DIRECTION INPUT ;
    USE SIGNAL ;
    ANTENNAGATEAREA 2.239400 ;
    PORT
      LAYER Metal2 ;
        RECT 8.920 0.000 9.320 0.400 ;
    END
  END Tile_X0Y1_N2MID[0]
  PIN Tile_X0Y1_N2MID[1]
    DIRECTION INPUT ;
    USE SIGNAL ;
    ANTENNAGATEAREA 1.980700 ;
    PORT
      LAYER Metal2 ;
        RECT 9.880 0.000 10.280 0.400 ;
    END
  END Tile_X0Y1_N2MID[1]
  PIN Tile_X0Y1_N2MID[2]
    DIRECTION INPUT ;
    USE SIGNAL ;
    ANTENNAGATEAREA 1.621100 ;
    PORT
      LAYER Metal2 ;
        RECT 10.840 0.000 11.240 0.400 ;
    END
  END Tile_X0Y1_N2MID[2]
  PIN Tile_X0Y1_N2MID[3]
    DIRECTION INPUT ;
    USE SIGNAL ;
    ANTENNAGATEAREA 1.734200 ;
    PORT
      LAYER Metal2 ;
        RECT 11.800 0.000 12.200 0.400 ;
    END
  END Tile_X0Y1_N2MID[3]
  PIN Tile_X0Y1_N2MID[4]
    DIRECTION INPUT ;
    USE SIGNAL ;
    ANTENNAGATEAREA 1.944800 ;
    PORT
      LAYER Metal2 ;
        RECT 12.760 0.000 13.160 0.400 ;
    END
  END Tile_X0Y1_N2MID[4]
  PIN Tile_X0Y1_N2MID[5]
    DIRECTION INPUT ;
    USE SIGNAL ;
    ANTENNAGATEAREA 1.307800 ;
    PORT
      LAYER Metal2 ;
        RECT 13.720 0.000 14.120 0.400 ;
    END
  END Tile_X0Y1_N2MID[5]
  PIN Tile_X0Y1_N2MID[6]
    DIRECTION INPUT ;
    USE SIGNAL ;
    ANTENNAGATEAREA 1.993700 ;
    PORT
      LAYER Metal2 ;
        RECT 14.680 0.000 15.080 0.400 ;
    END
  END Tile_X0Y1_N2MID[6]
  PIN Tile_X0Y1_N2MID[7]
    DIRECTION INPUT ;
    USE SIGNAL ;
    ANTENNAGATEAREA 2.079000 ;
    PORT
      LAYER Metal2 ;
        RECT 15.640 0.000 16.040 0.400 ;
    END
  END Tile_X0Y1_N2MID[7]
  PIN Tile_X0Y1_N4END[0]
    DIRECTION INPUT ;
    USE SIGNAL ;
    ANTENNAGATEAREA 1.099300 ;
    PORT
      LAYER Metal2 ;
        RECT 34.840 0.000 35.240 0.400 ;
    END
  END Tile_X0Y1_N4END[0]
  PIN Tile_X0Y1_N4END[10]
    DIRECTION INPUT ;
    USE SIGNAL ;
    ANTENNAGATEAREA 0.180700 ;
    PORT
      LAYER Metal2 ;
        RECT 44.440 0.000 44.840 0.400 ;
    END
  END Tile_X0Y1_N4END[10]
  PIN Tile_X0Y1_N4END[11]
    DIRECTION INPUT ;
    USE SIGNAL ;
    ANTENNAGATEAREA 0.180700 ;
    PORT
      LAYER Metal2 ;
        RECT 45.400 0.000 45.800 0.400 ;
    END
  END Tile_X0Y1_N4END[11]
  PIN Tile_X0Y1_N4END[12]
    DIRECTION INPUT ;
    USE SIGNAL ;
    ANTENNAGATEAREA 0.180700 ;
    PORT
      LAYER Metal2 ;
        RECT 46.360 0.000 46.760 0.400 ;
    END
  END Tile_X0Y1_N4END[12]
  PIN Tile_X0Y1_N4END[13]
    DIRECTION INPUT ;
    USE SIGNAL ;
    ANTENNAGATEAREA 0.180700 ;
    PORT
      LAYER Metal2 ;
        RECT 47.320 0.000 47.720 0.400 ;
    END
  END Tile_X0Y1_N4END[13]
  PIN Tile_X0Y1_N4END[14]
    DIRECTION INPUT ;
    USE SIGNAL ;
    ANTENNAGATEAREA 0.180700 ;
    PORT
      LAYER Metal2 ;
        RECT 48.280 0.000 48.680 0.400 ;
    END
  END Tile_X0Y1_N4END[14]
  PIN Tile_X0Y1_N4END[15]
    DIRECTION INPUT ;
    USE SIGNAL ;
    ANTENNAGATEAREA 0.180700 ;
    PORT
      LAYER Metal2 ;
        RECT 49.240 0.000 49.640 0.400 ;
    END
  END Tile_X0Y1_N4END[15]
  PIN Tile_X0Y1_N4END[1]
    DIRECTION INPUT ;
    USE SIGNAL ;
    ANTENNAGATEAREA 1.075100 ;
    PORT
      LAYER Metal2 ;
        RECT 35.800 0.000 36.200 0.400 ;
    END
  END Tile_X0Y1_N4END[1]
  PIN Tile_X0Y1_N4END[2]
    DIRECTION INPUT ;
    USE SIGNAL ;
    ANTENNAGATEAREA 1.094600 ;
    PORT
      LAYER Metal2 ;
        RECT 36.760 0.000 37.160 0.400 ;
    END
  END Tile_X0Y1_N4END[2]
  PIN Tile_X0Y1_N4END[3]
    DIRECTION INPUT ;
    USE SIGNAL ;
    ANTENNAGATEAREA 1.001000 ;
    ANTENNADIFFAREA 10.077000 ;
    PORT
      LAYER Metal2 ;
        RECT 37.720 0.000 38.120 0.400 ;
    END
  END Tile_X0Y1_N4END[3]
  PIN Tile_X0Y1_N4END[4]
    DIRECTION INPUT ;
    USE SIGNAL ;
    ANTENNAGATEAREA 1.127900 ;
    PORT
      LAYER Metal2 ;
        RECT 38.680 0.000 39.080 0.400 ;
    END
  END Tile_X0Y1_N4END[4]
  PIN Tile_X0Y1_N4END[5]
    DIRECTION INPUT ;
    USE SIGNAL ;
    ANTENNAGATEAREA 1.173400 ;
    PORT
      LAYER Metal2 ;
        RECT 39.640 0.000 40.040 0.400 ;
    END
  END Tile_X0Y1_N4END[5]
  PIN Tile_X0Y1_N4END[6]
    DIRECTION INPUT ;
    USE SIGNAL ;
    ANTENNAGATEAREA 1.160400 ;
    PORT
      LAYER Metal2 ;
        RECT 40.600 0.000 41.000 0.400 ;
    END
  END Tile_X0Y1_N4END[6]
  PIN Tile_X0Y1_N4END[7]
    DIRECTION INPUT ;
    USE SIGNAL ;
    ANTENNAGATEAREA 1.263400 ;
    PORT
      LAYER Metal2 ;
        RECT 41.560 0.000 41.960 0.400 ;
    END
  END Tile_X0Y1_N4END[7]
  PIN Tile_X0Y1_N4END[8]
    DIRECTION INPUT ;
    USE SIGNAL ;
    ANTENNAGATEAREA 0.180700 ;
    PORT
      LAYER Metal2 ;
        RECT 42.520 0.000 42.920 0.400 ;
    END
  END Tile_X0Y1_N4END[8]
  PIN Tile_X0Y1_N4END[9]
    DIRECTION INPUT ;
    USE SIGNAL ;
    ANTENNAGATEAREA 0.180700 ;
    PORT
      LAYER Metal2 ;
        RECT 43.480 0.000 43.880 0.400 ;
    END
  END Tile_X0Y1_N4END[9]
  PIN Tile_X0Y1_NN4END[0]
    DIRECTION INPUT ;
    USE SIGNAL ;
    ANTENNAGATEAREA 0.439400 ;
    PORT
      LAYER Metal2 ;
        RECT 58.840 0.000 59.240 0.400 ;
    END
  END Tile_X0Y1_NN4END[0]
  PIN Tile_X0Y1_NN4END[10]
    DIRECTION INPUT ;
    USE SIGNAL ;
    ANTENNAGATEAREA 0.180700 ;
    PORT
      LAYER Metal2 ;
        RECT 68.440 0.000 68.840 0.400 ;
    END
  END Tile_X0Y1_NN4END[10]
  PIN Tile_X0Y1_NN4END[11]
    DIRECTION INPUT ;
    USE SIGNAL ;
    ANTENNAGATEAREA 0.180700 ;
    PORT
      LAYER Metal2 ;
        RECT 69.400 0.000 69.800 0.400 ;
    END
  END Tile_X0Y1_NN4END[11]
  PIN Tile_X0Y1_NN4END[12]
    DIRECTION INPUT ;
    USE SIGNAL ;
    ANTENNAGATEAREA 0.180700 ;
    PORT
      LAYER Metal2 ;
        RECT 70.360 0.000 70.760 0.400 ;
    END
  END Tile_X0Y1_NN4END[12]
  PIN Tile_X0Y1_NN4END[13]
    DIRECTION INPUT ;
    USE SIGNAL ;
    ANTENNAGATEAREA 0.180700 ;
    PORT
      LAYER Metal2 ;
        RECT 71.320 0.000 71.720 0.400 ;
    END
  END Tile_X0Y1_NN4END[13]
  PIN Tile_X0Y1_NN4END[14]
    DIRECTION INPUT ;
    USE SIGNAL ;
    ANTENNAGATEAREA 0.180700 ;
    PORT
      LAYER Metal2 ;
        RECT 72.280 0.000 72.680 0.400 ;
    END
  END Tile_X0Y1_NN4END[14]
  PIN Tile_X0Y1_NN4END[15]
    DIRECTION INPUT ;
    USE SIGNAL ;
    ANTENNAGATEAREA 0.180700 ;
    PORT
      LAYER Metal2 ;
        RECT 73.240 0.000 73.640 0.400 ;
    END
  END Tile_X0Y1_NN4END[15]
  PIN Tile_X0Y1_NN4END[1]
    DIRECTION INPUT ;
    USE SIGNAL ;
    ANTENNAGATEAREA 0.574600 ;
    PORT
      LAYER Metal2 ;
        RECT 59.800 0.000 60.200 0.400 ;
    END
  END Tile_X0Y1_NN4END[1]
  PIN Tile_X0Y1_NN4END[2]
    DIRECTION INPUT ;
    USE SIGNAL ;
    ANTENNAGATEAREA 0.718400 ;
    PORT
      LAYER Metal2 ;
        RECT 60.760 0.000 61.160 0.400 ;
    END
  END Tile_X0Y1_NN4END[2]
  PIN Tile_X0Y1_NN4END[3]
    DIRECTION INPUT ;
    USE SIGNAL ;
    ANTENNAGATEAREA 0.639600 ;
    PORT
      LAYER Metal2 ;
        RECT 61.720 0.000 62.120 0.400 ;
    END
  END Tile_X0Y1_NN4END[3]
  PIN Tile_X0Y1_NN4END[4]
    DIRECTION INPUT ;
    USE SIGNAL ;
    ANTENNAGATEAREA 0.734000 ;
    PORT
      LAYER Metal2 ;
        RECT 62.680 0.000 63.080 0.400 ;
    END
  END Tile_X0Y1_NN4END[4]
  PIN Tile_X0Y1_NN4END[5]
    DIRECTION INPUT ;
    USE SIGNAL ;
    ANTENNAGATEAREA 0.607100 ;
    PORT
      LAYER Metal2 ;
        RECT 63.640 0.000 64.040 0.400 ;
    END
  END Tile_X0Y1_NN4END[5]
  PIN Tile_X0Y1_NN4END[6]
    DIRECTION INPUT ;
    USE SIGNAL ;
    ANTENNAGATEAREA 0.705400 ;
    ANTENNADIFFAREA 6.046200 ;
    PORT
      LAYER Metal2 ;
        RECT 64.600 0.000 65.000 0.400 ;
    END
  END Tile_X0Y1_NN4END[6]
  PIN Tile_X0Y1_NN4END[7]
    DIRECTION INPUT ;
    USE SIGNAL ;
    ANTENNAGATEAREA 0.652600 ;
    ANTENNADIFFAREA 6.046200 ;
    PORT
      LAYER Metal2 ;
        RECT 65.560 0.000 65.960 0.400 ;
    END
  END Tile_X0Y1_NN4END[7]
  PIN Tile_X0Y1_NN4END[8]
    DIRECTION INPUT ;
    USE SIGNAL ;
    ANTENNAGATEAREA 0.180700 ;
    PORT
      LAYER Metal2 ;
        RECT 66.520 0.000 66.920 0.400 ;
    END
  END Tile_X0Y1_NN4END[8]
  PIN Tile_X0Y1_NN4END[9]
    DIRECTION INPUT ;
    USE SIGNAL ;
    ANTENNAGATEAREA 0.180700 ;
    PORT
      LAYER Metal2 ;
        RECT 67.480 0.000 67.880 0.400 ;
    END
  END Tile_X0Y1_NN4END[9]
  PIN Tile_X0Y1_S1BEG[0]
    DIRECTION OUTPUT ;
    USE SIGNAL ;
    ANTENNADIFFAREA 2.724000 ;
    PORT
      LAYER Metal2 ;
        RECT 79.960 0.000 80.360 0.400 ;
    END
  END Tile_X0Y1_S1BEG[0]
  PIN Tile_X0Y1_S1BEG[1]
    DIRECTION OUTPUT ;
    USE SIGNAL ;
    ANTENNADIFFAREA 2.724000 ;
    PORT
      LAYER Metal2 ;
        RECT 80.920 0.000 81.320 0.400 ;
    END
  END Tile_X0Y1_S1BEG[1]
  PIN Tile_X0Y1_S1BEG[2]
    DIRECTION OUTPUT ;
    USE SIGNAL ;
    ANTENNADIFFAREA 2.724000 ;
    PORT
      LAYER Metal2 ;
        RECT 81.880 0.000 82.280 0.400 ;
    END
  END Tile_X0Y1_S1BEG[2]
  PIN Tile_X0Y1_S1BEG[3]
    DIRECTION OUTPUT ;
    USE SIGNAL ;
    ANTENNADIFFAREA 2.724000 ;
    PORT
      LAYER Metal2 ;
        RECT 82.840 0.000 83.240 0.400 ;
    END
  END Tile_X0Y1_S1BEG[3]
  PIN Tile_X0Y1_S2BEG[0]
    DIRECTION OUTPUT ;
    USE SIGNAL ;
    ANTENNADIFFAREA 2.724000 ;
    PORT
      LAYER Metal2 ;
        RECT 86.680 0.000 87.080 0.400 ;
    END
  END Tile_X0Y1_S2BEG[0]
  PIN Tile_X0Y1_S2BEG[1]
    DIRECTION OUTPUT ;
    USE SIGNAL ;
    ANTENNADIFFAREA 2.724000 ;
    PORT
      LAYER Metal2 ;
        RECT 87.640 0.000 88.040 0.400 ;
    END
  END Tile_X0Y1_S2BEG[1]
  PIN Tile_X0Y1_S2BEG[2]
    DIRECTION OUTPUT ;
    USE SIGNAL ;
    ANTENNADIFFAREA 2.724000 ;
    PORT
      LAYER Metal2 ;
        RECT 88.600 0.000 89.000 0.400 ;
    END
  END Tile_X0Y1_S2BEG[2]
  PIN Tile_X0Y1_S2BEG[3]
    DIRECTION OUTPUT ;
    USE SIGNAL ;
    ANTENNADIFFAREA 2.724000 ;
    PORT
      LAYER Metal2 ;
        RECT 89.560 0.000 89.960 0.400 ;
    END
  END Tile_X0Y1_S2BEG[3]
  PIN Tile_X0Y1_S2BEG[4]
    DIRECTION OUTPUT ;
    USE SIGNAL ;
    ANTENNADIFFAREA 2.724000 ;
    PORT
      LAYER Metal2 ;
        RECT 90.520 0.000 90.920 0.400 ;
    END
  END Tile_X0Y1_S2BEG[4]
  PIN Tile_X0Y1_S2BEG[5]
    DIRECTION OUTPUT ;
    USE SIGNAL ;
    ANTENNADIFFAREA 2.724000 ;
    PORT
      LAYER Metal2 ;
        RECT 91.480 0.000 91.880 0.400 ;
    END
  END Tile_X0Y1_S2BEG[5]
  PIN Tile_X0Y1_S2BEG[6]
    DIRECTION OUTPUT ;
    USE SIGNAL ;
    ANTENNADIFFAREA 2.724000 ;
    PORT
      LAYER Metal2 ;
        RECT 92.440 0.000 92.840 0.400 ;
    END
  END Tile_X0Y1_S2BEG[6]
  PIN Tile_X0Y1_S2BEG[7]
    DIRECTION OUTPUT ;
    USE SIGNAL ;
    ANTENNADIFFAREA 2.724000 ;
    PORT
      LAYER Metal2 ;
        RECT 93.400 0.000 93.800 0.400 ;
    END
  END Tile_X0Y1_S2BEG[7]
  PIN Tile_X0Y1_S2BEGb[0]
    DIRECTION OUTPUT ;
    USE SIGNAL ;
    ANTENNADIFFAREA 2.724000 ;
    PORT
      LAYER Metal2 ;
        RECT 99.160 0.000 99.560 0.400 ;
    END
  END Tile_X0Y1_S2BEGb[0]
  PIN Tile_X0Y1_S2BEGb[1]
    DIRECTION OUTPUT ;
    USE SIGNAL ;
    ANTENNADIFFAREA 2.724000 ;
    PORT
      LAYER Metal2 ;
        RECT 100.120 0.000 100.520 0.400 ;
    END
  END Tile_X0Y1_S2BEGb[1]
  PIN Tile_X0Y1_S2BEGb[2]
    DIRECTION OUTPUT ;
    USE SIGNAL ;
    ANTENNADIFFAREA 2.724000 ;
    PORT
      LAYER Metal2 ;
        RECT 101.080 0.000 101.480 0.400 ;
    END
  END Tile_X0Y1_S2BEGb[2]
  PIN Tile_X0Y1_S2BEGb[3]
    DIRECTION OUTPUT ;
    USE SIGNAL ;
    ANTENNADIFFAREA 2.724000 ;
    PORT
      LAYER Metal2 ;
        RECT 102.040 0.000 102.440 0.400 ;
    END
  END Tile_X0Y1_S2BEGb[3]
  PIN Tile_X0Y1_S2BEGb[4]
    DIRECTION OUTPUT ;
    USE SIGNAL ;
    ANTENNADIFFAREA 2.724000 ;
    PORT
      LAYER Metal2 ;
        RECT 103.000 0.000 103.400 0.400 ;
    END
  END Tile_X0Y1_S2BEGb[4]
  PIN Tile_X0Y1_S2BEGb[5]
    DIRECTION OUTPUT ;
    USE SIGNAL ;
    ANTENNADIFFAREA 2.724000 ;
    PORT
      LAYER Metal2 ;
        RECT 103.960 0.000 104.360 0.400 ;
    END
  END Tile_X0Y1_S2BEGb[5]
  PIN Tile_X0Y1_S2BEGb[6]
    DIRECTION OUTPUT ;
    USE SIGNAL ;
    ANTENNADIFFAREA 2.724000 ;
    PORT
      LAYER Metal2 ;
        RECT 104.920 0.000 105.320 0.400 ;
    END
  END Tile_X0Y1_S2BEGb[6]
  PIN Tile_X0Y1_S2BEGb[7]
    DIRECTION OUTPUT ;
    USE SIGNAL ;
    ANTENNADIFFAREA 2.724000 ;
    PORT
      LAYER Metal2 ;
        RECT 105.880 0.000 106.280 0.400 ;
    END
  END Tile_X0Y1_S2BEGb[7]
  PIN Tile_X0Y1_S4BEG[0]
    DIRECTION OUTPUT ;
    USE SIGNAL ;
    ANTENNADIFFAREA 2.724000 ;
    PORT
      LAYER Metal2 ;
        RECT 113.560 0.000 113.960 0.400 ;
    END
  END Tile_X0Y1_S4BEG[0]
  PIN Tile_X0Y1_S4BEG[10]
    DIRECTION OUTPUT ;
    USE SIGNAL ;
    ANTENNADIFFAREA 2.724000 ;
    PORT
      LAYER Metal2 ;
        RECT 123.160 0.000 123.560 0.400 ;
    END
  END Tile_X0Y1_S4BEG[10]
  PIN Tile_X0Y1_S4BEG[11]
    DIRECTION OUTPUT ;
    USE SIGNAL ;
    ANTENNADIFFAREA 2.724000 ;
    PORT
      LAYER Metal2 ;
        RECT 124.120 0.000 124.520 0.400 ;
    END
  END Tile_X0Y1_S4BEG[11]
  PIN Tile_X0Y1_S4BEG[12]
    DIRECTION OUTPUT ;
    USE SIGNAL ;
    ANTENNADIFFAREA 2.724000 ;
    PORT
      LAYER Metal2 ;
        RECT 125.080 0.000 125.480 0.400 ;
    END
  END Tile_X0Y1_S4BEG[12]
  PIN Tile_X0Y1_S4BEG[13]
    DIRECTION OUTPUT ;
    USE SIGNAL ;
    ANTENNADIFFAREA 2.724000 ;
    PORT
      LAYER Metal2 ;
        RECT 126.040 0.000 126.440 0.400 ;
    END
  END Tile_X0Y1_S4BEG[13]
  PIN Tile_X0Y1_S4BEG[14]
    DIRECTION OUTPUT ;
    USE SIGNAL ;
    ANTENNADIFFAREA 2.724000 ;
    PORT
      LAYER Metal2 ;
        RECT 127.000 0.000 127.400 0.400 ;
    END
  END Tile_X0Y1_S4BEG[14]
  PIN Tile_X0Y1_S4BEG[15]
    DIRECTION OUTPUT ;
    USE SIGNAL ;
    ANTENNADIFFAREA 2.724000 ;
    PORT
      LAYER Metal2 ;
        RECT 127.960 0.000 128.360 0.400 ;
    END
  END Tile_X0Y1_S4BEG[15]
  PIN Tile_X0Y1_S4BEG[1]
    DIRECTION OUTPUT ;
    USE SIGNAL ;
    ANTENNADIFFAREA 2.724000 ;
    PORT
      LAYER Metal2 ;
        RECT 114.520 0.000 114.920 0.400 ;
    END
  END Tile_X0Y1_S4BEG[1]
  PIN Tile_X0Y1_S4BEG[2]
    DIRECTION OUTPUT ;
    USE SIGNAL ;
    ANTENNADIFFAREA 2.724000 ;
    PORT
      LAYER Metal2 ;
        RECT 115.480 0.000 115.880 0.400 ;
    END
  END Tile_X0Y1_S4BEG[2]
  PIN Tile_X0Y1_S4BEG[3]
    DIRECTION OUTPUT ;
    USE SIGNAL ;
    ANTENNADIFFAREA 2.724000 ;
    PORT
      LAYER Metal2 ;
        RECT 116.440 0.000 116.840 0.400 ;
    END
  END Tile_X0Y1_S4BEG[3]
  PIN Tile_X0Y1_S4BEG[4]
    DIRECTION OUTPUT ;
    USE SIGNAL ;
    ANTENNADIFFAREA 2.724000 ;
    PORT
      LAYER Metal2 ;
        RECT 117.400 0.000 117.800 0.400 ;
    END
  END Tile_X0Y1_S4BEG[4]
  PIN Tile_X0Y1_S4BEG[5]
    DIRECTION OUTPUT ;
    USE SIGNAL ;
    ANTENNADIFFAREA 2.724000 ;
    PORT
      LAYER Metal2 ;
        RECT 118.360 0.000 118.760 0.400 ;
    END
  END Tile_X0Y1_S4BEG[5]
  PIN Tile_X0Y1_S4BEG[6]
    DIRECTION OUTPUT ;
    USE SIGNAL ;
    ANTENNADIFFAREA 2.724000 ;
    PORT
      LAYER Metal2 ;
        RECT 119.320 0.000 119.720 0.400 ;
    END
  END Tile_X0Y1_S4BEG[6]
  PIN Tile_X0Y1_S4BEG[7]
    DIRECTION OUTPUT ;
    USE SIGNAL ;
    ANTENNADIFFAREA 2.724000 ;
    PORT
      LAYER Metal2 ;
        RECT 120.280 0.000 120.680 0.400 ;
    END
  END Tile_X0Y1_S4BEG[7]
  PIN Tile_X0Y1_S4BEG[8]
    DIRECTION OUTPUT ;
    USE SIGNAL ;
    ANTENNADIFFAREA 2.724000 ;
    PORT
      LAYER Metal2 ;
        RECT 121.240 0.000 121.640 0.400 ;
    END
  END Tile_X0Y1_S4BEG[8]
  PIN Tile_X0Y1_S4BEG[9]
    DIRECTION OUTPUT ;
    USE SIGNAL ;
    ANTENNADIFFAREA 2.724000 ;
    PORT
      LAYER Metal2 ;
        RECT 122.200 0.000 122.600 0.400 ;
    END
  END Tile_X0Y1_S4BEG[9]
  PIN Tile_X0Y1_SS4BEG[0]
    DIRECTION OUTPUT ;
    USE SIGNAL ;
    ANTENNADIFFAREA 2.724000 ;
    PORT
      LAYER Metal2 ;
        RECT 138.520 0.000 138.920 0.400 ;
    END
  END Tile_X0Y1_SS4BEG[0]
  PIN Tile_X0Y1_SS4BEG[10]
    DIRECTION OUTPUT ;
    USE SIGNAL ;
    ANTENNADIFFAREA 2.724000 ;
    PORT
      LAYER Metal2 ;
        RECT 148.120 0.000 148.520 0.400 ;
    END
  END Tile_X0Y1_SS4BEG[10]
  PIN Tile_X0Y1_SS4BEG[11]
    DIRECTION OUTPUT ;
    USE SIGNAL ;
    ANTENNADIFFAREA 2.724000 ;
    PORT
      LAYER Metal2 ;
        RECT 149.080 0.000 149.480 0.400 ;
    END
  END Tile_X0Y1_SS4BEG[11]
  PIN Tile_X0Y1_SS4BEG[12]
    DIRECTION OUTPUT ;
    USE SIGNAL ;
    ANTENNADIFFAREA 2.724000 ;
    PORT
      LAYER Metal2 ;
        RECT 150.040 0.000 150.440 0.400 ;
    END
  END Tile_X0Y1_SS4BEG[12]
  PIN Tile_X0Y1_SS4BEG[13]
    DIRECTION OUTPUT ;
    USE SIGNAL ;
    ANTENNADIFFAREA 2.724000 ;
    PORT
      LAYER Metal2 ;
        RECT 151.000 0.000 151.400 0.400 ;
    END
  END Tile_X0Y1_SS4BEG[13]
  PIN Tile_X0Y1_SS4BEG[14]
    DIRECTION OUTPUT ;
    USE SIGNAL ;
    ANTENNADIFFAREA 2.724000 ;
    PORT
      LAYER Metal2 ;
        RECT 151.960 0.000 152.360 0.400 ;
    END
  END Tile_X0Y1_SS4BEG[14]
  PIN Tile_X0Y1_SS4BEG[15]
    DIRECTION OUTPUT ;
    USE SIGNAL ;
    ANTENNADIFFAREA 2.724000 ;
    PORT
      LAYER Metal2 ;
        RECT 152.920 0.000 153.320 0.400 ;
    END
  END Tile_X0Y1_SS4BEG[15]
  PIN Tile_X0Y1_SS4BEG[1]
    DIRECTION OUTPUT ;
    USE SIGNAL ;
    ANTENNADIFFAREA 2.724000 ;
    PORT
      LAYER Metal2 ;
        RECT 139.480 0.000 139.880 0.400 ;
    END
  END Tile_X0Y1_SS4BEG[1]
  PIN Tile_X0Y1_SS4BEG[2]
    DIRECTION OUTPUT ;
    USE SIGNAL ;
    ANTENNADIFFAREA 2.724000 ;
    PORT
      LAYER Metal2 ;
        RECT 140.440 0.000 140.840 0.400 ;
    END
  END Tile_X0Y1_SS4BEG[2]
  PIN Tile_X0Y1_SS4BEG[3]
    DIRECTION OUTPUT ;
    USE SIGNAL ;
    ANTENNADIFFAREA 2.724000 ;
    PORT
      LAYER Metal2 ;
        RECT 141.400 0.000 141.800 0.400 ;
    END
  END Tile_X0Y1_SS4BEG[3]
  PIN Tile_X0Y1_SS4BEG[4]
    DIRECTION OUTPUT ;
    USE SIGNAL ;
    ANTENNADIFFAREA 2.724000 ;
    PORT
      LAYER Metal2 ;
        RECT 142.360 0.000 142.760 0.400 ;
    END
  END Tile_X0Y1_SS4BEG[4]
  PIN Tile_X0Y1_SS4BEG[5]
    DIRECTION OUTPUT ;
    USE SIGNAL ;
    ANTENNADIFFAREA 2.724000 ;
    PORT
      LAYER Metal2 ;
        RECT 143.320 0.000 143.720 0.400 ;
    END
  END Tile_X0Y1_SS4BEG[5]
  PIN Tile_X0Y1_SS4BEG[6]
    DIRECTION OUTPUT ;
    USE SIGNAL ;
    ANTENNADIFFAREA 2.724000 ;
    PORT
      LAYER Metal2 ;
        RECT 144.280 0.000 144.680 0.400 ;
    END
  END Tile_X0Y1_SS4BEG[6]
  PIN Tile_X0Y1_SS4BEG[7]
    DIRECTION OUTPUT ;
    USE SIGNAL ;
    ANTENNADIFFAREA 2.724000 ;
    PORT
      LAYER Metal2 ;
        RECT 145.240 0.000 145.640 0.400 ;
    END
  END Tile_X0Y1_SS4BEG[7]
  PIN Tile_X0Y1_SS4BEG[8]
    DIRECTION OUTPUT ;
    USE SIGNAL ;
    ANTENNADIFFAREA 2.724000 ;
    PORT
      LAYER Metal2 ;
        RECT 146.200 0.000 146.600 0.400 ;
    END
  END Tile_X0Y1_SS4BEG[8]
  PIN Tile_X0Y1_SS4BEG[9]
    DIRECTION OUTPUT ;
    USE SIGNAL ;
    ANTENNADIFFAREA 2.724000 ;
    PORT
      LAYER Metal2 ;
        RECT 147.160 0.000 147.560 0.400 ;
    END
  END Tile_X0Y1_SS4BEG[9]
  PIN Tile_X0Y1_UserCLK
    DIRECTION INPUT ;
    USE SIGNAL ;
    ANTENNAGATEAREA 13.721499 ;
    PORT
      LAYER Metal3 ;
        RECT 0.000 160.660 0.400 161.060 ;
    END
  END Tile_X0Y1_UserCLK
  PIN Tile_X0Y1_UserCLKo
    DIRECTION OUTPUT ;
    USE SIGNAL ;
    ANTENNADIFFAREA 2.724000 ;
    PORT
      LAYER Metal3 ;
        RECT 188.240 160.660 188.640 161.060 ;
    END
  END Tile_X0Y1_UserCLKo
  PIN Tile_X0Y1_W1BEG[0]
    DIRECTION OUTPUT ;
    USE SIGNAL ;
    ANTENNADIFFAREA 2.724000 ;
    PORT
      LAYER Metal3 ;
        RECT 0.000 80.020 0.400 80.420 ;
    END
  END Tile_X0Y1_W1BEG[0]
  PIN Tile_X0Y1_W1BEG[1]
    DIRECTION OUTPUT ;
    USE SIGNAL ;
    ANTENNADIFFAREA 2.724000 ;
    PORT
      LAYER Metal3 ;
        RECT 0.000 81.700 0.400 82.100 ;
    END
  END Tile_X0Y1_W1BEG[1]
  PIN Tile_X0Y1_W1BEG[2]
    DIRECTION OUTPUT ;
    USE SIGNAL ;
    ANTENNADIFFAREA 2.724000 ;
    PORT
      LAYER Metal3 ;
        RECT 0.000 83.380 0.400 83.780 ;
    END
  END Tile_X0Y1_W1BEG[2]
  PIN Tile_X0Y1_W1BEG[3]
    DIRECTION OUTPUT ;
    USE SIGNAL ;
    ANTENNADIFFAREA 2.724000 ;
    PORT
      LAYER Metal3 ;
        RECT 0.000 85.060 0.400 85.460 ;
    END
  END Tile_X0Y1_W1BEG[3]
  PIN Tile_X0Y1_W1END[0]
    DIRECTION INPUT ;
    USE SIGNAL ;
    ANTENNAGATEAREA 1.615400 ;
    PORT
      LAYER Metal3 ;
        RECT 188.240 80.020 188.640 80.420 ;
    END
  END Tile_X0Y1_W1END[0]
  PIN Tile_X0Y1_W1END[1]
    DIRECTION INPUT ;
    USE SIGNAL ;
    ANTENNAGATEAREA 1.094600 ;
    PORT
      LAYER Metal3 ;
        RECT 188.240 81.700 188.640 82.100 ;
    END
  END Tile_X0Y1_W1END[1]
  PIN Tile_X0Y1_W1END[2]
    DIRECTION INPUT ;
    USE SIGNAL ;
    ANTENNAGATEAREA 1.762800 ;
    PORT
      LAYER Metal3 ;
        RECT 188.240 83.380 188.640 83.780 ;
    END
  END Tile_X0Y1_W1END[2]
  PIN Tile_X0Y1_W1END[3]
    DIRECTION INPUT ;
    USE SIGNAL ;
    ANTENNAGATEAREA 1.586800 ;
    PORT
      LAYER Metal3 ;
        RECT 188.240 85.060 188.640 85.460 ;
    END
  END Tile_X0Y1_W1END[3]
  PIN Tile_X0Y1_W2BEG[0]
    DIRECTION OUTPUT ;
    USE SIGNAL ;
    ANTENNADIFFAREA 2.724000 ;
    PORT
      LAYER Metal3 ;
        RECT 0.000 86.740 0.400 87.140 ;
    END
  END Tile_X0Y1_W2BEG[0]
  PIN Tile_X0Y1_W2BEG[1]
    DIRECTION OUTPUT ;
    USE SIGNAL ;
    ANTENNADIFFAREA 2.724000 ;
    PORT
      LAYER Metal3 ;
        RECT 0.000 88.420 0.400 88.820 ;
    END
  END Tile_X0Y1_W2BEG[1]
  PIN Tile_X0Y1_W2BEG[2]
    DIRECTION OUTPUT ;
    USE SIGNAL ;
    ANTENNADIFFAREA 2.724000 ;
    PORT
      LAYER Metal3 ;
        RECT 0.000 90.100 0.400 90.500 ;
    END
  END Tile_X0Y1_W2BEG[2]
  PIN Tile_X0Y1_W2BEG[3]
    DIRECTION OUTPUT ;
    USE SIGNAL ;
    ANTENNADIFFAREA 2.724000 ;
    PORT
      LAYER Metal3 ;
        RECT 0.000 91.780 0.400 92.180 ;
    END
  END Tile_X0Y1_W2BEG[3]
  PIN Tile_X0Y1_W2BEG[4]
    DIRECTION OUTPUT ;
    USE SIGNAL ;
    ANTENNADIFFAREA 2.724000 ;
    PORT
      LAYER Metal3 ;
        RECT 0.000 93.460 0.400 93.860 ;
    END
  END Tile_X0Y1_W2BEG[4]
  PIN Tile_X0Y1_W2BEG[5]
    DIRECTION OUTPUT ;
    USE SIGNAL ;
    ANTENNADIFFAREA 2.724000 ;
    PORT
      LAYER Metal3 ;
        RECT 0.000 95.140 0.400 95.540 ;
    END
  END Tile_X0Y1_W2BEG[5]
  PIN Tile_X0Y1_W2BEG[6]
    DIRECTION OUTPUT ;
    USE SIGNAL ;
    ANTENNADIFFAREA 2.724000 ;
    PORT
      LAYER Metal3 ;
        RECT 0.000 96.820 0.400 97.220 ;
    END
  END Tile_X0Y1_W2BEG[6]
  PIN Tile_X0Y1_W2BEG[7]
    DIRECTION OUTPUT ;
    USE SIGNAL ;
    ANTENNADIFFAREA 2.724000 ;
    PORT
      LAYER Metal3 ;
        RECT 0.000 98.500 0.400 98.900 ;
    END
  END Tile_X0Y1_W2BEG[7]
  PIN Tile_X0Y1_W2BEGb[0]
    DIRECTION OUTPUT ;
    USE SIGNAL ;
    ANTENNADIFFAREA 2.724000 ;
    PORT
      LAYER Metal3 ;
        RECT 0.000 100.180 0.400 100.580 ;
    END
  END Tile_X0Y1_W2BEGb[0]
  PIN Tile_X0Y1_W2BEGb[1]
    DIRECTION OUTPUT ;
    USE SIGNAL ;
    ANTENNADIFFAREA 2.724000 ;
    PORT
      LAYER Metal3 ;
        RECT 0.000 101.860 0.400 102.260 ;
    END
  END Tile_X0Y1_W2BEGb[1]
  PIN Tile_X0Y1_W2BEGb[2]
    DIRECTION OUTPUT ;
    USE SIGNAL ;
    ANTENNADIFFAREA 2.724000 ;
    PORT
      LAYER Metal3 ;
        RECT 0.000 103.540 0.400 103.940 ;
    END
  END Tile_X0Y1_W2BEGb[2]
  PIN Tile_X0Y1_W2BEGb[3]
    DIRECTION OUTPUT ;
    USE SIGNAL ;
    ANTENNADIFFAREA 2.724000 ;
    PORT
      LAYER Metal3 ;
        RECT 0.000 105.220 0.400 105.620 ;
    END
  END Tile_X0Y1_W2BEGb[3]
  PIN Tile_X0Y1_W2BEGb[4]
    DIRECTION OUTPUT ;
    USE SIGNAL ;
    ANTENNADIFFAREA 2.724000 ;
    PORT
      LAYER Metal3 ;
        RECT 0.000 106.900 0.400 107.300 ;
    END
  END Tile_X0Y1_W2BEGb[4]
  PIN Tile_X0Y1_W2BEGb[5]
    DIRECTION OUTPUT ;
    USE SIGNAL ;
    ANTENNADIFFAREA 2.724000 ;
    PORT
      LAYER Metal3 ;
        RECT 0.000 108.580 0.400 108.980 ;
    END
  END Tile_X0Y1_W2BEGb[5]
  PIN Tile_X0Y1_W2BEGb[6]
    DIRECTION OUTPUT ;
    USE SIGNAL ;
    ANTENNADIFFAREA 2.724000 ;
    PORT
      LAYER Metal3 ;
        RECT 0.000 110.260 0.400 110.660 ;
    END
  END Tile_X0Y1_W2BEGb[6]
  PIN Tile_X0Y1_W2BEGb[7]
    DIRECTION OUTPUT ;
    USE SIGNAL ;
    ANTENNADIFFAREA 2.724000 ;
    PORT
      LAYER Metal3 ;
        RECT 0.000 111.940 0.400 112.340 ;
    END
  END Tile_X0Y1_W2BEGb[7]
  PIN Tile_X0Y1_W2END[0]
    DIRECTION INPUT ;
    USE SIGNAL ;
    ANTENNAGATEAREA 0.672900 ;
    ANTENNADIFFAREA 18.138599 ;
    PORT
      LAYER Metal3 ;
        RECT 188.240 100.180 188.640 100.580 ;
    END
  END Tile_X0Y1_W2END[0]
  PIN Tile_X0Y1_W2END[1]
    DIRECTION INPUT ;
    USE SIGNAL ;
    ANTENNAGATEAREA 1.318200 ;
    PORT
      LAYER Metal3 ;
        RECT 188.240 101.860 188.640 102.260 ;
    END
  END Tile_X0Y1_W2END[1]
  PIN Tile_X0Y1_W2END[2]
    DIRECTION INPUT ;
    USE SIGNAL ;
    ANTENNAGATEAREA 1.406900 ;
    PORT
      LAYER Metal3 ;
        RECT 188.240 103.540 188.640 103.940 ;
    END
  END Tile_X0Y1_W2END[2]
  PIN Tile_X0Y1_W2END[3]
    DIRECTION INPUT ;
    USE SIGNAL ;
    ANTENNAGATEAREA 1.498900 ;
    PORT
      LAYER Metal3 ;
        RECT 188.240 105.220 188.640 105.620 ;
    END
  END Tile_X0Y1_W2END[3]
  PIN Tile_X0Y1_W2END[4]
    DIRECTION INPUT ;
    USE SIGNAL ;
    ANTENNAGATEAREA 1.806500 ;
    PORT
      LAYER Metal3 ;
        RECT 188.240 106.900 188.640 107.300 ;
    END
  END Tile_X0Y1_W2END[4]
  PIN Tile_X0Y1_W2END[5]
    DIRECTION INPUT ;
    USE SIGNAL ;
    ANTENNAGATEAREA 0.426400 ;
    PORT
      LAYER Metal3 ;
        RECT 188.240 108.580 188.640 108.980 ;
    END
  END Tile_X0Y1_W2END[5]
  PIN Tile_X0Y1_W2END[6]
    DIRECTION INPUT ;
    USE SIGNAL ;
    ANTENNAGATEAREA 0.426400 ;
    PORT
      LAYER Metal3 ;
        RECT 188.240 110.260 188.640 110.660 ;
    END
  END Tile_X0Y1_W2END[6]
  PIN Tile_X0Y1_W2END[7]
    DIRECTION INPUT ;
    USE SIGNAL ;
    ANTENNAGATEAREA 1.062100 ;
    PORT
      LAYER Metal3 ;
        RECT 188.240 111.940 188.640 112.340 ;
    END
  END Tile_X0Y1_W2END[7]
  PIN Tile_X0Y1_W2MID[0]
    DIRECTION INPUT ;
    USE SIGNAL ;
    ANTENNAGATEAREA 1.230900 ;
    PORT
      LAYER Metal3 ;
        RECT 188.240 86.740 188.640 87.140 ;
    END
  END Tile_X0Y1_W2MID[0]
  PIN Tile_X0Y1_W2MID[1]
    DIRECTION INPUT ;
    USE SIGNAL ;
    ANTENNAGATEAREA 1.332500 ;
    PORT
      LAYER Metal3 ;
        RECT 188.240 88.420 188.640 88.820 ;
    END
  END Tile_X0Y1_W2MID[1]
  PIN Tile_X0Y1_W2MID[2]
    DIRECTION INPUT ;
    USE SIGNAL ;
    ANTENNAGATEAREA 0.919400 ;
    PORT
      LAYER Metal3 ;
        RECT 188.240 90.100 188.640 90.500 ;
    END
  END Tile_X0Y1_W2MID[2]
  PIN Tile_X0Y1_W2MID[3]
    DIRECTION INPUT ;
    USE SIGNAL ;
    ANTENNAGATEAREA 0.848900 ;
    ANTENNADIFFAREA 32.246399 ;
    PORT
      LAYER Metal3 ;
        RECT 188.240 91.780 188.640 92.180 ;
    END
  END Tile_X0Y1_W2MID[3]
  PIN Tile_X0Y1_W2MID[4]
    DIRECTION INPUT ;
    USE SIGNAL ;
    ANTENNAGATEAREA 0.787800 ;
    PORT
      LAYER Metal3 ;
        RECT 188.240 93.460 188.640 93.860 ;
    END
  END Tile_X0Y1_W2MID[4]
  PIN Tile_X0Y1_W2MID[5]
    DIRECTION INPUT ;
    USE SIGNAL ;
    ANTENNAGATEAREA 1.119300 ;
    PORT
      LAYER Metal3 ;
        RECT 188.240 95.140 188.640 95.540 ;
    END
  END Tile_X0Y1_W2MID[5]
  PIN Tile_X0Y1_W2MID[6]
    DIRECTION INPUT ;
    USE SIGNAL ;
    ANTENNAGATEAREA 0.951900 ;
    ANTENNADIFFAREA 32.246399 ;
    PORT
      LAYER Metal3 ;
        RECT 188.240 96.820 188.640 97.220 ;
    END
  END Tile_X0Y1_W2MID[6]
  PIN Tile_X0Y1_W2MID[7]
    DIRECTION INPUT ;
    USE SIGNAL ;
    ANTENNAGATEAREA 0.701500 ;
    ANTENNADIFFAREA 18.138599 ;
    PORT
      LAYER Metal3 ;
        RECT 188.240 98.500 188.640 98.900 ;
    END
  END Tile_X0Y1_W2MID[7]
  PIN Tile_X0Y1_W6BEG[0]
    DIRECTION OUTPUT ;
    USE SIGNAL ;
    ANTENNADIFFAREA 2.724000 ;
    PORT
      LAYER Metal3 ;
        RECT 0.000 140.500 0.400 140.900 ;
    END
  END Tile_X0Y1_W6BEG[0]
  PIN Tile_X0Y1_W6BEG[10]
    DIRECTION OUTPUT ;
    USE SIGNAL ;
    ANTENNADIFFAREA 2.724000 ;
    PORT
      LAYER Metal3 ;
        RECT 0.000 157.300 0.400 157.700 ;
    END
  END Tile_X0Y1_W6BEG[10]
  PIN Tile_X0Y1_W6BEG[11]
    DIRECTION OUTPUT ;
    USE SIGNAL ;
    ANTENNADIFFAREA 2.724000 ;
    PORT
      LAYER Metal3 ;
        RECT 0.000 158.980 0.400 159.380 ;
    END
  END Tile_X0Y1_W6BEG[11]
  PIN Tile_X0Y1_W6BEG[1]
    DIRECTION OUTPUT ;
    USE SIGNAL ;
    ANTENNADIFFAREA 2.724000 ;
    PORT
      LAYER Metal3 ;
        RECT 0.000 142.180 0.400 142.580 ;
    END
  END Tile_X0Y1_W6BEG[1]
  PIN Tile_X0Y1_W6BEG[2]
    DIRECTION OUTPUT ;
    USE SIGNAL ;
    ANTENNADIFFAREA 2.724000 ;
    PORT
      LAYER Metal3 ;
        RECT 0.000 143.860 0.400 144.260 ;
    END
  END Tile_X0Y1_W6BEG[2]
  PIN Tile_X0Y1_W6BEG[3]
    DIRECTION OUTPUT ;
    USE SIGNAL ;
    ANTENNADIFFAREA 2.724000 ;
    PORT
      LAYER Metal3 ;
        RECT 0.000 145.540 0.400 145.940 ;
    END
  END Tile_X0Y1_W6BEG[3]
  PIN Tile_X0Y1_W6BEG[4]
    DIRECTION OUTPUT ;
    USE SIGNAL ;
    ANTENNADIFFAREA 2.724000 ;
    PORT
      LAYER Metal3 ;
        RECT 0.000 147.220 0.400 147.620 ;
    END
  END Tile_X0Y1_W6BEG[4]
  PIN Tile_X0Y1_W6BEG[5]
    DIRECTION OUTPUT ;
    USE SIGNAL ;
    ANTENNADIFFAREA 2.724000 ;
    PORT
      LAYER Metal3 ;
        RECT 0.000 148.900 0.400 149.300 ;
    END
  END Tile_X0Y1_W6BEG[5]
  PIN Tile_X0Y1_W6BEG[6]
    DIRECTION OUTPUT ;
    USE SIGNAL ;
    ANTENNADIFFAREA 2.724000 ;
    PORT
      LAYER Metal3 ;
        RECT 0.000 150.580 0.400 150.980 ;
    END
  END Tile_X0Y1_W6BEG[6]
  PIN Tile_X0Y1_W6BEG[7]
    DIRECTION OUTPUT ;
    USE SIGNAL ;
    ANTENNADIFFAREA 2.724000 ;
    PORT
      LAYER Metal3 ;
        RECT 0.000 152.260 0.400 152.660 ;
    END
  END Tile_X0Y1_W6BEG[7]
  PIN Tile_X0Y1_W6BEG[8]
    DIRECTION OUTPUT ;
    USE SIGNAL ;
    ANTENNADIFFAREA 2.724000 ;
    PORT
      LAYER Metal3 ;
        RECT 0.000 153.940 0.400 154.340 ;
    END
  END Tile_X0Y1_W6BEG[8]
  PIN Tile_X0Y1_W6BEG[9]
    DIRECTION OUTPUT ;
    USE SIGNAL ;
    ANTENNADIFFAREA 2.724000 ;
    PORT
      LAYER Metal3 ;
        RECT 0.000 155.620 0.400 156.020 ;
    END
  END Tile_X0Y1_W6BEG[9]
  PIN Tile_X0Y1_W6END[0]
    DIRECTION INPUT ;
    USE SIGNAL ;
    ANTENNAGATEAREA 1.588600 ;
    PORT
      LAYER Metal3 ;
        RECT 188.240 140.500 188.640 140.900 ;
    END
  END Tile_X0Y1_W6END[0]
  PIN Tile_X0Y1_W6END[10]
    DIRECTION INPUT ;
    USE SIGNAL ;
    ANTENNAGATEAREA 0.180700 ;
    PORT
      LAYER Metal3 ;
        RECT 188.240 157.300 188.640 157.700 ;
    END
  END Tile_X0Y1_W6END[10]
  PIN Tile_X0Y1_W6END[11]
    DIRECTION INPUT ;
    USE SIGNAL ;
    ANTENNAGATEAREA 0.180700 ;
    PORT
      LAYER Metal3 ;
        RECT 188.240 158.980 188.640 159.380 ;
    END
  END Tile_X0Y1_W6END[11]
  PIN Tile_X0Y1_W6END[1]
    DIRECTION INPUT ;
    USE SIGNAL ;
    ANTENNAGATEAREA 2.212600 ;
    PORT
      LAYER Metal3 ;
        RECT 188.240 142.180 188.640 142.580 ;
    END
  END Tile_X0Y1_W6END[1]
  PIN Tile_X0Y1_W6END[2]
    DIRECTION INPUT ;
    USE SIGNAL ;
    ANTENNAGATEAREA 0.180700 ;
    PORT
      LAYER Metal3 ;
        RECT 188.240 143.860 188.640 144.260 ;
    END
  END Tile_X0Y1_W6END[2]
  PIN Tile_X0Y1_W6END[3]
    DIRECTION INPUT ;
    USE SIGNAL ;
    ANTENNAGATEAREA 0.180700 ;
    PORT
      LAYER Metal3 ;
        RECT 188.240 145.540 188.640 145.940 ;
    END
  END Tile_X0Y1_W6END[3]
  PIN Tile_X0Y1_W6END[4]
    DIRECTION INPUT ;
    USE SIGNAL ;
    ANTENNAGATEAREA 0.180700 ;
    PORT
      LAYER Metal3 ;
        RECT 188.240 147.220 188.640 147.620 ;
    END
  END Tile_X0Y1_W6END[4]
  PIN Tile_X0Y1_W6END[5]
    DIRECTION INPUT ;
    USE SIGNAL ;
    ANTENNAGATEAREA 0.180700 ;
    PORT
      LAYER Metal3 ;
        RECT 188.240 148.900 188.640 149.300 ;
    END
  END Tile_X0Y1_W6END[5]
  PIN Tile_X0Y1_W6END[6]
    DIRECTION INPUT ;
    USE SIGNAL ;
    ANTENNAGATEAREA 0.180700 ;
    PORT
      LAYER Metal3 ;
        RECT 188.240 150.580 188.640 150.980 ;
    END
  END Tile_X0Y1_W6END[6]
  PIN Tile_X0Y1_W6END[7]
    DIRECTION INPUT ;
    USE SIGNAL ;
    ANTENNAGATEAREA 0.180700 ;
    PORT
      LAYER Metal3 ;
        RECT 188.240 152.260 188.640 152.660 ;
    END
  END Tile_X0Y1_W6END[7]
  PIN Tile_X0Y1_W6END[8]
    DIRECTION INPUT ;
    USE SIGNAL ;
    ANTENNAGATEAREA 0.180700 ;
    PORT
      LAYER Metal3 ;
        RECT 188.240 153.940 188.640 154.340 ;
    END
  END Tile_X0Y1_W6END[8]
  PIN Tile_X0Y1_W6END[9]
    DIRECTION INPUT ;
    USE SIGNAL ;
    ANTENNAGATEAREA 0.180700 ;
    PORT
      LAYER Metal3 ;
        RECT 188.240 155.620 188.640 156.020 ;
    END
  END Tile_X0Y1_W6END[9]
  PIN Tile_X0Y1_WW4BEG[0]
    DIRECTION OUTPUT ;
    USE SIGNAL ;
    ANTENNADIFFAREA 2.724000 ;
    PORT
      LAYER Metal3 ;
        RECT 0.000 113.620 0.400 114.020 ;
    END
  END Tile_X0Y1_WW4BEG[0]
  PIN Tile_X0Y1_WW4BEG[10]
    DIRECTION OUTPUT ;
    USE SIGNAL ;
    ANTENNADIFFAREA 2.724000 ;
    PORT
      LAYER Metal3 ;
        RECT 0.000 130.420 0.400 130.820 ;
    END
  END Tile_X0Y1_WW4BEG[10]
  PIN Tile_X0Y1_WW4BEG[11]
    DIRECTION OUTPUT ;
    USE SIGNAL ;
    ANTENNADIFFAREA 2.724000 ;
    PORT
      LAYER Metal3 ;
        RECT 0.000 132.100 0.400 132.500 ;
    END
  END Tile_X0Y1_WW4BEG[11]
  PIN Tile_X0Y1_WW4BEG[12]
    DIRECTION OUTPUT ;
    USE SIGNAL ;
    ANTENNADIFFAREA 2.724000 ;
    PORT
      LAYER Metal3 ;
        RECT 0.000 133.780 0.400 134.180 ;
    END
  END Tile_X0Y1_WW4BEG[12]
  PIN Tile_X0Y1_WW4BEG[13]
    DIRECTION OUTPUT ;
    USE SIGNAL ;
    ANTENNADIFFAREA 2.724000 ;
    PORT
      LAYER Metal3 ;
        RECT 0.000 135.460 0.400 135.860 ;
    END
  END Tile_X0Y1_WW4BEG[13]
  PIN Tile_X0Y1_WW4BEG[14]
    DIRECTION OUTPUT ;
    USE SIGNAL ;
    ANTENNADIFFAREA 2.724000 ;
    PORT
      LAYER Metal3 ;
        RECT 0.000 137.140 0.400 137.540 ;
    END
  END Tile_X0Y1_WW4BEG[14]
  PIN Tile_X0Y1_WW4BEG[15]
    DIRECTION OUTPUT ;
    USE SIGNAL ;
    ANTENNADIFFAREA 2.724000 ;
    PORT
      LAYER Metal3 ;
        RECT 0.000 138.820 0.400 139.220 ;
    END
  END Tile_X0Y1_WW4BEG[15]
  PIN Tile_X0Y1_WW4BEG[1]
    DIRECTION OUTPUT ;
    USE SIGNAL ;
    ANTENNADIFFAREA 2.724000 ;
    PORT
      LAYER Metal3 ;
        RECT 0.000 115.300 0.400 115.700 ;
    END
  END Tile_X0Y1_WW4BEG[1]
  PIN Tile_X0Y1_WW4BEG[2]
    DIRECTION OUTPUT ;
    USE SIGNAL ;
    ANTENNADIFFAREA 2.724000 ;
    PORT
      LAYER Metal3 ;
        RECT 0.000 116.980 0.400 117.380 ;
    END
  END Tile_X0Y1_WW4BEG[2]
  PIN Tile_X0Y1_WW4BEG[3]
    DIRECTION OUTPUT ;
    USE SIGNAL ;
    ANTENNADIFFAREA 2.724000 ;
    PORT
      LAYER Metal3 ;
        RECT 0.000 118.660 0.400 119.060 ;
    END
  END Tile_X0Y1_WW4BEG[3]
  PIN Tile_X0Y1_WW4BEG[4]
    DIRECTION OUTPUT ;
    USE SIGNAL ;
    ANTENNADIFFAREA 2.724000 ;
    PORT
      LAYER Metal3 ;
        RECT 0.000 120.340 0.400 120.740 ;
    END
  END Tile_X0Y1_WW4BEG[4]
  PIN Tile_X0Y1_WW4BEG[5]
    DIRECTION OUTPUT ;
    USE SIGNAL ;
    ANTENNADIFFAREA 2.724000 ;
    PORT
      LAYER Metal3 ;
        RECT 0.000 122.020 0.400 122.420 ;
    END
  END Tile_X0Y1_WW4BEG[5]
  PIN Tile_X0Y1_WW4BEG[6]
    DIRECTION OUTPUT ;
    USE SIGNAL ;
    ANTENNADIFFAREA 2.724000 ;
    PORT
      LAYER Metal3 ;
        RECT 0.000 123.700 0.400 124.100 ;
    END
  END Tile_X0Y1_WW4BEG[6]
  PIN Tile_X0Y1_WW4BEG[7]
    DIRECTION OUTPUT ;
    USE SIGNAL ;
    ANTENNADIFFAREA 2.724000 ;
    PORT
      LAYER Metal3 ;
        RECT 0.000 125.380 0.400 125.780 ;
    END
  END Tile_X0Y1_WW4BEG[7]
  PIN Tile_X0Y1_WW4BEG[8]
    DIRECTION OUTPUT ;
    USE SIGNAL ;
    ANTENNADIFFAREA 2.724000 ;
    PORT
      LAYER Metal3 ;
        RECT 0.000 127.060 0.400 127.460 ;
    END
  END Tile_X0Y1_WW4BEG[8]
  PIN Tile_X0Y1_WW4BEG[9]
    DIRECTION OUTPUT ;
    USE SIGNAL ;
    ANTENNADIFFAREA 2.724000 ;
    PORT
      LAYER Metal3 ;
        RECT 0.000 128.740 0.400 129.140 ;
    END
  END Tile_X0Y1_WW4BEG[9]
  PIN Tile_X0Y1_WW4END[0]
    DIRECTION INPUT ;
    USE SIGNAL ;
    ANTENNAGATEAREA 0.668200 ;
    PORT
      LAYER Metal3 ;
        RECT 188.240 113.620 188.640 114.020 ;
    END
  END Tile_X0Y1_WW4END[0]
  PIN Tile_X0Y1_WW4END[10]
    DIRECTION INPUT ;
    USE SIGNAL ;
    ANTENNAGATEAREA 0.180700 ;
    PORT
      LAYER Metal3 ;
        RECT 188.240 130.420 188.640 130.820 ;
    END
  END Tile_X0Y1_WW4END[10]
  PIN Tile_X0Y1_WW4END[11]
    DIRECTION INPUT ;
    USE SIGNAL ;
    ANTENNAGATEAREA 0.180700 ;
    PORT
      LAYER Metal3 ;
        RECT 188.240 132.100 188.640 132.500 ;
    END
  END Tile_X0Y1_WW4END[11]
  PIN Tile_X0Y1_WW4END[12]
    DIRECTION INPUT ;
    USE SIGNAL ;
    ANTENNAGATEAREA 0.180700 ;
    PORT
      LAYER Metal3 ;
        RECT 188.240 133.780 188.640 134.180 ;
    END
  END Tile_X0Y1_WW4END[12]
  PIN Tile_X0Y1_WW4END[13]
    DIRECTION INPUT ;
    USE SIGNAL ;
    ANTENNAGATEAREA 0.180700 ;
    PORT
      LAYER Metal3 ;
        RECT 188.240 135.460 188.640 135.860 ;
    END
  END Tile_X0Y1_WW4END[13]
  PIN Tile_X0Y1_WW4END[14]
    DIRECTION INPUT ;
    USE SIGNAL ;
    ANTENNAGATEAREA 0.180700 ;
    PORT
      LAYER Metal3 ;
        RECT 188.240 137.140 188.640 137.540 ;
    END
  END Tile_X0Y1_WW4END[14]
  PIN Tile_X0Y1_WW4END[15]
    DIRECTION INPUT ;
    USE SIGNAL ;
    ANTENNAGATEAREA 0.180700 ;
    PORT
      LAYER Metal3 ;
        RECT 188.240 138.820 188.640 139.220 ;
    END
  END Tile_X0Y1_WW4END[15]
  PIN Tile_X0Y1_WW4END[1]
    DIRECTION INPUT ;
    USE SIGNAL ;
    ANTENNAGATEAREA 0.665600 ;
    PORT
      LAYER Metal3 ;
        RECT 188.240 115.300 188.640 115.700 ;
    END
  END Tile_X0Y1_WW4END[1]
  PIN Tile_X0Y1_WW4END[2]
    DIRECTION INPUT ;
    USE SIGNAL ;
    ANTENNAGATEAREA 0.718400 ;
    PORT
      LAYER Metal3 ;
        RECT 188.240 116.980 188.640 117.380 ;
    END
  END Tile_X0Y1_WW4END[2]
  PIN Tile_X0Y1_WW4END[3]
    DIRECTION INPUT ;
    USE SIGNAL ;
    ANTENNAGATEAREA 0.705400 ;
    PORT
      LAYER Metal3 ;
        RECT 188.240 118.660 188.640 119.060 ;
    END
  END Tile_X0Y1_WW4END[3]
  PIN Tile_X0Y1_WW4END[4]
    DIRECTION INPUT ;
    USE SIGNAL ;
    ANTENNAGATEAREA 0.180700 ;
    PORT
      LAYER Metal3 ;
        RECT 188.240 120.340 188.640 120.740 ;
    END
  END Tile_X0Y1_WW4END[4]
  PIN Tile_X0Y1_WW4END[5]
    DIRECTION INPUT ;
    USE SIGNAL ;
    ANTENNAGATEAREA 0.180700 ;
    PORT
      LAYER Metal3 ;
        RECT 188.240 122.020 188.640 122.420 ;
    END
  END Tile_X0Y1_WW4END[5]
  PIN Tile_X0Y1_WW4END[6]
    DIRECTION INPUT ;
    USE SIGNAL ;
    ANTENNAGATEAREA 0.180700 ;
    PORT
      LAYER Metal3 ;
        RECT 188.240 123.700 188.640 124.100 ;
    END
  END Tile_X0Y1_WW4END[6]
  PIN Tile_X0Y1_WW4END[7]
    DIRECTION INPUT ;
    USE SIGNAL ;
    ANTENNAGATEAREA 0.180700 ;
    PORT
      LAYER Metal3 ;
        RECT 188.240 125.380 188.640 125.780 ;
    END
  END Tile_X0Y1_WW4END[7]
  PIN Tile_X0Y1_WW4END[8]
    DIRECTION INPUT ;
    USE SIGNAL ;
    ANTENNAGATEAREA 0.180700 ;
    PORT
      LAYER Metal3 ;
        RECT 188.240 127.060 188.640 127.460 ;
    END
  END Tile_X0Y1_WW4END[8]
  PIN Tile_X0Y1_WW4END[9]
    DIRECTION INPUT ;
    USE SIGNAL ;
    ANTENNAGATEAREA 0.180700 ;
    PORT
      LAYER Metal3 ;
        RECT 188.240 128.740 188.640 129.140 ;
    END
  END Tile_X0Y1_WW4END[9]
  PIN VGND
    DIRECTION INOUT ;
    USE GROUND ;
    PORT
      LAYER Metal4 ;
        RECT 21.580 0.000 23.780 430.920 ;
    END
    PORT
      LAYER Metal4 ;
        RECT 97.180 0.000 99.380 430.920 ;
    END
    PORT
      LAYER Metal4 ;
        RECT 172.780 0.000 174.980 430.920 ;
    END
  END VGND
  PIN VPWR
    DIRECTION INOUT ;
    USE POWER ;
    PORT
      LAYER Metal4 ;
        RECT 15.380 0.000 17.580 430.920 ;
    END
    PORT
      LAYER Metal4 ;
        RECT 90.980 0.000 93.180 430.920 ;
    END
    PORT
      LAYER Metal4 ;
        RECT 166.580 0.000 168.780 430.920 ;
    END
  END VPWR
  OBS
      LAYER GatPoly ;
        RECT 2.880 3.630 185.760 427.290 ;
      LAYER Metal1 ;
        RECT 2.880 3.560 185.760 427.360 ;
      LAYER Metal2 ;
        RECT 0.375 430.310 1.990 430.645 ;
        RECT 2.810 430.310 2.950 430.645 ;
        RECT 3.770 430.310 3.910 430.645 ;
        RECT 4.730 430.310 4.870 430.645 ;
        RECT 5.690 430.310 8.710 430.645 ;
        RECT 9.530 430.310 9.670 430.645 ;
        RECT 10.490 430.310 10.630 430.645 ;
        RECT 11.450 430.310 11.590 430.645 ;
        RECT 12.410 430.310 12.550 430.645 ;
        RECT 13.370 430.310 13.510 430.645 ;
        RECT 14.330 430.310 14.470 430.645 ;
        RECT 15.290 430.310 15.430 430.645 ;
        RECT 16.250 430.310 21.190 430.645 ;
        RECT 22.010 430.310 22.150 430.645 ;
        RECT 22.970 430.310 23.110 430.645 ;
        RECT 23.930 430.310 24.070 430.645 ;
        RECT 24.890 430.310 25.030 430.645 ;
        RECT 25.850 430.310 25.990 430.645 ;
        RECT 26.810 430.310 26.950 430.645 ;
        RECT 27.770 430.310 27.910 430.645 ;
        RECT 28.730 430.310 34.630 430.645 ;
        RECT 35.450 430.310 35.590 430.645 ;
        RECT 36.410 430.310 36.550 430.645 ;
        RECT 37.370 430.310 37.510 430.645 ;
        RECT 38.330 430.310 38.470 430.645 ;
        RECT 39.290 430.310 39.430 430.645 ;
        RECT 40.250 430.310 40.390 430.645 ;
        RECT 41.210 430.310 41.350 430.645 ;
        RECT 42.170 430.310 42.310 430.645 ;
        RECT 43.130 430.310 43.270 430.645 ;
        RECT 44.090 430.310 44.230 430.645 ;
        RECT 45.050 430.310 45.190 430.645 ;
        RECT 46.010 430.310 46.150 430.645 ;
        RECT 46.970 430.310 47.110 430.645 ;
        RECT 47.930 430.310 48.070 430.645 ;
        RECT 48.890 430.310 49.030 430.645 ;
        RECT 49.850 430.310 58.630 430.645 ;
        RECT 59.450 430.310 59.590 430.645 ;
        RECT 60.410 430.310 60.550 430.645 ;
        RECT 61.370 430.310 61.510 430.645 ;
        RECT 62.330 430.310 62.470 430.645 ;
        RECT 63.290 430.310 63.430 430.645 ;
        RECT 64.250 430.310 64.390 430.645 ;
        RECT 65.210 430.310 65.350 430.645 ;
        RECT 66.170 430.310 66.310 430.645 ;
        RECT 67.130 430.310 67.270 430.645 ;
        RECT 68.090 430.310 68.230 430.645 ;
        RECT 69.050 430.310 69.190 430.645 ;
        RECT 70.010 430.310 70.150 430.645 ;
        RECT 70.970 430.310 71.110 430.645 ;
        RECT 71.930 430.310 72.070 430.645 ;
        RECT 72.890 430.310 73.030 430.645 ;
        RECT 73.850 430.310 79.750 430.645 ;
        RECT 80.570 430.310 80.710 430.645 ;
        RECT 81.530 430.310 81.670 430.645 ;
        RECT 82.490 430.310 82.630 430.645 ;
        RECT 83.450 430.310 86.470 430.645 ;
        RECT 87.290 430.310 87.430 430.645 ;
        RECT 88.250 430.310 88.390 430.645 ;
        RECT 89.210 430.310 89.350 430.645 ;
        RECT 90.170 430.310 90.310 430.645 ;
        RECT 91.130 430.310 91.270 430.645 ;
        RECT 92.090 430.310 92.230 430.645 ;
        RECT 93.050 430.310 93.190 430.645 ;
        RECT 94.010 430.310 98.950 430.645 ;
        RECT 99.770 430.310 99.910 430.645 ;
        RECT 100.730 430.310 100.870 430.645 ;
        RECT 101.690 430.310 101.830 430.645 ;
        RECT 102.650 430.310 102.790 430.645 ;
        RECT 103.610 430.310 103.750 430.645 ;
        RECT 104.570 430.310 104.710 430.645 ;
        RECT 105.530 430.310 105.670 430.645 ;
        RECT 106.490 430.310 113.350 430.645 ;
        RECT 114.170 430.310 114.310 430.645 ;
        RECT 115.130 430.310 115.270 430.645 ;
        RECT 116.090 430.310 116.230 430.645 ;
        RECT 117.050 430.310 117.190 430.645 ;
        RECT 118.010 430.310 118.150 430.645 ;
        RECT 118.970 430.310 119.110 430.645 ;
        RECT 119.930 430.310 120.070 430.645 ;
        RECT 120.890 430.310 121.030 430.645 ;
        RECT 121.850 430.310 121.990 430.645 ;
        RECT 122.810 430.310 122.950 430.645 ;
        RECT 123.770 430.310 123.910 430.645 ;
        RECT 124.730 430.310 124.870 430.645 ;
        RECT 125.690 430.310 125.830 430.645 ;
        RECT 126.650 430.310 126.790 430.645 ;
        RECT 127.610 430.310 127.750 430.645 ;
        RECT 128.570 430.310 138.310 430.645 ;
        RECT 139.130 430.310 139.270 430.645 ;
        RECT 140.090 430.310 140.230 430.645 ;
        RECT 141.050 430.310 141.190 430.645 ;
        RECT 142.010 430.310 142.150 430.645 ;
        RECT 142.970 430.310 143.110 430.645 ;
        RECT 143.930 430.310 144.070 430.645 ;
        RECT 144.890 430.310 145.030 430.645 ;
        RECT 145.850 430.310 145.990 430.645 ;
        RECT 146.810 430.310 146.950 430.645 ;
        RECT 147.770 430.310 147.910 430.645 ;
        RECT 148.730 430.310 148.870 430.645 ;
        RECT 149.690 430.310 149.830 430.645 ;
        RECT 150.650 430.310 150.790 430.645 ;
        RECT 151.610 430.310 151.750 430.645 ;
        RECT 152.570 430.310 152.710 430.645 ;
        RECT 153.530 430.310 164.230 430.645 ;
        RECT 165.050 430.310 165.190 430.645 ;
        RECT 166.010 430.310 166.150 430.645 ;
        RECT 166.970 430.310 167.110 430.645 ;
        RECT 167.930 430.310 168.070 430.645 ;
        RECT 168.890 430.310 169.030 430.645 ;
        RECT 169.850 430.310 169.990 430.645 ;
        RECT 170.810 430.310 170.950 430.645 ;
        RECT 171.770 430.310 171.910 430.645 ;
        RECT 172.730 430.310 172.870 430.645 ;
        RECT 173.690 430.310 173.830 430.645 ;
        RECT 174.650 430.310 174.790 430.645 ;
        RECT 175.610 430.310 175.750 430.645 ;
        RECT 176.570 430.310 176.710 430.645 ;
        RECT 177.530 430.310 177.670 430.645 ;
        RECT 178.490 430.310 178.630 430.645 ;
        RECT 179.450 430.310 179.590 430.645 ;
        RECT 180.410 430.310 180.550 430.645 ;
        RECT 181.370 430.310 181.510 430.645 ;
        RECT 182.330 430.310 182.470 430.645 ;
        RECT 183.290 430.310 188.265 430.645 ;
        RECT 0.375 0.610 188.265 430.310 ;
        RECT 0.375 0.275 1.990 0.610 ;
        RECT 2.810 0.275 2.950 0.610 ;
        RECT 3.770 0.275 3.910 0.610 ;
        RECT 4.730 0.275 4.870 0.610 ;
        RECT 5.690 0.275 8.710 0.610 ;
        RECT 9.530 0.275 9.670 0.610 ;
        RECT 10.490 0.275 10.630 0.610 ;
        RECT 11.450 0.275 11.590 0.610 ;
        RECT 12.410 0.275 12.550 0.610 ;
        RECT 13.370 0.275 13.510 0.610 ;
        RECT 14.330 0.275 14.470 0.610 ;
        RECT 15.290 0.275 15.430 0.610 ;
        RECT 16.250 0.275 21.190 0.610 ;
        RECT 22.010 0.275 22.150 0.610 ;
        RECT 22.970 0.275 23.110 0.610 ;
        RECT 23.930 0.275 24.070 0.610 ;
        RECT 24.890 0.275 25.030 0.610 ;
        RECT 25.850 0.275 25.990 0.610 ;
        RECT 26.810 0.275 26.950 0.610 ;
        RECT 27.770 0.275 27.910 0.610 ;
        RECT 28.730 0.275 34.630 0.610 ;
        RECT 35.450 0.275 35.590 0.610 ;
        RECT 36.410 0.275 36.550 0.610 ;
        RECT 37.370 0.275 37.510 0.610 ;
        RECT 38.330 0.275 38.470 0.610 ;
        RECT 39.290 0.275 39.430 0.610 ;
        RECT 40.250 0.275 40.390 0.610 ;
        RECT 41.210 0.275 41.350 0.610 ;
        RECT 42.170 0.275 42.310 0.610 ;
        RECT 43.130 0.275 43.270 0.610 ;
        RECT 44.090 0.275 44.230 0.610 ;
        RECT 45.050 0.275 45.190 0.610 ;
        RECT 46.010 0.275 46.150 0.610 ;
        RECT 46.970 0.275 47.110 0.610 ;
        RECT 47.930 0.275 48.070 0.610 ;
        RECT 48.890 0.275 49.030 0.610 ;
        RECT 49.850 0.275 58.630 0.610 ;
        RECT 59.450 0.275 59.590 0.610 ;
        RECT 60.410 0.275 60.550 0.610 ;
        RECT 61.370 0.275 61.510 0.610 ;
        RECT 62.330 0.275 62.470 0.610 ;
        RECT 63.290 0.275 63.430 0.610 ;
        RECT 64.250 0.275 64.390 0.610 ;
        RECT 65.210 0.275 65.350 0.610 ;
        RECT 66.170 0.275 66.310 0.610 ;
        RECT 67.130 0.275 67.270 0.610 ;
        RECT 68.090 0.275 68.230 0.610 ;
        RECT 69.050 0.275 69.190 0.610 ;
        RECT 70.010 0.275 70.150 0.610 ;
        RECT 70.970 0.275 71.110 0.610 ;
        RECT 71.930 0.275 72.070 0.610 ;
        RECT 72.890 0.275 73.030 0.610 ;
        RECT 73.850 0.275 79.750 0.610 ;
        RECT 80.570 0.275 80.710 0.610 ;
        RECT 81.530 0.275 81.670 0.610 ;
        RECT 82.490 0.275 82.630 0.610 ;
        RECT 83.450 0.275 86.470 0.610 ;
        RECT 87.290 0.275 87.430 0.610 ;
        RECT 88.250 0.275 88.390 0.610 ;
        RECT 89.210 0.275 89.350 0.610 ;
        RECT 90.170 0.275 90.310 0.610 ;
        RECT 91.130 0.275 91.270 0.610 ;
        RECT 92.090 0.275 92.230 0.610 ;
        RECT 93.050 0.275 93.190 0.610 ;
        RECT 94.010 0.275 98.950 0.610 ;
        RECT 99.770 0.275 99.910 0.610 ;
        RECT 100.730 0.275 100.870 0.610 ;
        RECT 101.690 0.275 101.830 0.610 ;
        RECT 102.650 0.275 102.790 0.610 ;
        RECT 103.610 0.275 103.750 0.610 ;
        RECT 104.570 0.275 104.710 0.610 ;
        RECT 105.530 0.275 105.670 0.610 ;
        RECT 106.490 0.275 113.350 0.610 ;
        RECT 114.170 0.275 114.310 0.610 ;
        RECT 115.130 0.275 115.270 0.610 ;
        RECT 116.090 0.275 116.230 0.610 ;
        RECT 117.050 0.275 117.190 0.610 ;
        RECT 118.010 0.275 118.150 0.610 ;
        RECT 118.970 0.275 119.110 0.610 ;
        RECT 119.930 0.275 120.070 0.610 ;
        RECT 120.890 0.275 121.030 0.610 ;
        RECT 121.850 0.275 121.990 0.610 ;
        RECT 122.810 0.275 122.950 0.610 ;
        RECT 123.770 0.275 123.910 0.610 ;
        RECT 124.730 0.275 124.870 0.610 ;
        RECT 125.690 0.275 125.830 0.610 ;
        RECT 126.650 0.275 126.790 0.610 ;
        RECT 127.610 0.275 127.750 0.610 ;
        RECT 128.570 0.275 138.310 0.610 ;
        RECT 139.130 0.275 139.270 0.610 ;
        RECT 140.090 0.275 140.230 0.610 ;
        RECT 141.050 0.275 141.190 0.610 ;
        RECT 142.010 0.275 142.150 0.610 ;
        RECT 142.970 0.275 143.110 0.610 ;
        RECT 143.930 0.275 144.070 0.610 ;
        RECT 144.890 0.275 145.030 0.610 ;
        RECT 145.850 0.275 145.990 0.610 ;
        RECT 146.810 0.275 146.950 0.610 ;
        RECT 147.770 0.275 147.910 0.610 ;
        RECT 148.730 0.275 148.870 0.610 ;
        RECT 149.690 0.275 149.830 0.610 ;
        RECT 150.650 0.275 150.790 0.610 ;
        RECT 151.610 0.275 151.750 0.610 ;
        RECT 152.570 0.275 152.710 0.610 ;
        RECT 153.530 0.275 164.230 0.610 ;
        RECT 165.050 0.275 165.190 0.610 ;
        RECT 166.010 0.275 166.150 0.610 ;
        RECT 166.970 0.275 167.110 0.610 ;
        RECT 167.930 0.275 168.070 0.610 ;
        RECT 168.890 0.275 169.030 0.610 ;
        RECT 169.850 0.275 169.990 0.610 ;
        RECT 170.810 0.275 170.950 0.610 ;
        RECT 171.770 0.275 171.910 0.610 ;
        RECT 172.730 0.275 172.870 0.610 ;
        RECT 173.690 0.275 173.830 0.610 ;
        RECT 174.650 0.275 174.790 0.610 ;
        RECT 175.610 0.275 175.750 0.610 ;
        RECT 176.570 0.275 176.710 0.610 ;
        RECT 177.530 0.275 177.670 0.610 ;
        RECT 178.490 0.275 178.630 0.610 ;
        RECT 179.450 0.275 179.590 0.610 ;
        RECT 180.410 0.275 180.550 0.610 ;
        RECT 181.370 0.275 181.510 0.610 ;
        RECT 182.330 0.275 182.470 0.610 ;
        RECT 183.290 0.275 188.265 0.610 ;
      LAYER Metal3 ;
        RECT 0.335 430.490 188.305 430.605 ;
        RECT 0.610 429.670 188.030 430.490 ;
        RECT 0.335 428.810 188.305 429.670 ;
        RECT 0.610 427.990 188.030 428.810 ;
        RECT 0.335 427.130 188.305 427.990 ;
        RECT 0.610 426.310 188.030 427.130 ;
        RECT 0.335 425.450 188.305 426.310 ;
        RECT 0.610 424.630 188.030 425.450 ;
        RECT 0.335 423.770 188.305 424.630 ;
        RECT 0.610 422.950 188.030 423.770 ;
        RECT 0.335 422.090 188.305 422.950 ;
        RECT 0.610 421.270 188.030 422.090 ;
        RECT 0.335 420.410 188.305 421.270 ;
        RECT 0.610 419.590 188.030 420.410 ;
        RECT 0.335 418.730 188.305 419.590 ;
        RECT 0.610 417.910 188.030 418.730 ;
        RECT 0.335 417.050 188.305 417.910 ;
        RECT 0.610 416.230 188.030 417.050 ;
        RECT 0.335 415.370 188.305 416.230 ;
        RECT 0.610 414.550 188.030 415.370 ;
        RECT 0.335 413.690 188.305 414.550 ;
        RECT 0.610 412.870 188.030 413.690 ;
        RECT 0.335 412.010 188.305 412.870 ;
        RECT 0.610 411.190 188.030 412.010 ;
        RECT 0.335 410.330 188.305 411.190 ;
        RECT 0.610 409.510 188.030 410.330 ;
        RECT 0.335 408.650 188.305 409.510 ;
        RECT 0.610 407.830 188.030 408.650 ;
        RECT 0.335 406.970 188.305 407.830 ;
        RECT 0.610 406.150 188.030 406.970 ;
        RECT 0.335 405.290 188.305 406.150 ;
        RECT 0.610 404.470 188.030 405.290 ;
        RECT 0.335 403.610 188.305 404.470 ;
        RECT 0.610 402.790 188.030 403.610 ;
        RECT 0.335 401.930 188.305 402.790 ;
        RECT 0.610 401.110 188.030 401.930 ;
        RECT 0.335 400.250 188.305 401.110 ;
        RECT 0.610 399.430 188.030 400.250 ;
        RECT 0.335 398.570 188.305 399.430 ;
        RECT 0.610 397.750 188.030 398.570 ;
        RECT 0.335 396.890 188.305 397.750 ;
        RECT 0.610 396.070 188.030 396.890 ;
        RECT 0.335 395.210 188.305 396.070 ;
        RECT 0.610 394.390 188.030 395.210 ;
        RECT 0.335 393.530 188.305 394.390 ;
        RECT 0.610 392.710 188.030 393.530 ;
        RECT 0.335 391.850 188.305 392.710 ;
        RECT 0.610 391.030 188.030 391.850 ;
        RECT 0.335 390.170 188.305 391.030 ;
        RECT 0.610 389.350 188.030 390.170 ;
        RECT 0.335 388.490 188.305 389.350 ;
        RECT 0.610 387.670 188.030 388.490 ;
        RECT 0.335 386.810 188.305 387.670 ;
        RECT 0.610 385.990 188.030 386.810 ;
        RECT 0.335 385.130 188.305 385.990 ;
        RECT 0.610 384.310 188.030 385.130 ;
        RECT 0.335 383.450 188.305 384.310 ;
        RECT 0.610 382.630 188.030 383.450 ;
        RECT 0.335 381.770 188.305 382.630 ;
        RECT 0.610 380.950 188.030 381.770 ;
        RECT 0.335 380.090 188.305 380.950 ;
        RECT 0.610 379.270 188.030 380.090 ;
        RECT 0.335 378.410 188.305 379.270 ;
        RECT 0.610 377.590 188.030 378.410 ;
        RECT 0.335 376.730 188.305 377.590 ;
        RECT 0.610 375.910 188.030 376.730 ;
        RECT 0.335 375.050 188.305 375.910 ;
        RECT 0.610 374.230 188.030 375.050 ;
        RECT 0.335 373.370 188.305 374.230 ;
        RECT 0.610 372.550 188.030 373.370 ;
        RECT 0.335 371.690 188.305 372.550 ;
        RECT 0.610 370.870 188.030 371.690 ;
        RECT 0.335 370.010 188.305 370.870 ;
        RECT 0.610 369.190 188.030 370.010 ;
        RECT 0.335 368.330 188.305 369.190 ;
        RECT 0.610 367.510 188.030 368.330 ;
        RECT 0.335 366.650 188.305 367.510 ;
        RECT 0.610 365.830 188.030 366.650 ;
        RECT 0.335 364.970 188.305 365.830 ;
        RECT 0.610 364.150 188.030 364.970 ;
        RECT 0.335 363.290 188.305 364.150 ;
        RECT 0.610 362.470 188.030 363.290 ;
        RECT 0.335 361.610 188.305 362.470 ;
        RECT 0.610 360.790 188.030 361.610 ;
        RECT 0.335 359.930 188.305 360.790 ;
        RECT 0.610 359.110 188.030 359.930 ;
        RECT 0.335 358.250 188.305 359.110 ;
        RECT 0.610 357.430 188.030 358.250 ;
        RECT 0.335 356.570 188.305 357.430 ;
        RECT 0.610 355.750 188.030 356.570 ;
        RECT 0.335 354.890 188.305 355.750 ;
        RECT 0.610 354.070 188.030 354.890 ;
        RECT 0.335 353.210 188.305 354.070 ;
        RECT 0.610 352.390 188.030 353.210 ;
        RECT 0.335 351.530 188.305 352.390 ;
        RECT 0.610 350.710 188.030 351.530 ;
        RECT 0.335 349.850 188.305 350.710 ;
        RECT 0.610 349.030 188.030 349.850 ;
        RECT 0.335 348.170 188.305 349.030 ;
        RECT 0.610 347.350 188.030 348.170 ;
        RECT 0.335 346.490 188.305 347.350 ;
        RECT 0.610 345.670 188.030 346.490 ;
        RECT 0.335 344.810 188.305 345.670 ;
        RECT 0.610 343.990 188.030 344.810 ;
        RECT 0.335 343.130 188.305 343.990 ;
        RECT 0.610 342.310 188.030 343.130 ;
        RECT 0.335 341.450 188.305 342.310 ;
        RECT 0.610 340.630 188.030 341.450 ;
        RECT 0.335 339.770 188.305 340.630 ;
        RECT 0.610 338.950 188.030 339.770 ;
        RECT 0.335 338.090 188.305 338.950 ;
        RECT 0.610 337.270 188.030 338.090 ;
        RECT 0.335 336.410 188.305 337.270 ;
        RECT 0.610 335.590 188.030 336.410 ;
        RECT 0.335 334.730 188.305 335.590 ;
        RECT 0.610 333.910 188.030 334.730 ;
        RECT 0.335 333.050 188.305 333.910 ;
        RECT 0.610 332.230 188.030 333.050 ;
        RECT 0.335 331.370 188.305 332.230 ;
        RECT 0.610 330.550 188.030 331.370 ;
        RECT 0.335 329.690 188.305 330.550 ;
        RECT 0.610 328.870 188.030 329.690 ;
        RECT 0.335 328.010 188.305 328.870 ;
        RECT 0.610 327.190 188.030 328.010 ;
        RECT 0.335 326.330 188.305 327.190 ;
        RECT 0.610 325.510 188.030 326.330 ;
        RECT 0.335 324.650 188.305 325.510 ;
        RECT 0.610 323.830 188.030 324.650 ;
        RECT 0.335 322.970 188.305 323.830 ;
        RECT 0.610 322.150 188.030 322.970 ;
        RECT 0.335 321.290 188.305 322.150 ;
        RECT 0.610 320.470 188.030 321.290 ;
        RECT 0.335 319.610 188.305 320.470 ;
        RECT 0.610 318.790 188.030 319.610 ;
        RECT 0.335 317.930 188.305 318.790 ;
        RECT 0.610 317.110 188.030 317.930 ;
        RECT 0.335 316.250 188.305 317.110 ;
        RECT 0.610 315.430 188.030 316.250 ;
        RECT 0.335 314.570 188.305 315.430 ;
        RECT 0.610 313.750 188.030 314.570 ;
        RECT 0.335 312.890 188.305 313.750 ;
        RECT 0.610 312.070 188.030 312.890 ;
        RECT 0.335 311.210 188.305 312.070 ;
        RECT 0.610 310.390 188.030 311.210 ;
        RECT 0.335 309.530 188.305 310.390 ;
        RECT 0.610 308.710 188.030 309.530 ;
        RECT 0.335 307.850 188.305 308.710 ;
        RECT 0.610 307.030 188.030 307.850 ;
        RECT 0.335 306.170 188.305 307.030 ;
        RECT 0.610 305.350 188.030 306.170 ;
        RECT 0.335 304.490 188.305 305.350 ;
        RECT 0.610 303.670 188.030 304.490 ;
        RECT 0.335 302.810 188.305 303.670 ;
        RECT 0.610 301.990 188.030 302.810 ;
        RECT 0.335 301.130 188.305 301.990 ;
        RECT 0.610 300.310 188.030 301.130 ;
        RECT 0.335 299.450 188.305 300.310 ;
        RECT 0.610 298.630 188.030 299.450 ;
        RECT 0.335 297.770 188.305 298.630 ;
        RECT 0.610 296.950 188.030 297.770 ;
        RECT 0.335 296.090 188.305 296.950 ;
        RECT 0.610 295.270 188.030 296.090 ;
        RECT 0.335 294.410 188.305 295.270 ;
        RECT 0.610 293.590 188.030 294.410 ;
        RECT 0.335 292.730 188.305 293.590 ;
        RECT 0.610 291.910 188.030 292.730 ;
        RECT 0.335 291.050 188.305 291.910 ;
        RECT 0.610 290.230 188.030 291.050 ;
        RECT 0.335 289.370 188.305 290.230 ;
        RECT 0.610 288.550 188.030 289.370 ;
        RECT 0.335 287.690 188.305 288.550 ;
        RECT 0.610 286.870 188.030 287.690 ;
        RECT 0.335 286.010 188.305 286.870 ;
        RECT 0.610 285.190 188.030 286.010 ;
        RECT 0.335 284.330 188.305 285.190 ;
        RECT 0.610 283.510 188.030 284.330 ;
        RECT 0.335 282.650 188.305 283.510 ;
        RECT 0.610 281.830 188.030 282.650 ;
        RECT 0.335 280.970 188.305 281.830 ;
        RECT 0.610 280.150 188.030 280.970 ;
        RECT 0.335 279.290 188.305 280.150 ;
        RECT 0.610 278.470 188.030 279.290 ;
        RECT 0.335 277.610 188.305 278.470 ;
        RECT 0.610 276.790 188.030 277.610 ;
        RECT 0.335 275.930 188.305 276.790 ;
        RECT 0.610 275.110 188.030 275.930 ;
        RECT 0.335 268.370 188.305 275.110 ;
        RECT 0.610 267.550 188.030 268.370 ;
        RECT 0.335 267.530 188.305 267.550 ;
        RECT 0.610 266.710 188.030 267.530 ;
        RECT 0.335 266.690 188.305 266.710 ;
        RECT 0.610 265.870 188.030 266.690 ;
        RECT 0.335 265.850 188.305 265.870 ;
        RECT 0.610 265.030 188.030 265.850 ;
        RECT 0.335 265.010 188.305 265.030 ;
        RECT 0.610 264.190 188.030 265.010 ;
        RECT 0.335 264.170 188.305 264.190 ;
        RECT 0.610 263.350 188.030 264.170 ;
        RECT 0.335 263.330 188.305 263.350 ;
        RECT 0.610 262.510 188.030 263.330 ;
        RECT 0.335 262.490 188.305 262.510 ;
        RECT 0.610 261.670 188.030 262.490 ;
        RECT 0.335 261.650 188.305 261.670 ;
        RECT 0.610 260.830 188.030 261.650 ;
        RECT 0.335 260.810 188.305 260.830 ;
        RECT 0.610 259.990 188.030 260.810 ;
        RECT 0.335 259.970 188.305 259.990 ;
        RECT 0.610 259.150 188.030 259.970 ;
        RECT 0.335 259.130 188.305 259.150 ;
        RECT 0.610 258.310 188.030 259.130 ;
        RECT 0.335 258.290 188.305 258.310 ;
        RECT 0.610 257.470 188.030 258.290 ;
        RECT 0.335 257.450 188.305 257.470 ;
        RECT 0.610 256.630 188.030 257.450 ;
        RECT 0.335 256.610 188.305 256.630 ;
        RECT 0.610 255.790 188.030 256.610 ;
        RECT 0.335 255.770 188.305 255.790 ;
        RECT 0.610 254.950 188.030 255.770 ;
        RECT 0.335 248.210 188.305 254.950 ;
        RECT 0.610 247.390 188.030 248.210 ;
        RECT 0.335 246.530 188.305 247.390 ;
        RECT 0.610 245.710 188.030 246.530 ;
        RECT 0.335 244.850 188.305 245.710 ;
        RECT 0.610 244.030 188.030 244.850 ;
        RECT 0.335 243.170 188.305 244.030 ;
        RECT 0.610 242.350 188.030 243.170 ;
        RECT 0.335 241.490 188.305 242.350 ;
        RECT 0.610 240.670 188.030 241.490 ;
        RECT 0.335 239.810 188.305 240.670 ;
        RECT 0.610 238.990 188.030 239.810 ;
        RECT 0.335 238.130 188.305 238.990 ;
        RECT 0.610 237.310 188.030 238.130 ;
        RECT 0.335 236.450 188.305 237.310 ;
        RECT 0.610 235.630 188.030 236.450 ;
        RECT 0.335 232.250 188.305 235.630 ;
        RECT 0.610 231.430 188.030 232.250 ;
        RECT 0.335 231.410 188.305 231.430 ;
        RECT 0.610 230.590 188.030 231.410 ;
        RECT 0.335 230.570 188.305 230.590 ;
        RECT 0.610 229.750 188.030 230.570 ;
        RECT 0.335 229.730 188.305 229.750 ;
        RECT 0.610 228.910 188.030 229.730 ;
        RECT 0.335 228.890 188.305 228.910 ;
        RECT 0.610 228.070 188.030 228.890 ;
        RECT 0.335 228.050 188.305 228.070 ;
        RECT 0.610 227.230 188.030 228.050 ;
        RECT 0.335 227.210 188.305 227.230 ;
        RECT 0.610 226.390 188.030 227.210 ;
        RECT 0.335 226.370 188.305 226.390 ;
        RECT 0.610 225.550 188.030 226.370 ;
        RECT 0.335 222.170 188.305 225.550 ;
        RECT 0.610 221.350 188.030 222.170 ;
        RECT 0.335 220.490 188.305 221.350 ;
        RECT 0.610 219.670 188.030 220.490 ;
        RECT 0.335 218.810 188.305 219.670 ;
        RECT 0.610 217.990 188.030 218.810 ;
        RECT 0.335 217.130 188.305 217.990 ;
        RECT 0.610 216.310 188.030 217.130 ;
        RECT 0.335 215.030 188.305 216.310 ;
        RECT 0.610 214.210 188.030 215.030 ;
        RECT 0.335 213.350 188.305 214.210 ;
        RECT 0.610 212.530 188.030 213.350 ;
        RECT 0.335 211.670 188.305 212.530 ;
        RECT 0.610 210.850 188.030 211.670 ;
        RECT 0.335 209.990 188.305 210.850 ;
        RECT 0.610 209.170 188.030 209.990 ;
        RECT 0.335 208.310 188.305 209.170 ;
        RECT 0.610 207.490 188.030 208.310 ;
        RECT 0.335 206.630 188.305 207.490 ;
        RECT 0.610 205.810 188.030 206.630 ;
        RECT 0.335 204.950 188.305 205.810 ;
        RECT 0.610 204.130 188.030 204.950 ;
        RECT 0.335 203.270 188.305 204.130 ;
        RECT 0.610 202.450 188.030 203.270 ;
        RECT 0.335 201.590 188.305 202.450 ;
        RECT 0.610 200.770 188.030 201.590 ;
        RECT 0.335 199.910 188.305 200.770 ;
        RECT 0.610 199.090 188.030 199.910 ;
        RECT 0.335 198.230 188.305 199.090 ;
        RECT 0.610 197.410 188.030 198.230 ;
        RECT 0.335 196.550 188.305 197.410 ;
        RECT 0.610 195.730 188.030 196.550 ;
        RECT 0.335 194.870 188.305 195.730 ;
        RECT 0.610 194.050 188.030 194.870 ;
        RECT 0.335 193.190 188.305 194.050 ;
        RECT 0.610 192.370 188.030 193.190 ;
        RECT 0.335 191.510 188.305 192.370 ;
        RECT 0.610 190.690 188.030 191.510 ;
        RECT 0.335 189.830 188.305 190.690 ;
        RECT 0.610 189.010 188.030 189.830 ;
        RECT 0.335 188.150 188.305 189.010 ;
        RECT 0.610 187.330 188.030 188.150 ;
        RECT 0.335 186.470 188.305 187.330 ;
        RECT 0.610 185.650 188.030 186.470 ;
        RECT 0.335 184.790 188.305 185.650 ;
        RECT 0.610 183.970 188.030 184.790 ;
        RECT 0.335 183.110 188.305 183.970 ;
        RECT 0.610 182.290 188.030 183.110 ;
        RECT 0.335 181.430 188.305 182.290 ;
        RECT 0.610 180.610 188.030 181.430 ;
        RECT 0.335 179.750 188.305 180.610 ;
        RECT 0.610 178.930 188.030 179.750 ;
        RECT 0.335 178.070 188.305 178.930 ;
        RECT 0.610 177.250 188.030 178.070 ;
        RECT 0.335 176.390 188.305 177.250 ;
        RECT 0.610 175.570 188.030 176.390 ;
        RECT 0.335 174.710 188.305 175.570 ;
        RECT 0.610 173.890 188.030 174.710 ;
        RECT 0.335 173.030 188.305 173.890 ;
        RECT 0.610 172.210 188.030 173.030 ;
        RECT 0.335 171.350 188.305 172.210 ;
        RECT 0.610 170.530 188.030 171.350 ;
        RECT 0.335 169.670 188.305 170.530 ;
        RECT 0.610 168.850 188.030 169.670 ;
        RECT 0.335 167.990 188.305 168.850 ;
        RECT 0.610 167.170 188.030 167.990 ;
        RECT 0.335 166.310 188.305 167.170 ;
        RECT 0.610 165.490 188.030 166.310 ;
        RECT 0.335 164.630 188.305 165.490 ;
        RECT 0.610 163.810 188.030 164.630 ;
        RECT 0.335 162.950 188.305 163.810 ;
        RECT 0.610 162.130 188.030 162.950 ;
        RECT 0.335 161.270 188.305 162.130 ;
        RECT 0.610 160.450 188.030 161.270 ;
        RECT 0.335 159.590 188.305 160.450 ;
        RECT 0.610 158.770 188.030 159.590 ;
        RECT 0.335 157.910 188.305 158.770 ;
        RECT 0.610 157.090 188.030 157.910 ;
        RECT 0.335 156.230 188.305 157.090 ;
        RECT 0.610 155.410 188.030 156.230 ;
        RECT 0.335 154.550 188.305 155.410 ;
        RECT 0.610 153.730 188.030 154.550 ;
        RECT 0.335 152.870 188.305 153.730 ;
        RECT 0.610 152.050 188.030 152.870 ;
        RECT 0.335 151.190 188.305 152.050 ;
        RECT 0.610 150.370 188.030 151.190 ;
        RECT 0.335 149.510 188.305 150.370 ;
        RECT 0.610 148.690 188.030 149.510 ;
        RECT 0.335 147.830 188.305 148.690 ;
        RECT 0.610 147.010 188.030 147.830 ;
        RECT 0.335 146.150 188.305 147.010 ;
        RECT 0.610 145.330 188.030 146.150 ;
        RECT 0.335 144.470 188.305 145.330 ;
        RECT 0.610 143.650 188.030 144.470 ;
        RECT 0.335 142.790 188.305 143.650 ;
        RECT 0.610 141.970 188.030 142.790 ;
        RECT 0.335 141.110 188.305 141.970 ;
        RECT 0.610 140.290 188.030 141.110 ;
        RECT 0.335 139.430 188.305 140.290 ;
        RECT 0.610 138.610 188.030 139.430 ;
        RECT 0.335 137.750 188.305 138.610 ;
        RECT 0.610 136.930 188.030 137.750 ;
        RECT 0.335 136.070 188.305 136.930 ;
        RECT 0.610 135.250 188.030 136.070 ;
        RECT 0.335 134.390 188.305 135.250 ;
        RECT 0.610 133.570 188.030 134.390 ;
        RECT 0.335 132.710 188.305 133.570 ;
        RECT 0.610 131.890 188.030 132.710 ;
        RECT 0.335 131.030 188.305 131.890 ;
        RECT 0.610 130.210 188.030 131.030 ;
        RECT 0.335 129.350 188.305 130.210 ;
        RECT 0.610 128.530 188.030 129.350 ;
        RECT 0.335 127.670 188.305 128.530 ;
        RECT 0.610 126.850 188.030 127.670 ;
        RECT 0.335 125.990 188.305 126.850 ;
        RECT 0.610 125.170 188.030 125.990 ;
        RECT 0.335 124.310 188.305 125.170 ;
        RECT 0.610 123.490 188.030 124.310 ;
        RECT 0.335 122.630 188.305 123.490 ;
        RECT 0.610 121.810 188.030 122.630 ;
        RECT 0.335 120.950 188.305 121.810 ;
        RECT 0.610 120.130 188.030 120.950 ;
        RECT 0.335 119.270 188.305 120.130 ;
        RECT 0.610 118.450 188.030 119.270 ;
        RECT 0.335 117.590 188.305 118.450 ;
        RECT 0.610 116.770 188.030 117.590 ;
        RECT 0.335 115.910 188.305 116.770 ;
        RECT 0.610 115.090 188.030 115.910 ;
        RECT 0.335 114.230 188.305 115.090 ;
        RECT 0.610 113.410 188.030 114.230 ;
        RECT 0.335 112.550 188.305 113.410 ;
        RECT 0.610 111.730 188.030 112.550 ;
        RECT 0.335 110.870 188.305 111.730 ;
        RECT 0.610 110.050 188.030 110.870 ;
        RECT 0.335 109.190 188.305 110.050 ;
        RECT 0.610 108.370 188.030 109.190 ;
        RECT 0.335 107.510 188.305 108.370 ;
        RECT 0.610 106.690 188.030 107.510 ;
        RECT 0.335 105.830 188.305 106.690 ;
        RECT 0.610 105.010 188.030 105.830 ;
        RECT 0.335 104.150 188.305 105.010 ;
        RECT 0.610 103.330 188.030 104.150 ;
        RECT 0.335 102.470 188.305 103.330 ;
        RECT 0.610 101.650 188.030 102.470 ;
        RECT 0.335 100.790 188.305 101.650 ;
        RECT 0.610 99.970 188.030 100.790 ;
        RECT 0.335 99.110 188.305 99.970 ;
        RECT 0.610 98.290 188.030 99.110 ;
        RECT 0.335 97.430 188.305 98.290 ;
        RECT 0.610 96.610 188.030 97.430 ;
        RECT 0.335 95.750 188.305 96.610 ;
        RECT 0.610 94.930 188.030 95.750 ;
        RECT 0.335 94.070 188.305 94.930 ;
        RECT 0.610 93.250 188.030 94.070 ;
        RECT 0.335 92.390 188.305 93.250 ;
        RECT 0.610 91.570 188.030 92.390 ;
        RECT 0.335 90.710 188.305 91.570 ;
        RECT 0.610 89.890 188.030 90.710 ;
        RECT 0.335 89.030 188.305 89.890 ;
        RECT 0.610 88.210 188.030 89.030 ;
        RECT 0.335 87.350 188.305 88.210 ;
        RECT 0.610 86.530 188.030 87.350 ;
        RECT 0.335 85.670 188.305 86.530 ;
        RECT 0.610 84.850 188.030 85.670 ;
        RECT 0.335 83.990 188.305 84.850 ;
        RECT 0.610 83.170 188.030 83.990 ;
        RECT 0.335 82.310 188.305 83.170 ;
        RECT 0.610 81.490 188.030 82.310 ;
        RECT 0.335 80.630 188.305 81.490 ;
        RECT 0.610 79.810 188.030 80.630 ;
        RECT 0.335 78.950 188.305 79.810 ;
        RECT 0.610 78.130 188.030 78.950 ;
        RECT 0.335 77.270 188.305 78.130 ;
        RECT 0.610 76.450 188.030 77.270 ;
        RECT 0.335 75.590 188.305 76.450 ;
        RECT 0.610 74.770 188.030 75.590 ;
        RECT 0.335 73.910 188.305 74.770 ;
        RECT 0.610 73.090 188.030 73.910 ;
        RECT 0.335 72.230 188.305 73.090 ;
        RECT 0.610 71.410 188.030 72.230 ;
        RECT 0.335 70.550 188.305 71.410 ;
        RECT 0.610 69.730 188.030 70.550 ;
        RECT 0.335 68.870 188.305 69.730 ;
        RECT 0.610 68.050 188.030 68.870 ;
        RECT 0.335 67.190 188.305 68.050 ;
        RECT 0.610 66.370 188.030 67.190 ;
        RECT 0.335 65.510 188.305 66.370 ;
        RECT 0.610 64.690 188.030 65.510 ;
        RECT 0.335 63.830 188.305 64.690 ;
        RECT 0.610 63.010 188.030 63.830 ;
        RECT 0.335 62.150 188.305 63.010 ;
        RECT 0.610 61.330 188.030 62.150 ;
        RECT 0.335 60.470 188.305 61.330 ;
        RECT 0.610 59.650 188.030 60.470 ;
        RECT 0.335 52.910 188.305 59.650 ;
        RECT 0.610 52.090 188.030 52.910 ;
        RECT 0.335 52.070 188.305 52.090 ;
        RECT 0.610 51.250 188.030 52.070 ;
        RECT 0.335 51.230 188.305 51.250 ;
        RECT 0.610 50.410 188.030 51.230 ;
        RECT 0.335 50.390 188.305 50.410 ;
        RECT 0.610 49.570 188.030 50.390 ;
        RECT 0.335 49.550 188.305 49.570 ;
        RECT 0.610 48.730 188.030 49.550 ;
        RECT 0.335 48.710 188.305 48.730 ;
        RECT 0.610 47.890 188.030 48.710 ;
        RECT 0.335 47.870 188.305 47.890 ;
        RECT 0.610 47.050 188.030 47.870 ;
        RECT 0.335 47.030 188.305 47.050 ;
        RECT 0.610 46.210 188.030 47.030 ;
        RECT 0.335 46.190 188.305 46.210 ;
        RECT 0.610 45.370 188.030 46.190 ;
        RECT 0.335 45.350 188.305 45.370 ;
        RECT 0.610 44.530 188.030 45.350 ;
        RECT 0.335 44.510 188.305 44.530 ;
        RECT 0.610 43.690 188.030 44.510 ;
        RECT 0.335 43.670 188.305 43.690 ;
        RECT 0.610 42.850 188.030 43.670 ;
        RECT 0.335 42.830 188.305 42.850 ;
        RECT 0.610 42.010 188.030 42.830 ;
        RECT 0.335 41.990 188.305 42.010 ;
        RECT 0.610 41.170 188.030 41.990 ;
        RECT 0.335 41.150 188.305 41.170 ;
        RECT 0.610 40.330 188.030 41.150 ;
        RECT 0.335 40.310 188.305 40.330 ;
        RECT 0.610 39.490 188.030 40.310 ;
        RECT 0.335 32.750 188.305 39.490 ;
        RECT 0.610 31.930 188.030 32.750 ;
        RECT 0.335 31.070 188.305 31.930 ;
        RECT 0.610 30.250 188.030 31.070 ;
        RECT 0.335 29.390 188.305 30.250 ;
        RECT 0.610 28.570 188.030 29.390 ;
        RECT 0.335 27.710 188.305 28.570 ;
        RECT 0.610 26.890 188.030 27.710 ;
        RECT 0.335 26.030 188.305 26.890 ;
        RECT 0.610 25.210 188.030 26.030 ;
        RECT 0.335 24.350 188.305 25.210 ;
        RECT 0.610 23.530 188.030 24.350 ;
        RECT 0.335 22.670 188.305 23.530 ;
        RECT 0.610 21.850 188.030 22.670 ;
        RECT 0.335 20.990 188.305 21.850 ;
        RECT 0.610 20.170 188.030 20.990 ;
        RECT 0.335 16.790 188.305 20.170 ;
        RECT 0.610 15.970 188.030 16.790 ;
        RECT 0.335 15.950 188.305 15.970 ;
        RECT 0.610 15.130 188.030 15.950 ;
        RECT 0.335 15.110 188.305 15.130 ;
        RECT 0.610 14.290 188.030 15.110 ;
        RECT 0.335 14.270 188.305 14.290 ;
        RECT 0.610 13.450 188.030 14.270 ;
        RECT 0.335 13.430 188.305 13.450 ;
        RECT 0.610 12.610 188.030 13.430 ;
        RECT 0.335 12.590 188.305 12.610 ;
        RECT 0.610 11.770 188.030 12.590 ;
        RECT 0.335 11.750 188.305 11.770 ;
        RECT 0.610 10.930 188.030 11.750 ;
        RECT 0.335 10.910 188.305 10.930 ;
        RECT 0.610 10.090 188.030 10.910 ;
        RECT 0.335 6.710 188.305 10.090 ;
        RECT 0.610 5.890 188.030 6.710 ;
        RECT 0.335 5.030 188.305 5.890 ;
        RECT 0.610 4.210 188.030 5.030 ;
        RECT 0.335 3.350 188.305 4.210 ;
        RECT 0.610 2.530 188.030 3.350 ;
        RECT 0.335 1.670 188.305 2.530 ;
        RECT 0.610 0.850 188.030 1.670 ;
        RECT 0.335 0.315 188.305 0.850 ;
      LAYER Metal4 ;
        RECT 0.380 0.275 15.170 430.645 ;
        RECT 17.790 0.275 21.370 430.645 ;
        RECT 23.990 0.275 90.770 430.645 ;
        RECT 93.390 0.275 96.970 430.645 ;
        RECT 99.590 0.275 166.370 430.645 ;
        RECT 168.990 0.275 172.570 430.645 ;
        RECT 175.190 0.275 188.260 430.645 ;
      LAYER TopMetal1 ;
        RECT 2.060 5.380 186.580 417.420 ;
  END
END DSP
END LIBRARY

